# Derived ASAP7 FakeRAM physical-flow model; not a signoff SRAM model
VERSION 5.7 ;
BUSBITCHARS "[]" ;
PROPERTYDEFINITIONS
  MACRO width INTEGER ;
  MACRO depth INTEGER ;
  MACRO banks INTEGER ;
END PROPERTYDEFINITIONS
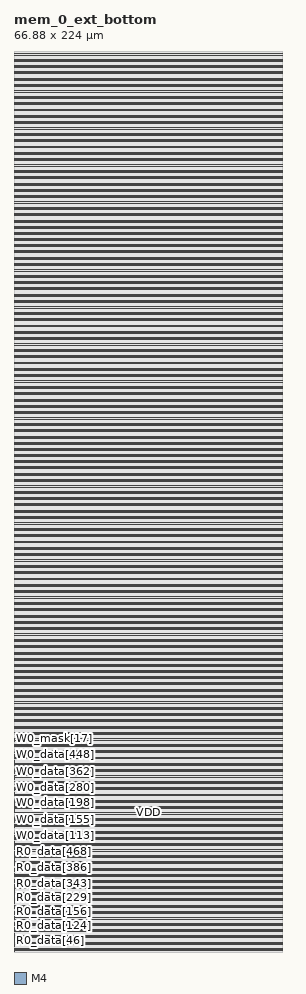
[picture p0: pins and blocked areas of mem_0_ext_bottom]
MACRO mem_0_ext_bottom
  PROPERTY width 512 ;
  PROPERTY depth 512 ;
  PROPERTY banks 1 ;
  FOREIGN mem_0_ext_bottom 0 0 ;
  SYMMETRY X Y ;
  SIZE 66.880 BY 224.000 ;
  CLASS BLOCK ;
  PIN R0_addr[0]
    DIRECTION INPUT ;
    USE SIGNAL ;
    SHAPE ABUTMENT ;
    PORT
      LAYER M4 ;
      RECT 0.000 0.048 0.024 0.072 ;
    END
  END R0_addr[0]
  PIN R0_addr[1]
    DIRECTION INPUT ;
    USE SIGNAL ;
    SHAPE ABUTMENT ;
    PORT
      LAYER M4 ;
      RECT 0.000 0.096 0.024 0.120 ;
    END
  END R0_addr[1]
  PIN R0_addr[2]
    DIRECTION INPUT ;
    USE SIGNAL ;
    SHAPE ABUTMENT ;
    PORT
      LAYER M4 ;
      RECT 0.000 0.144 0.024 0.168 ;
    END
  END R0_addr[2]
  PIN R0_addr[3]
    DIRECTION INPUT ;
    USE SIGNAL ;
    SHAPE ABUTMENT ;
    PORT
      LAYER M4 ;
      RECT 0.000 0.192 0.024 0.216 ;
    END
  END R0_addr[3]
  PIN R0_addr[4]
    DIRECTION INPUT ;
    USE SIGNAL ;
    SHAPE ABUTMENT ;
    PORT
      LAYER M4 ;
      RECT 0.000 0.240 0.024 0.264 ;
    END
  END R0_addr[4]
  PIN R0_addr[5]
    DIRECTION INPUT ;
    USE SIGNAL ;
    SHAPE ABUTMENT ;
    PORT
      LAYER M4 ;
      RECT 0.000 0.288 0.024 0.312 ;
    END
  END R0_addr[5]
  PIN R0_addr[6]
    DIRECTION INPUT ;
    USE SIGNAL ;
    SHAPE ABUTMENT ;
    PORT
      LAYER M4 ;
      RECT 0.000 0.336 0.024 0.360 ;
    END
  END R0_addr[6]
  PIN R0_addr[7]
    DIRECTION INPUT ;
    USE SIGNAL ;
    SHAPE ABUTMENT ;
    PORT
      LAYER M4 ;
      RECT 0.000 0.384 0.024 0.408 ;
    END
  END R0_addr[7]
  PIN R0_addr[8]
    DIRECTION INPUT ;
    USE SIGNAL ;
    SHAPE ABUTMENT ;
    PORT
      LAYER M4 ;
      RECT 0.000 0.432 0.024 0.456 ;
    END
  END R0_addr[8]
  PIN R0_clk
    DIRECTION INPUT ;
    USE SIGNAL ;
    SHAPE ABUTMENT ;
    PORT
      LAYER M4 ;
      RECT 0.000 0.480 0.024 0.504 ;
    END
  END R0_clk
  PIN R0_data[0]
    DIRECTION OUTPUT ;
    USE SIGNAL ;
    SHAPE ABUTMENT ;
    PORT
      LAYER M4 ;
      RECT 0.000 0.528 0.024 0.552 ;
    END
  END R0_data[0]
  PIN R0_data[1]
    DIRECTION OUTPUT ;
    USE SIGNAL ;
    SHAPE ABUTMENT ;
    PORT
      LAYER M4 ;
      RECT 0.000 0.576 0.024 0.600 ;
    END
  END R0_data[1]
  PIN R0_data[2]
    DIRECTION OUTPUT ;
    USE SIGNAL ;
    SHAPE ABUTMENT ;
    PORT
      LAYER M4 ;
      RECT 0.000 0.624 0.024 0.648 ;
    END
  END R0_data[2]
  PIN R0_data[3]
    DIRECTION OUTPUT ;
    USE SIGNAL ;
    SHAPE ABUTMENT ;
    PORT
      LAYER M4 ;
      RECT 0.000 0.672 0.024 0.696 ;
    END
  END R0_data[3]
  PIN R0_data[4]
    DIRECTION OUTPUT ;
    USE SIGNAL ;
    SHAPE ABUTMENT ;
    PORT
      LAYER M4 ;
      RECT 0.000 0.720 0.024 0.744 ;
    END
  END R0_data[4]
  PIN R0_data[5]
    DIRECTION OUTPUT ;
    USE SIGNAL ;
    SHAPE ABUTMENT ;
    PORT
      LAYER M4 ;
      RECT 0.000 0.768 0.024 0.792 ;
    END
  END R0_data[5]
  PIN R0_data[6]
    DIRECTION OUTPUT ;
    USE SIGNAL ;
    SHAPE ABUTMENT ;
    PORT
      LAYER M4 ;
      RECT 0.000 0.816 0.024 0.840 ;
    END
  END R0_data[6]
  PIN R0_data[7]
    DIRECTION OUTPUT ;
    USE SIGNAL ;
    SHAPE ABUTMENT ;
    PORT
      LAYER M4 ;
      RECT 0.000 0.864 0.024 0.888 ;
    END
  END R0_data[7]
  PIN R0_data[8]
    DIRECTION OUTPUT ;
    USE SIGNAL ;
    SHAPE ABUTMENT ;
    PORT
      LAYER M4 ;
      RECT 0.000 0.912 0.024 0.936 ;
    END
  END R0_data[8]
  PIN R0_data[9]
    DIRECTION OUTPUT ;
    USE SIGNAL ;
    SHAPE ABUTMENT ;
    PORT
      LAYER M4 ;
      RECT 0.000 0.960 0.024 0.984 ;
    END
  END R0_data[9]
  PIN R0_data[10]
    DIRECTION OUTPUT ;
    USE SIGNAL ;
    SHAPE ABUTMENT ;
    PORT
      LAYER M4 ;
      RECT 0.000 1.008 0.024 1.032 ;
    END
  END R0_data[10]
  PIN R0_data[11]
    DIRECTION OUTPUT ;
    USE SIGNAL ;
    SHAPE ABUTMENT ;
    PORT
      LAYER M4 ;
      RECT 0.000 1.056 0.024 1.080 ;
    END
  END R0_data[11]
  PIN R0_data[12]
    DIRECTION OUTPUT ;
    USE SIGNAL ;
    SHAPE ABUTMENT ;
    PORT
      LAYER M4 ;
      RECT 0.000 1.104 0.024 1.128 ;
    END
  END R0_data[12]
  PIN R0_data[13]
    DIRECTION OUTPUT ;
    USE SIGNAL ;
    SHAPE ABUTMENT ;
    PORT
      LAYER M4 ;
      RECT 0.000 1.152 0.024 1.176 ;
    END
  END R0_data[13]
  PIN R0_data[14]
    DIRECTION OUTPUT ;
    USE SIGNAL ;
    SHAPE ABUTMENT ;
    PORT
      LAYER M4 ;
      RECT 0.000 1.200 0.024 1.224 ;
    END
  END R0_data[14]
  PIN R0_data[15]
    DIRECTION OUTPUT ;
    USE SIGNAL ;
    SHAPE ABUTMENT ;
    PORT
      LAYER M4 ;
      RECT 0.000 1.248 0.024 1.272 ;
    END
  END R0_data[15]
  PIN R0_data[16]
    DIRECTION OUTPUT ;
    USE SIGNAL ;
    SHAPE ABUTMENT ;
    PORT
      LAYER M4 ;
      RECT 0.000 1.296 0.024 1.320 ;
    END
  END R0_data[16]
  PIN R0_data[17]
    DIRECTION OUTPUT ;
    USE SIGNAL ;
    SHAPE ABUTMENT ;
    PORT
      LAYER M4 ;
      RECT 0.000 1.344 0.024 1.368 ;
    END
  END R0_data[17]
  PIN R0_data[18]
    DIRECTION OUTPUT ;
    USE SIGNAL ;
    SHAPE ABUTMENT ;
    PORT
      LAYER M4 ;
      RECT 0.000 1.392 0.024 1.416 ;
    END
  END R0_data[18]
  PIN R0_data[19]
    DIRECTION OUTPUT ;
    USE SIGNAL ;
    SHAPE ABUTMENT ;
    PORT
      LAYER M4 ;
      RECT 0.000 1.440 0.024 1.464 ;
    END
  END R0_data[19]
  PIN R0_data[20]
    DIRECTION OUTPUT ;
    USE SIGNAL ;
    SHAPE ABUTMENT ;
    PORT
      LAYER M4 ;
      RECT 0.000 1.488 0.024 1.512 ;
    END
  END R0_data[20]
  PIN R0_data[21]
    DIRECTION OUTPUT ;
    USE SIGNAL ;
    SHAPE ABUTMENT ;
    PORT
      LAYER M4 ;
      RECT 0.000 1.536 0.024 1.560 ;
    END
  END R0_data[21]
  PIN R0_data[22]
    DIRECTION OUTPUT ;
    USE SIGNAL ;
    SHAPE ABUTMENT ;
    PORT
      LAYER M4 ;
      RECT 0.000 1.584 0.024 1.608 ;
    END
  END R0_data[22]
  PIN R0_data[23]
    DIRECTION OUTPUT ;
    USE SIGNAL ;
    SHAPE ABUTMENT ;
    PORT
      LAYER M4 ;
      RECT 0.000 1.632 0.024 1.656 ;
    END
  END R0_data[23]
  PIN R0_data[24]
    DIRECTION OUTPUT ;
    USE SIGNAL ;
    SHAPE ABUTMENT ;
    PORT
      LAYER M4 ;
      RECT 0.000 1.680 0.024 1.704 ;
    END
  END R0_data[24]
  PIN R0_data[25]
    DIRECTION OUTPUT ;
    USE SIGNAL ;
    SHAPE ABUTMENT ;
    PORT
      LAYER M4 ;
      RECT 0.000 1.728 0.024 1.752 ;
    END
  END R0_data[25]
  PIN R0_data[26]
    DIRECTION OUTPUT ;
    USE SIGNAL ;
    SHAPE ABUTMENT ;
    PORT
      LAYER M4 ;
      RECT 0.000 1.776 0.024 1.800 ;
    END
  END R0_data[26]
  PIN R0_data[27]
    DIRECTION OUTPUT ;
    USE SIGNAL ;
    SHAPE ABUTMENT ;
    PORT
      LAYER M4 ;
      RECT 0.000 1.824 0.024 1.848 ;
    END
  END R0_data[27]
  PIN R0_data[28]
    DIRECTION OUTPUT ;
    USE SIGNAL ;
    SHAPE ABUTMENT ;
    PORT
      LAYER M4 ;
      RECT 0.000 1.872 0.024 1.896 ;
    END
  END R0_data[28]
  PIN R0_data[29]
    DIRECTION OUTPUT ;
    USE SIGNAL ;
    SHAPE ABUTMENT ;
    PORT
      LAYER M4 ;
      RECT 0.000 1.920 0.024 1.944 ;
    END
  END R0_data[29]
  PIN R0_data[30]
    DIRECTION OUTPUT ;
    USE SIGNAL ;
    SHAPE ABUTMENT ;
    PORT
      LAYER M4 ;
      RECT 0.000 1.968 0.024 1.992 ;
    END
  END R0_data[30]
  PIN R0_data[31]
    DIRECTION OUTPUT ;
    USE SIGNAL ;
    SHAPE ABUTMENT ;
    PORT
      LAYER M4 ;
      RECT 0.000 2.016 0.024 2.040 ;
    END
  END R0_data[31]
  PIN R0_data[32]
    DIRECTION OUTPUT ;
    USE SIGNAL ;
    SHAPE ABUTMENT ;
    PORT
      LAYER M4 ;
      RECT 0.000 2.064 0.024 2.088 ;
    END
  END R0_data[32]
  PIN R0_data[33]
    DIRECTION OUTPUT ;
    USE SIGNAL ;
    SHAPE ABUTMENT ;
    PORT
      LAYER M4 ;
      RECT 0.000 2.112 0.024 2.136 ;
    END
  END R0_data[33]
  PIN R0_data[34]
    DIRECTION OUTPUT ;
    USE SIGNAL ;
    SHAPE ABUTMENT ;
    PORT
      LAYER M4 ;
      RECT 0.000 2.160 0.024 2.184 ;
    END
  END R0_data[34]
  PIN R0_data[35]
    DIRECTION OUTPUT ;
    USE SIGNAL ;
    SHAPE ABUTMENT ;
    PORT
      LAYER M4 ;
      RECT 0.000 2.208 0.024 2.232 ;
    END
  END R0_data[35]
  PIN R0_data[36]
    DIRECTION OUTPUT ;
    USE SIGNAL ;
    SHAPE ABUTMENT ;
    PORT
      LAYER M4 ;
      RECT 0.000 2.256 0.024 2.280 ;
    END
  END R0_data[36]
  PIN R0_data[37]
    DIRECTION OUTPUT ;
    USE SIGNAL ;
    SHAPE ABUTMENT ;
    PORT
      LAYER M4 ;
      RECT 0.000 2.304 0.024 2.328 ;
    END
  END R0_data[37]
  PIN R0_data[38]
    DIRECTION OUTPUT ;
    USE SIGNAL ;
    SHAPE ABUTMENT ;
    PORT
      LAYER M4 ;
      RECT 0.000 2.352 0.024 2.376 ;
    END
  END R0_data[38]
  PIN R0_data[39]
    DIRECTION OUTPUT ;
    USE SIGNAL ;
    SHAPE ABUTMENT ;
    PORT
      LAYER M4 ;
      RECT 0.000 2.400 0.024 2.424 ;
    END
  END R0_data[39]
  PIN R0_data[40]
    DIRECTION OUTPUT ;
    USE SIGNAL ;
    SHAPE ABUTMENT ;
    PORT
      LAYER M4 ;
      RECT 0.000 2.448 0.024 2.472 ;
    END
  END R0_data[40]
  PIN R0_data[41]
    DIRECTION OUTPUT ;
    USE SIGNAL ;
    SHAPE ABUTMENT ;
    PORT
      LAYER M4 ;
      RECT 0.000 2.496 0.024 2.520 ;
    END
  END R0_data[41]
  PIN R0_data[42]
    DIRECTION OUTPUT ;
    USE SIGNAL ;
    SHAPE ABUTMENT ;
    PORT
      LAYER M4 ;
      RECT 0.000 2.544 0.024 2.568 ;
    END
  END R0_data[42]
  PIN R0_data[43]
    DIRECTION OUTPUT ;
    USE SIGNAL ;
    SHAPE ABUTMENT ;
    PORT
      LAYER M4 ;
      RECT 0.000 2.592 0.024 2.616 ;
    END
  END R0_data[43]
  PIN R0_data[44]
    DIRECTION OUTPUT ;
    USE SIGNAL ;
    SHAPE ABUTMENT ;
    PORT
      LAYER M4 ;
      RECT 0.000 2.640 0.024 2.664 ;
    END
  END R0_data[44]
  PIN R0_data[45]
    DIRECTION OUTPUT ;
    USE SIGNAL ;
    SHAPE ABUTMENT ;
    PORT
      LAYER M4 ;
      RECT 0.000 2.688 0.024 2.712 ;
    END
  END R0_data[45]
  PIN R0_data[46]
    DIRECTION OUTPUT ;
    USE SIGNAL ;
    SHAPE ABUTMENT ;
    PORT
      LAYER M4 ;
      RECT 0.000 2.736 0.024 2.760 ;
    END
  END R0_data[46]
  PIN R0_data[47]
    DIRECTION OUTPUT ;
    USE SIGNAL ;
    SHAPE ABUTMENT ;
    PORT
      LAYER M4 ;
      RECT 0.000 2.784 0.024 2.808 ;
    END
  END R0_data[47]
  PIN R0_data[48]
    DIRECTION OUTPUT ;
    USE SIGNAL ;
    SHAPE ABUTMENT ;
    PORT
      LAYER M4 ;
      RECT 0.000 2.832 0.024 2.856 ;
    END
  END R0_data[48]
  PIN R0_data[49]
    DIRECTION OUTPUT ;
    USE SIGNAL ;
    SHAPE ABUTMENT ;
    PORT
      LAYER M4 ;
      RECT 0.000 2.880 0.024 2.904 ;
    END
  END R0_data[49]
  PIN R0_data[50]
    DIRECTION OUTPUT ;
    USE SIGNAL ;
    SHAPE ABUTMENT ;
    PORT
      LAYER M4 ;
      RECT 0.000 2.928 0.024 2.952 ;
    END
  END R0_data[50]
  PIN R0_data[51]
    DIRECTION OUTPUT ;
    USE SIGNAL ;
    SHAPE ABUTMENT ;
    PORT
      LAYER M4 ;
      RECT 0.000 2.976 0.024 3.000 ;
    END
  END R0_data[51]
  PIN R0_data[52]
    DIRECTION OUTPUT ;
    USE SIGNAL ;
    SHAPE ABUTMENT ;
    PORT
      LAYER M4 ;
      RECT 0.000 3.024 0.024 3.048 ;
    END
  END R0_data[52]
  PIN R0_data[53]
    DIRECTION OUTPUT ;
    USE SIGNAL ;
    SHAPE ABUTMENT ;
    PORT
      LAYER M4 ;
      RECT 0.000 3.072 0.024 3.096 ;
    END
  END R0_data[53]
  PIN R0_data[54]
    DIRECTION OUTPUT ;
    USE SIGNAL ;
    SHAPE ABUTMENT ;
    PORT
      LAYER M4 ;
      RECT 0.000 3.120 0.024 3.144 ;
    END
  END R0_data[54]
  PIN R0_data[55]
    DIRECTION OUTPUT ;
    USE SIGNAL ;
    SHAPE ABUTMENT ;
    PORT
      LAYER M4 ;
      RECT 0.000 3.168 0.024 3.192 ;
    END
  END R0_data[55]
  PIN R0_data[56]
    DIRECTION OUTPUT ;
    USE SIGNAL ;
    SHAPE ABUTMENT ;
    PORT
      LAYER M4 ;
      RECT 0.000 3.216 0.024 3.240 ;
    END
  END R0_data[56]
  PIN R0_data[57]
    DIRECTION OUTPUT ;
    USE SIGNAL ;
    SHAPE ABUTMENT ;
    PORT
      LAYER M4 ;
      RECT 0.000 3.264 0.024 3.288 ;
    END
  END R0_data[57]
  PIN R0_data[58]
    DIRECTION OUTPUT ;
    USE SIGNAL ;
    SHAPE ABUTMENT ;
    PORT
      LAYER M4 ;
      RECT 0.000 3.312 0.024 3.336 ;
    END
  END R0_data[58]
  PIN R0_data[59]
    DIRECTION OUTPUT ;
    USE SIGNAL ;
    SHAPE ABUTMENT ;
    PORT
      LAYER M4 ;
      RECT 0.000 3.360 0.024 3.384 ;
    END
  END R0_data[59]
  PIN R0_data[60]
    DIRECTION OUTPUT ;
    USE SIGNAL ;
    SHAPE ABUTMENT ;
    PORT
      LAYER M4 ;
      RECT 0.000 3.408 0.024 3.432 ;
    END
  END R0_data[60]
  PIN R0_data[61]
    DIRECTION OUTPUT ;
    USE SIGNAL ;
    SHAPE ABUTMENT ;
    PORT
      LAYER M4 ;
      RECT 0.000 3.456 0.024 3.480 ;
    END
  END R0_data[61]
  PIN R0_data[62]
    DIRECTION OUTPUT ;
    USE SIGNAL ;
    SHAPE ABUTMENT ;
    PORT
      LAYER M4 ;
      RECT 0.000 3.504 0.024 3.528 ;
    END
  END R0_data[62]
  PIN R0_data[63]
    DIRECTION OUTPUT ;
    USE SIGNAL ;
    SHAPE ABUTMENT ;
    PORT
      LAYER M4 ;
      RECT 0.000 3.552 0.024 3.576 ;
    END
  END R0_data[63]
  PIN R0_data[64]
    DIRECTION OUTPUT ;
    USE SIGNAL ;
    SHAPE ABUTMENT ;
    PORT
      LAYER M4 ;
      RECT 0.000 3.600 0.024 3.624 ;
    END
  END R0_data[64]
  PIN R0_data[65]
    DIRECTION OUTPUT ;
    USE SIGNAL ;
    SHAPE ABUTMENT ;
    PORT
      LAYER M4 ;
      RECT 0.000 3.648 0.024 3.672 ;
    END
  END R0_data[65]
  PIN R0_data[66]
    DIRECTION OUTPUT ;
    USE SIGNAL ;
    SHAPE ABUTMENT ;
    PORT
      LAYER M4 ;
      RECT 0.000 3.696 0.024 3.720 ;
    END
  END R0_data[66]
  PIN R0_data[67]
    DIRECTION OUTPUT ;
    USE SIGNAL ;
    SHAPE ABUTMENT ;
    PORT
      LAYER M4 ;
      RECT 0.000 3.744 0.024 3.768 ;
    END
  END R0_data[67]
  PIN R0_data[68]
    DIRECTION OUTPUT ;
    USE SIGNAL ;
    SHAPE ABUTMENT ;
    PORT
      LAYER M4 ;
      RECT 0.000 3.792 0.024 3.816 ;
    END
  END R0_data[68]
  PIN R0_data[69]
    DIRECTION OUTPUT ;
    USE SIGNAL ;
    SHAPE ABUTMENT ;
    PORT
      LAYER M4 ;
      RECT 0.000 3.840 0.024 3.864 ;
    END
  END R0_data[69]
  PIN R0_data[70]
    DIRECTION OUTPUT ;
    USE SIGNAL ;
    SHAPE ABUTMENT ;
    PORT
      LAYER M4 ;
      RECT 0.000 3.888 0.024 3.912 ;
    END
  END R0_data[70]
  PIN R0_data[71]
    DIRECTION OUTPUT ;
    USE SIGNAL ;
    SHAPE ABUTMENT ;
    PORT
      LAYER M4 ;
      RECT 0.000 3.936 0.024 3.960 ;
    END
  END R0_data[71]
  PIN R0_data[72]
    DIRECTION OUTPUT ;
    USE SIGNAL ;
    SHAPE ABUTMENT ;
    PORT
      LAYER M4 ;
      RECT 0.000 3.984 0.024 4.008 ;
    END
  END R0_data[72]
  PIN R0_data[73]
    DIRECTION OUTPUT ;
    USE SIGNAL ;
    SHAPE ABUTMENT ;
    PORT
      LAYER M4 ;
      RECT 0.000 4.032 0.024 4.056 ;
    END
  END R0_data[73]
  PIN R0_data[74]
    DIRECTION OUTPUT ;
    USE SIGNAL ;
    SHAPE ABUTMENT ;
    PORT
      LAYER M4 ;
      RECT 0.000 4.080 0.024 4.104 ;
    END
  END R0_data[74]
  PIN R0_data[75]
    DIRECTION OUTPUT ;
    USE SIGNAL ;
    SHAPE ABUTMENT ;
    PORT
      LAYER M4 ;
      RECT 0.000 4.128 0.024 4.152 ;
    END
  END R0_data[75]
  PIN R0_data[76]
    DIRECTION OUTPUT ;
    USE SIGNAL ;
    SHAPE ABUTMENT ;
    PORT
      LAYER M4 ;
      RECT 0.000 4.176 0.024 4.200 ;
    END
  END R0_data[76]
  PIN R0_data[77]
    DIRECTION OUTPUT ;
    USE SIGNAL ;
    SHAPE ABUTMENT ;
    PORT
      LAYER M4 ;
      RECT 0.000 4.224 0.024 4.248 ;
    END
  END R0_data[77]
  PIN R0_data[78]
    DIRECTION OUTPUT ;
    USE SIGNAL ;
    SHAPE ABUTMENT ;
    PORT
      LAYER M4 ;
      RECT 0.000 4.272 0.024 4.296 ;
    END
  END R0_data[78]
  PIN R0_data[79]
    DIRECTION OUTPUT ;
    USE SIGNAL ;
    SHAPE ABUTMENT ;
    PORT
      LAYER M4 ;
      RECT 0.000 4.320 0.024 4.344 ;
    END
  END R0_data[79]
  PIN R0_data[80]
    DIRECTION OUTPUT ;
    USE SIGNAL ;
    SHAPE ABUTMENT ;
    PORT
      LAYER M4 ;
      RECT 0.000 4.368 0.024 4.392 ;
    END
  END R0_data[80]
  PIN R0_data[81]
    DIRECTION OUTPUT ;
    USE SIGNAL ;
    SHAPE ABUTMENT ;
    PORT
      LAYER M4 ;
      RECT 0.000 4.416 0.024 4.440 ;
    END
  END R0_data[81]
  PIN R0_data[82]
    DIRECTION OUTPUT ;
    USE SIGNAL ;
    SHAPE ABUTMENT ;
    PORT
      LAYER M4 ;
      RECT 0.000 4.464 0.024 4.488 ;
    END
  END R0_data[82]
  PIN R0_data[83]
    DIRECTION OUTPUT ;
    USE SIGNAL ;
    SHAPE ABUTMENT ;
    PORT
      LAYER M4 ;
      RECT 0.000 4.512 0.024 4.536 ;
    END
  END R0_data[83]
  PIN R0_data[84]
    DIRECTION OUTPUT ;
    USE SIGNAL ;
    SHAPE ABUTMENT ;
    PORT
      LAYER M4 ;
      RECT 0.000 4.560 0.024 4.584 ;
    END
  END R0_data[84]
  PIN R0_data[85]
    DIRECTION OUTPUT ;
    USE SIGNAL ;
    SHAPE ABUTMENT ;
    PORT
      LAYER M4 ;
      RECT 0.000 4.608 0.024 4.632 ;
    END
  END R0_data[85]
  PIN R0_data[86]
    DIRECTION OUTPUT ;
    USE SIGNAL ;
    SHAPE ABUTMENT ;
    PORT
      LAYER M4 ;
      RECT 0.000 4.656 0.024 4.680 ;
    END
  END R0_data[86]
  PIN R0_data[87]
    DIRECTION OUTPUT ;
    USE SIGNAL ;
    SHAPE ABUTMENT ;
    PORT
      LAYER M4 ;
      RECT 0.000 4.704 0.024 4.728 ;
    END
  END R0_data[87]
  PIN R0_data[88]
    DIRECTION OUTPUT ;
    USE SIGNAL ;
    SHAPE ABUTMENT ;
    PORT
      LAYER M4 ;
      RECT 0.000 4.752 0.024 4.776 ;
    END
  END R0_data[88]
  PIN R0_data[89]
    DIRECTION OUTPUT ;
    USE SIGNAL ;
    SHAPE ABUTMENT ;
    PORT
      LAYER M4 ;
      RECT 0.000 4.800 0.024 4.824 ;
    END
  END R0_data[89]
  PIN R0_data[90]
    DIRECTION OUTPUT ;
    USE SIGNAL ;
    SHAPE ABUTMENT ;
    PORT
      LAYER M4 ;
      RECT 0.000 4.848 0.024 4.872 ;
    END
  END R0_data[90]
  PIN R0_data[91]
    DIRECTION OUTPUT ;
    USE SIGNAL ;
    SHAPE ABUTMENT ;
    PORT
      LAYER M4 ;
      RECT 0.000 4.896 0.024 4.920 ;
    END
  END R0_data[91]
  PIN R0_data[92]
    DIRECTION OUTPUT ;
    USE SIGNAL ;
    SHAPE ABUTMENT ;
    PORT
      LAYER M4 ;
      RECT 0.000 4.944 0.024 4.968 ;
    END
  END R0_data[92]
  PIN R0_data[93]
    DIRECTION OUTPUT ;
    USE SIGNAL ;
    SHAPE ABUTMENT ;
    PORT
      LAYER M4 ;
      RECT 0.000 4.992 0.024 5.016 ;
    END
  END R0_data[93]
  PIN R0_data[94]
    DIRECTION OUTPUT ;
    USE SIGNAL ;
    SHAPE ABUTMENT ;
    PORT
      LAYER M4 ;
      RECT 0.000 5.040 0.024 5.064 ;
    END
  END R0_data[94]
  PIN R0_data[95]
    DIRECTION OUTPUT ;
    USE SIGNAL ;
    SHAPE ABUTMENT ;
    PORT
      LAYER M4 ;
      RECT 0.000 5.088 0.024 5.112 ;
    END
  END R0_data[95]
  PIN R0_data[96]
    DIRECTION OUTPUT ;
    USE SIGNAL ;
    SHAPE ABUTMENT ;
    PORT
      LAYER M4 ;
      RECT 0.000 5.136 0.024 5.160 ;
    END
  END R0_data[96]
  PIN R0_data[97]
    DIRECTION OUTPUT ;
    USE SIGNAL ;
    SHAPE ABUTMENT ;
    PORT
      LAYER M4 ;
      RECT 0.000 5.184 0.024 5.208 ;
    END
  END R0_data[97]
  PIN R0_data[98]
    DIRECTION OUTPUT ;
    USE SIGNAL ;
    SHAPE ABUTMENT ;
    PORT
      LAYER M4 ;
      RECT 0.000 5.232 0.024 5.256 ;
    END
  END R0_data[98]
  PIN R0_data[99]
    DIRECTION OUTPUT ;
    USE SIGNAL ;
    SHAPE ABUTMENT ;
    PORT
      LAYER M4 ;
      RECT 0.000 5.280 0.024 5.304 ;
    END
  END R0_data[99]
  PIN R0_data[100]
    DIRECTION OUTPUT ;
    USE SIGNAL ;
    SHAPE ABUTMENT ;
    PORT
      LAYER M4 ;
      RECT 0.000 5.328 0.024 5.352 ;
    END
  END R0_data[100]
  PIN R0_data[101]
    DIRECTION OUTPUT ;
    USE SIGNAL ;
    SHAPE ABUTMENT ;
    PORT
      LAYER M4 ;
      RECT 0.000 5.376 0.024 5.400 ;
    END
  END R0_data[101]
  PIN R0_data[102]
    DIRECTION OUTPUT ;
    USE SIGNAL ;
    SHAPE ABUTMENT ;
    PORT
      LAYER M4 ;
      RECT 0.000 5.424 0.024 5.448 ;
    END
  END R0_data[102]
  PIN R0_data[103]
    DIRECTION OUTPUT ;
    USE SIGNAL ;
    SHAPE ABUTMENT ;
    PORT
      LAYER M4 ;
      RECT 0.000 5.472 0.024 5.496 ;
    END
  END R0_data[103]
  PIN R0_data[104]
    DIRECTION OUTPUT ;
    USE SIGNAL ;
    SHAPE ABUTMENT ;
    PORT
      LAYER M4 ;
      RECT 0.000 5.520 0.024 5.544 ;
    END
  END R0_data[104]
  PIN R0_data[105]
    DIRECTION OUTPUT ;
    USE SIGNAL ;
    SHAPE ABUTMENT ;
    PORT
      LAYER M4 ;
      RECT 0.000 5.568 0.024 5.592 ;
    END
  END R0_data[105]
  PIN R0_data[106]
    DIRECTION OUTPUT ;
    USE SIGNAL ;
    SHAPE ABUTMENT ;
    PORT
      LAYER M4 ;
      RECT 0.000 5.616 0.024 5.640 ;
    END
  END R0_data[106]
  PIN R0_data[107]
    DIRECTION OUTPUT ;
    USE SIGNAL ;
    SHAPE ABUTMENT ;
    PORT
      LAYER M4 ;
      RECT 0.000 5.664 0.024 5.688 ;
    END
  END R0_data[107]
  PIN R0_data[108]
    DIRECTION OUTPUT ;
    USE SIGNAL ;
    SHAPE ABUTMENT ;
    PORT
      LAYER M4 ;
      RECT 0.000 5.712 0.024 5.736 ;
    END
  END R0_data[108]
  PIN R0_data[109]
    DIRECTION OUTPUT ;
    USE SIGNAL ;
    SHAPE ABUTMENT ;
    PORT
      LAYER M4 ;
      RECT 0.000 5.760 0.024 5.784 ;
    END
  END R0_data[109]
  PIN R0_data[110]
    DIRECTION OUTPUT ;
    USE SIGNAL ;
    SHAPE ABUTMENT ;
    PORT
      LAYER M4 ;
      RECT 0.000 5.808 0.024 5.832 ;
    END
  END R0_data[110]
  PIN R0_data[111]
    DIRECTION OUTPUT ;
    USE SIGNAL ;
    SHAPE ABUTMENT ;
    PORT
      LAYER M4 ;
      RECT 0.000 5.856 0.024 5.880 ;
    END
  END R0_data[111]
  PIN R0_data[112]
    DIRECTION OUTPUT ;
    USE SIGNAL ;
    SHAPE ABUTMENT ;
    PORT
      LAYER M4 ;
      RECT 0.000 5.904 0.024 5.928 ;
    END
  END R0_data[112]
  PIN R0_data[113]
    DIRECTION OUTPUT ;
    USE SIGNAL ;
    SHAPE ABUTMENT ;
    PORT
      LAYER M4 ;
      RECT 0.000 5.952 0.024 5.976 ;
    END
  END R0_data[113]
  PIN R0_data[114]
    DIRECTION OUTPUT ;
    USE SIGNAL ;
    SHAPE ABUTMENT ;
    PORT
      LAYER M4 ;
      RECT 0.000 6.000 0.024 6.024 ;
    END
  END R0_data[114]
  PIN R0_data[115]
    DIRECTION OUTPUT ;
    USE SIGNAL ;
    SHAPE ABUTMENT ;
    PORT
      LAYER M4 ;
      RECT 0.000 6.048 0.024 6.072 ;
    END
  END R0_data[115]
  PIN R0_data[116]
    DIRECTION OUTPUT ;
    USE SIGNAL ;
    SHAPE ABUTMENT ;
    PORT
      LAYER M4 ;
      RECT 0.000 6.096 0.024 6.120 ;
    END
  END R0_data[116]
  PIN R0_data[117]
    DIRECTION OUTPUT ;
    USE SIGNAL ;
    SHAPE ABUTMENT ;
    PORT
      LAYER M4 ;
      RECT 0.000 6.144 0.024 6.168 ;
    END
  END R0_data[117]
  PIN R0_data[118]
    DIRECTION OUTPUT ;
    USE SIGNAL ;
    SHAPE ABUTMENT ;
    PORT
      LAYER M4 ;
      RECT 0.000 6.192 0.024 6.216 ;
    END
  END R0_data[118]
  PIN R0_data[119]
    DIRECTION OUTPUT ;
    USE SIGNAL ;
    SHAPE ABUTMENT ;
    PORT
      LAYER M4 ;
      RECT 0.000 6.240 0.024 6.264 ;
    END
  END R0_data[119]
  PIN R0_data[120]
    DIRECTION OUTPUT ;
    USE SIGNAL ;
    SHAPE ABUTMENT ;
    PORT
      LAYER M4 ;
      RECT 0.000 6.288 0.024 6.312 ;
    END
  END R0_data[120]
  PIN R0_data[121]
    DIRECTION OUTPUT ;
    USE SIGNAL ;
    SHAPE ABUTMENT ;
    PORT
      LAYER M4 ;
      RECT 0.000 6.336 0.024 6.360 ;
    END
  END R0_data[121]
  PIN R0_data[122]
    DIRECTION OUTPUT ;
    USE SIGNAL ;
    SHAPE ABUTMENT ;
    PORT
      LAYER M4 ;
      RECT 0.000 6.384 0.024 6.408 ;
    END
  END R0_data[122]
  PIN R0_data[123]
    DIRECTION OUTPUT ;
    USE SIGNAL ;
    SHAPE ABUTMENT ;
    PORT
      LAYER M4 ;
      RECT 0.000 6.432 0.024 6.456 ;
    END
  END R0_data[123]
  PIN R0_data[124]
    DIRECTION OUTPUT ;
    USE SIGNAL ;
    SHAPE ABUTMENT ;
    PORT
      LAYER M4 ;
      RECT 0.000 6.480 0.024 6.504 ;
    END
  END R0_data[124]
  PIN R0_data[125]
    DIRECTION OUTPUT ;
    USE SIGNAL ;
    SHAPE ABUTMENT ;
    PORT
      LAYER M4 ;
      RECT 0.000 6.528 0.024 6.552 ;
    END
  END R0_data[125]
  PIN R0_data[126]
    DIRECTION OUTPUT ;
    USE SIGNAL ;
    SHAPE ABUTMENT ;
    PORT
      LAYER M4 ;
      RECT 0.000 6.576 0.024 6.600 ;
    END
  END R0_data[126]
  PIN R0_data[127]
    DIRECTION OUTPUT ;
    USE SIGNAL ;
    SHAPE ABUTMENT ;
    PORT
      LAYER M4 ;
      RECT 0.000 6.624 0.024 6.648 ;
    END
  END R0_data[127]
  PIN R0_data[128]
    DIRECTION OUTPUT ;
    USE SIGNAL ;
    SHAPE ABUTMENT ;
    PORT
      LAYER M4 ;
      RECT 0.000 6.672 0.024 6.696 ;
    END
  END R0_data[128]
  PIN R0_data[129]
    DIRECTION OUTPUT ;
    USE SIGNAL ;
    SHAPE ABUTMENT ;
    PORT
      LAYER M4 ;
      RECT 0.000 6.720 0.024 6.744 ;
    END
  END R0_data[129]
  PIN R0_data[130]
    DIRECTION OUTPUT ;
    USE SIGNAL ;
    SHAPE ABUTMENT ;
    PORT
      LAYER M4 ;
      RECT 0.000 6.768 0.024 6.792 ;
    END
  END R0_data[130]
  PIN R0_data[131]
    DIRECTION OUTPUT ;
    USE SIGNAL ;
    SHAPE ABUTMENT ;
    PORT
      LAYER M4 ;
      RECT 0.000 6.816 0.024 6.840 ;
    END
  END R0_data[131]
  PIN R0_data[132]
    DIRECTION OUTPUT ;
    USE SIGNAL ;
    SHAPE ABUTMENT ;
    PORT
      LAYER M4 ;
      RECT 0.000 6.864 0.024 6.888 ;
    END
  END R0_data[132]
  PIN R0_data[133]
    DIRECTION OUTPUT ;
    USE SIGNAL ;
    SHAPE ABUTMENT ;
    PORT
      LAYER M4 ;
      RECT 0.000 6.912 0.024 6.936 ;
    END
  END R0_data[133]
  PIN R0_data[134]
    DIRECTION OUTPUT ;
    USE SIGNAL ;
    SHAPE ABUTMENT ;
    PORT
      LAYER M4 ;
      RECT 0.000 6.960 0.024 6.984 ;
    END
  END R0_data[134]
  PIN R0_data[135]
    DIRECTION OUTPUT ;
    USE SIGNAL ;
    SHAPE ABUTMENT ;
    PORT
      LAYER M4 ;
      RECT 0.000 7.008 0.024 7.032 ;
    END
  END R0_data[135]
  PIN R0_data[136]
    DIRECTION OUTPUT ;
    USE SIGNAL ;
    SHAPE ABUTMENT ;
    PORT
      LAYER M4 ;
      RECT 0.000 7.056 0.024 7.080 ;
    END
  END R0_data[136]
  PIN R0_data[137]
    DIRECTION OUTPUT ;
    USE SIGNAL ;
    SHAPE ABUTMENT ;
    PORT
      LAYER M4 ;
      RECT 0.000 7.104 0.024 7.128 ;
    END
  END R0_data[137]
  PIN R0_data[138]
    DIRECTION OUTPUT ;
    USE SIGNAL ;
    SHAPE ABUTMENT ;
    PORT
      LAYER M4 ;
      RECT 0.000 7.152 0.024 7.176 ;
    END
  END R0_data[138]
  PIN R0_data[139]
    DIRECTION OUTPUT ;
    USE SIGNAL ;
    SHAPE ABUTMENT ;
    PORT
      LAYER M4 ;
      RECT 0.000 7.200 0.024 7.224 ;
    END
  END R0_data[139]
  PIN R0_data[140]
    DIRECTION OUTPUT ;
    USE SIGNAL ;
    SHAPE ABUTMENT ;
    PORT
      LAYER M4 ;
      RECT 0.000 7.248 0.024 7.272 ;
    END
  END R0_data[140]
  PIN R0_data[141]
    DIRECTION OUTPUT ;
    USE SIGNAL ;
    SHAPE ABUTMENT ;
    PORT
      LAYER M4 ;
      RECT 0.000 7.296 0.024 7.320 ;
    END
  END R0_data[141]
  PIN R0_data[142]
    DIRECTION OUTPUT ;
    USE SIGNAL ;
    SHAPE ABUTMENT ;
    PORT
      LAYER M4 ;
      RECT 0.000 7.344 0.024 7.368 ;
    END
  END R0_data[142]
  PIN R0_data[143]
    DIRECTION OUTPUT ;
    USE SIGNAL ;
    SHAPE ABUTMENT ;
    PORT
      LAYER M4 ;
      RECT 0.000 7.392 0.024 7.416 ;
    END
  END R0_data[143]
  PIN R0_data[144]
    DIRECTION OUTPUT ;
    USE SIGNAL ;
    SHAPE ABUTMENT ;
    PORT
      LAYER M4 ;
      RECT 0.000 7.440 0.024 7.464 ;
    END
  END R0_data[144]
  PIN R0_data[145]
    DIRECTION OUTPUT ;
    USE SIGNAL ;
    SHAPE ABUTMENT ;
    PORT
      LAYER M4 ;
      RECT 0.000 7.488 0.024 7.512 ;
    END
  END R0_data[145]
  PIN R0_data[146]
    DIRECTION OUTPUT ;
    USE SIGNAL ;
    SHAPE ABUTMENT ;
    PORT
      LAYER M4 ;
      RECT 0.000 7.536 0.024 7.560 ;
    END
  END R0_data[146]
  PIN R0_data[147]
    DIRECTION OUTPUT ;
    USE SIGNAL ;
    SHAPE ABUTMENT ;
    PORT
      LAYER M4 ;
      RECT 0.000 7.584 0.024 7.608 ;
    END
  END R0_data[147]
  PIN R0_data[148]
    DIRECTION OUTPUT ;
    USE SIGNAL ;
    SHAPE ABUTMENT ;
    PORT
      LAYER M4 ;
      RECT 0.000 7.632 0.024 7.656 ;
    END
  END R0_data[148]
  PIN R0_data[149]
    DIRECTION OUTPUT ;
    USE SIGNAL ;
    SHAPE ABUTMENT ;
    PORT
      LAYER M4 ;
      RECT 0.000 7.680 0.024 7.704 ;
    END
  END R0_data[149]
  PIN R0_data[150]
    DIRECTION OUTPUT ;
    USE SIGNAL ;
    SHAPE ABUTMENT ;
    PORT
      LAYER M4 ;
      RECT 0.000 7.728 0.024 7.752 ;
    END
  END R0_data[150]
  PIN R0_data[151]
    DIRECTION OUTPUT ;
    USE SIGNAL ;
    SHAPE ABUTMENT ;
    PORT
      LAYER M4 ;
      RECT 0.000 7.776 0.024 7.800 ;
    END
  END R0_data[151]
  PIN R0_data[152]
    DIRECTION OUTPUT ;
    USE SIGNAL ;
    SHAPE ABUTMENT ;
    PORT
      LAYER M4 ;
      RECT 0.000 7.824 0.024 7.848 ;
    END
  END R0_data[152]
  PIN R0_data[153]
    DIRECTION OUTPUT ;
    USE SIGNAL ;
    SHAPE ABUTMENT ;
    PORT
      LAYER M4 ;
      RECT 0.000 7.872 0.024 7.896 ;
    END
  END R0_data[153]
  PIN R0_data[154]
    DIRECTION OUTPUT ;
    USE SIGNAL ;
    SHAPE ABUTMENT ;
    PORT
      LAYER M4 ;
      RECT 0.000 7.920 0.024 7.944 ;
    END
  END R0_data[154]
  PIN R0_data[155]
    DIRECTION OUTPUT ;
    USE SIGNAL ;
    SHAPE ABUTMENT ;
    PORT
      LAYER M4 ;
      RECT 0.000 7.968 0.024 7.992 ;
    END
  END R0_data[155]
  PIN R0_data[156]
    DIRECTION OUTPUT ;
    USE SIGNAL ;
    SHAPE ABUTMENT ;
    PORT
      LAYER M4 ;
      RECT 0.000 8.016 0.024 8.040 ;
    END
  END R0_data[156]
  PIN R0_data[157]
    DIRECTION OUTPUT ;
    USE SIGNAL ;
    SHAPE ABUTMENT ;
    PORT
      LAYER M4 ;
      RECT 0.000 8.064 0.024 8.088 ;
    END
  END R0_data[157]
  PIN R0_data[158]
    DIRECTION OUTPUT ;
    USE SIGNAL ;
    SHAPE ABUTMENT ;
    PORT
      LAYER M4 ;
      RECT 0.000 8.112 0.024 8.136 ;
    END
  END R0_data[158]
  PIN R0_data[159]
    DIRECTION OUTPUT ;
    USE SIGNAL ;
    SHAPE ABUTMENT ;
    PORT
      LAYER M4 ;
      RECT 0.000 8.160 0.024 8.184 ;
    END
  END R0_data[159]
  PIN R0_data[160]
    DIRECTION OUTPUT ;
    USE SIGNAL ;
    SHAPE ABUTMENT ;
    PORT
      LAYER M4 ;
      RECT 0.000 8.208 0.024 8.232 ;
    END
  END R0_data[160]
  PIN R0_data[161]
    DIRECTION OUTPUT ;
    USE SIGNAL ;
    SHAPE ABUTMENT ;
    PORT
      LAYER M4 ;
      RECT 0.000 8.256 0.024 8.280 ;
    END
  END R0_data[161]
  PIN R0_data[162]
    DIRECTION OUTPUT ;
    USE SIGNAL ;
    SHAPE ABUTMENT ;
    PORT
      LAYER M4 ;
      RECT 0.000 8.304 0.024 8.328 ;
    END
  END R0_data[162]
  PIN R0_data[163]
    DIRECTION OUTPUT ;
    USE SIGNAL ;
    SHAPE ABUTMENT ;
    PORT
      LAYER M4 ;
      RECT 0.000 8.352 0.024 8.376 ;
    END
  END R0_data[163]
  PIN R0_data[164]
    DIRECTION OUTPUT ;
    USE SIGNAL ;
    SHAPE ABUTMENT ;
    PORT
      LAYER M4 ;
      RECT 0.000 8.400 0.024 8.424 ;
    END
  END R0_data[164]
  PIN R0_data[165]
    DIRECTION OUTPUT ;
    USE SIGNAL ;
    SHAPE ABUTMENT ;
    PORT
      LAYER M4 ;
      RECT 0.000 8.448 0.024 8.472 ;
    END
  END R0_data[165]
  PIN R0_data[166]
    DIRECTION OUTPUT ;
    USE SIGNAL ;
    SHAPE ABUTMENT ;
    PORT
      LAYER M4 ;
      RECT 0.000 8.496 0.024 8.520 ;
    END
  END R0_data[166]
  PIN R0_data[167]
    DIRECTION OUTPUT ;
    USE SIGNAL ;
    SHAPE ABUTMENT ;
    PORT
      LAYER M4 ;
      RECT 0.000 8.544 0.024 8.568 ;
    END
  END R0_data[167]
  PIN R0_data[168]
    DIRECTION OUTPUT ;
    USE SIGNAL ;
    SHAPE ABUTMENT ;
    PORT
      LAYER M4 ;
      RECT 0.000 8.592 0.024 8.616 ;
    END
  END R0_data[168]
  PIN R0_data[169]
    DIRECTION OUTPUT ;
    USE SIGNAL ;
    SHAPE ABUTMENT ;
    PORT
      LAYER M4 ;
      RECT 0.000 8.640 0.024 8.664 ;
    END
  END R0_data[169]
  PIN R0_data[170]
    DIRECTION OUTPUT ;
    USE SIGNAL ;
    SHAPE ABUTMENT ;
    PORT
      LAYER M4 ;
      RECT 0.000 8.688 0.024 8.712 ;
    END
  END R0_data[170]
  PIN R0_data[171]
    DIRECTION OUTPUT ;
    USE SIGNAL ;
    SHAPE ABUTMENT ;
    PORT
      LAYER M4 ;
      RECT 0.000 8.736 0.024 8.760 ;
    END
  END R0_data[171]
  PIN R0_data[172]
    DIRECTION OUTPUT ;
    USE SIGNAL ;
    SHAPE ABUTMENT ;
    PORT
      LAYER M4 ;
      RECT 0.000 8.784 0.024 8.808 ;
    END
  END R0_data[172]
  PIN R0_data[173]
    DIRECTION OUTPUT ;
    USE SIGNAL ;
    SHAPE ABUTMENT ;
    PORT
      LAYER M4 ;
      RECT 0.000 8.832 0.024 8.856 ;
    END
  END R0_data[173]
  PIN R0_data[174]
    DIRECTION OUTPUT ;
    USE SIGNAL ;
    SHAPE ABUTMENT ;
    PORT
      LAYER M4 ;
      RECT 0.000 8.880 0.024 8.904 ;
    END
  END R0_data[174]
  PIN R0_data[175]
    DIRECTION OUTPUT ;
    USE SIGNAL ;
    SHAPE ABUTMENT ;
    PORT
      LAYER M4 ;
      RECT 0.000 8.928 0.024 8.952 ;
    END
  END R0_data[175]
  PIN R0_data[176]
    DIRECTION OUTPUT ;
    USE SIGNAL ;
    SHAPE ABUTMENT ;
    PORT
      LAYER M4 ;
      RECT 0.000 8.976 0.024 9.000 ;
    END
  END R0_data[176]
  PIN R0_data[177]
    DIRECTION OUTPUT ;
    USE SIGNAL ;
    SHAPE ABUTMENT ;
    PORT
      LAYER M4 ;
      RECT 0.000 9.024 0.024 9.048 ;
    END
  END R0_data[177]
  PIN R0_data[178]
    DIRECTION OUTPUT ;
    USE SIGNAL ;
    SHAPE ABUTMENT ;
    PORT
      LAYER M4 ;
      RECT 0.000 9.072 0.024 9.096 ;
    END
  END R0_data[178]
  PIN R0_data[179]
    DIRECTION OUTPUT ;
    USE SIGNAL ;
    SHAPE ABUTMENT ;
    PORT
      LAYER M4 ;
      RECT 0.000 9.120 0.024 9.144 ;
    END
  END R0_data[179]
  PIN R0_data[180]
    DIRECTION OUTPUT ;
    USE SIGNAL ;
    SHAPE ABUTMENT ;
    PORT
      LAYER M4 ;
      RECT 0.000 9.168 0.024 9.192 ;
    END
  END R0_data[180]
  PIN R0_data[181]
    DIRECTION OUTPUT ;
    USE SIGNAL ;
    SHAPE ABUTMENT ;
    PORT
      LAYER M4 ;
      RECT 0.000 9.216 0.024 9.240 ;
    END
  END R0_data[181]
  PIN R0_data[182]
    DIRECTION OUTPUT ;
    USE SIGNAL ;
    SHAPE ABUTMENT ;
    PORT
      LAYER M4 ;
      RECT 0.000 9.264 0.024 9.288 ;
    END
  END R0_data[182]
  PIN R0_data[183]
    DIRECTION OUTPUT ;
    USE SIGNAL ;
    SHAPE ABUTMENT ;
    PORT
      LAYER M4 ;
      RECT 0.000 9.312 0.024 9.336 ;
    END
  END R0_data[183]
  PIN R0_data[184]
    DIRECTION OUTPUT ;
    USE SIGNAL ;
    SHAPE ABUTMENT ;
    PORT
      LAYER M4 ;
      RECT 0.000 9.360 0.024 9.384 ;
    END
  END R0_data[184]
  PIN R0_data[185]
    DIRECTION OUTPUT ;
    USE SIGNAL ;
    SHAPE ABUTMENT ;
    PORT
      LAYER M4 ;
      RECT 0.000 9.408 0.024 9.432 ;
    END
  END R0_data[185]
  PIN R0_data[186]
    DIRECTION OUTPUT ;
    USE SIGNAL ;
    SHAPE ABUTMENT ;
    PORT
      LAYER M4 ;
      RECT 0.000 9.456 0.024 9.480 ;
    END
  END R0_data[186]
  PIN R0_data[187]
    DIRECTION OUTPUT ;
    USE SIGNAL ;
    SHAPE ABUTMENT ;
    PORT
      LAYER M4 ;
      RECT 0.000 9.504 0.024 9.528 ;
    END
  END R0_data[187]
  PIN R0_data[188]
    DIRECTION OUTPUT ;
    USE SIGNAL ;
    SHAPE ABUTMENT ;
    PORT
      LAYER M4 ;
      RECT 0.000 9.552 0.024 9.576 ;
    END
  END R0_data[188]
  PIN R0_data[189]
    DIRECTION OUTPUT ;
    USE SIGNAL ;
    SHAPE ABUTMENT ;
    PORT
      LAYER M4 ;
      RECT 0.000 9.600 0.024 9.624 ;
    END
  END R0_data[189]
  PIN R0_data[190]
    DIRECTION OUTPUT ;
    USE SIGNAL ;
    SHAPE ABUTMENT ;
    PORT
      LAYER M4 ;
      RECT 0.000 9.648 0.024 9.672 ;
    END
  END R0_data[190]
  PIN R0_data[191]
    DIRECTION OUTPUT ;
    USE SIGNAL ;
    SHAPE ABUTMENT ;
    PORT
      LAYER M4 ;
      RECT 0.000 9.696 0.024 9.720 ;
    END
  END R0_data[191]
  PIN R0_data[192]
    DIRECTION OUTPUT ;
    USE SIGNAL ;
    SHAPE ABUTMENT ;
    PORT
      LAYER M4 ;
      RECT 0.000 9.744 0.024 9.768 ;
    END
  END R0_data[192]
  PIN R0_data[193]
    DIRECTION OUTPUT ;
    USE SIGNAL ;
    SHAPE ABUTMENT ;
    PORT
      LAYER M4 ;
      RECT 0.000 9.792 0.024 9.816 ;
    END
  END R0_data[193]
  PIN R0_data[194]
    DIRECTION OUTPUT ;
    USE SIGNAL ;
    SHAPE ABUTMENT ;
    PORT
      LAYER M4 ;
      RECT 0.000 9.840 0.024 9.864 ;
    END
  END R0_data[194]
  PIN R0_data[195]
    DIRECTION OUTPUT ;
    USE SIGNAL ;
    SHAPE ABUTMENT ;
    PORT
      LAYER M4 ;
      RECT 0.000 9.888 0.024 9.912 ;
    END
  END R0_data[195]
  PIN R0_data[196]
    DIRECTION OUTPUT ;
    USE SIGNAL ;
    SHAPE ABUTMENT ;
    PORT
      LAYER M4 ;
      RECT 0.000 9.936 0.024 9.960 ;
    END
  END R0_data[196]
  PIN R0_data[197]
    DIRECTION OUTPUT ;
    USE SIGNAL ;
    SHAPE ABUTMENT ;
    PORT
      LAYER M4 ;
      RECT 0.000 9.984 0.024 10.008 ;
    END
  END R0_data[197]
  PIN R0_data[198]
    DIRECTION OUTPUT ;
    USE SIGNAL ;
    SHAPE ABUTMENT ;
    PORT
      LAYER M4 ;
      RECT 0.000 10.032 0.024 10.056 ;
    END
  END R0_data[198]
  PIN R0_data[199]
    DIRECTION OUTPUT ;
    USE SIGNAL ;
    SHAPE ABUTMENT ;
    PORT
      LAYER M4 ;
      RECT 0.000 10.080 0.024 10.104 ;
    END
  END R0_data[199]
  PIN R0_data[200]
    DIRECTION OUTPUT ;
    USE SIGNAL ;
    SHAPE ABUTMENT ;
    PORT
      LAYER M4 ;
      RECT 0.000 10.128 0.024 10.152 ;
    END
  END R0_data[200]
  PIN R0_data[201]
    DIRECTION OUTPUT ;
    USE SIGNAL ;
    SHAPE ABUTMENT ;
    PORT
      LAYER M4 ;
      RECT 0.000 10.176 0.024 10.200 ;
    END
  END R0_data[201]
  PIN R0_data[202]
    DIRECTION OUTPUT ;
    USE SIGNAL ;
    SHAPE ABUTMENT ;
    PORT
      LAYER M4 ;
      RECT 0.000 10.224 0.024 10.248 ;
    END
  END R0_data[202]
  PIN R0_data[203]
    DIRECTION OUTPUT ;
    USE SIGNAL ;
    SHAPE ABUTMENT ;
    PORT
      LAYER M4 ;
      RECT 0.000 10.272 0.024 10.296 ;
    END
  END R0_data[203]
  PIN R0_data[204]
    DIRECTION OUTPUT ;
    USE SIGNAL ;
    SHAPE ABUTMENT ;
    PORT
      LAYER M4 ;
      RECT 0.000 10.320 0.024 10.344 ;
    END
  END R0_data[204]
  PIN R0_data[205]
    DIRECTION OUTPUT ;
    USE SIGNAL ;
    SHAPE ABUTMENT ;
    PORT
      LAYER M4 ;
      RECT 0.000 10.368 0.024 10.392 ;
    END
  END R0_data[205]
  PIN R0_data[206]
    DIRECTION OUTPUT ;
    USE SIGNAL ;
    SHAPE ABUTMENT ;
    PORT
      LAYER M4 ;
      RECT 0.000 10.416 0.024 10.440 ;
    END
  END R0_data[206]
  PIN R0_data[207]
    DIRECTION OUTPUT ;
    USE SIGNAL ;
    SHAPE ABUTMENT ;
    PORT
      LAYER M4 ;
      RECT 0.000 10.464 0.024 10.488 ;
    END
  END R0_data[207]
  PIN R0_data[208]
    DIRECTION OUTPUT ;
    USE SIGNAL ;
    SHAPE ABUTMENT ;
    PORT
      LAYER M4 ;
      RECT 0.000 10.512 0.024 10.536 ;
    END
  END R0_data[208]
  PIN R0_data[209]
    DIRECTION OUTPUT ;
    USE SIGNAL ;
    SHAPE ABUTMENT ;
    PORT
      LAYER M4 ;
      RECT 0.000 10.560 0.024 10.584 ;
    END
  END R0_data[209]
  PIN R0_data[210]
    DIRECTION OUTPUT ;
    USE SIGNAL ;
    SHAPE ABUTMENT ;
    PORT
      LAYER M4 ;
      RECT 0.000 10.608 0.024 10.632 ;
    END
  END R0_data[210]
  PIN R0_data[211]
    DIRECTION OUTPUT ;
    USE SIGNAL ;
    SHAPE ABUTMENT ;
    PORT
      LAYER M4 ;
      RECT 0.000 10.656 0.024 10.680 ;
    END
  END R0_data[211]
  PIN R0_data[212]
    DIRECTION OUTPUT ;
    USE SIGNAL ;
    SHAPE ABUTMENT ;
    PORT
      LAYER M4 ;
      RECT 0.000 10.704 0.024 10.728 ;
    END
  END R0_data[212]
  PIN R0_data[213]
    DIRECTION OUTPUT ;
    USE SIGNAL ;
    SHAPE ABUTMENT ;
    PORT
      LAYER M4 ;
      RECT 0.000 10.752 0.024 10.776 ;
    END
  END R0_data[213]
  PIN R0_data[214]
    DIRECTION OUTPUT ;
    USE SIGNAL ;
    SHAPE ABUTMENT ;
    PORT
      LAYER M4 ;
      RECT 0.000 10.800 0.024 10.824 ;
    END
  END R0_data[214]
  PIN R0_data[215]
    DIRECTION OUTPUT ;
    USE SIGNAL ;
    SHAPE ABUTMENT ;
    PORT
      LAYER M4 ;
      RECT 0.000 10.848 0.024 10.872 ;
    END
  END R0_data[215]
  PIN R0_data[216]
    DIRECTION OUTPUT ;
    USE SIGNAL ;
    SHAPE ABUTMENT ;
    PORT
      LAYER M4 ;
      RECT 0.000 10.896 0.024 10.920 ;
    END
  END R0_data[216]
  PIN R0_data[217]
    DIRECTION OUTPUT ;
    USE SIGNAL ;
    SHAPE ABUTMENT ;
    PORT
      LAYER M4 ;
      RECT 0.000 10.944 0.024 10.968 ;
    END
  END R0_data[217]
  PIN R0_data[218]
    DIRECTION OUTPUT ;
    USE SIGNAL ;
    SHAPE ABUTMENT ;
    PORT
      LAYER M4 ;
      RECT 0.000 10.992 0.024 11.016 ;
    END
  END R0_data[218]
  PIN R0_data[219]
    DIRECTION OUTPUT ;
    USE SIGNAL ;
    SHAPE ABUTMENT ;
    PORT
      LAYER M4 ;
      RECT 0.000 11.040 0.024 11.064 ;
    END
  END R0_data[219]
  PIN R0_data[220]
    DIRECTION OUTPUT ;
    USE SIGNAL ;
    SHAPE ABUTMENT ;
    PORT
      LAYER M4 ;
      RECT 0.000 11.088 0.024 11.112 ;
    END
  END R0_data[220]
  PIN R0_data[221]
    DIRECTION OUTPUT ;
    USE SIGNAL ;
    SHAPE ABUTMENT ;
    PORT
      LAYER M4 ;
      RECT 0.000 11.136 0.024 11.160 ;
    END
  END R0_data[221]
  PIN R0_data[222]
    DIRECTION OUTPUT ;
    USE SIGNAL ;
    SHAPE ABUTMENT ;
    PORT
      LAYER M4 ;
      RECT 0.000 11.184 0.024 11.208 ;
    END
  END R0_data[222]
  PIN R0_data[223]
    DIRECTION OUTPUT ;
    USE SIGNAL ;
    SHAPE ABUTMENT ;
    PORT
      LAYER M4 ;
      RECT 0.000 11.232 0.024 11.256 ;
    END
  END R0_data[223]
  PIN R0_data[224]
    DIRECTION OUTPUT ;
    USE SIGNAL ;
    SHAPE ABUTMENT ;
    PORT
      LAYER M4 ;
      RECT 0.000 11.280 0.024 11.304 ;
    END
  END R0_data[224]
  PIN R0_data[225]
    DIRECTION OUTPUT ;
    USE SIGNAL ;
    SHAPE ABUTMENT ;
    PORT
      LAYER M4 ;
      RECT 0.000 11.328 0.024 11.352 ;
    END
  END R0_data[225]
  PIN R0_data[226]
    DIRECTION OUTPUT ;
    USE SIGNAL ;
    SHAPE ABUTMENT ;
    PORT
      LAYER M4 ;
      RECT 0.000 11.376 0.024 11.400 ;
    END
  END R0_data[226]
  PIN R0_data[227]
    DIRECTION OUTPUT ;
    USE SIGNAL ;
    SHAPE ABUTMENT ;
    PORT
      LAYER M4 ;
      RECT 0.000 11.424 0.024 11.448 ;
    END
  END R0_data[227]
  PIN R0_data[228]
    DIRECTION OUTPUT ;
    USE SIGNAL ;
    SHAPE ABUTMENT ;
    PORT
      LAYER M4 ;
      RECT 0.000 11.472 0.024 11.496 ;
    END
  END R0_data[228]
  PIN R0_data[229]
    DIRECTION OUTPUT ;
    USE SIGNAL ;
    SHAPE ABUTMENT ;
    PORT
      LAYER M4 ;
      RECT 0.000 11.520 0.024 11.544 ;
    END
  END R0_data[229]
  PIN R0_data[230]
    DIRECTION OUTPUT ;
    USE SIGNAL ;
    SHAPE ABUTMENT ;
    PORT
      LAYER M4 ;
      RECT 0.000 11.568 0.024 11.592 ;
    END
  END R0_data[230]
  PIN R0_data[231]
    DIRECTION OUTPUT ;
    USE SIGNAL ;
    SHAPE ABUTMENT ;
    PORT
      LAYER M4 ;
      RECT 0.000 11.616 0.024 11.640 ;
    END
  END R0_data[231]
  PIN R0_data[232]
    DIRECTION OUTPUT ;
    USE SIGNAL ;
    SHAPE ABUTMENT ;
    PORT
      LAYER M4 ;
      RECT 0.000 11.664 0.024 11.688 ;
    END
  END R0_data[232]
  PIN R0_data[233]
    DIRECTION OUTPUT ;
    USE SIGNAL ;
    SHAPE ABUTMENT ;
    PORT
      LAYER M4 ;
      RECT 0.000 11.712 0.024 11.736 ;
    END
  END R0_data[233]
  PIN R0_data[234]
    DIRECTION OUTPUT ;
    USE SIGNAL ;
    SHAPE ABUTMENT ;
    PORT
      LAYER M4 ;
      RECT 0.000 11.760 0.024 11.784 ;
    END
  END R0_data[234]
  PIN R0_data[235]
    DIRECTION OUTPUT ;
    USE SIGNAL ;
    SHAPE ABUTMENT ;
    PORT
      LAYER M4 ;
      RECT 0.000 11.808 0.024 11.832 ;
    END
  END R0_data[235]
  PIN R0_data[236]
    DIRECTION OUTPUT ;
    USE SIGNAL ;
    SHAPE ABUTMENT ;
    PORT
      LAYER M4 ;
      RECT 0.000 11.856 0.024 11.880 ;
    END
  END R0_data[236]
  PIN R0_data[237]
    DIRECTION OUTPUT ;
    USE SIGNAL ;
    SHAPE ABUTMENT ;
    PORT
      LAYER M4 ;
      RECT 0.000 11.904 0.024 11.928 ;
    END
  END R0_data[237]
  PIN R0_data[238]
    DIRECTION OUTPUT ;
    USE SIGNAL ;
    SHAPE ABUTMENT ;
    PORT
      LAYER M4 ;
      RECT 0.000 11.952 0.024 11.976 ;
    END
  END R0_data[238]
  PIN R0_data[239]
    DIRECTION OUTPUT ;
    USE SIGNAL ;
    SHAPE ABUTMENT ;
    PORT
      LAYER M4 ;
      RECT 0.000 12.000 0.024 12.024 ;
    END
  END R0_data[239]
  PIN R0_data[240]
    DIRECTION OUTPUT ;
    USE SIGNAL ;
    SHAPE ABUTMENT ;
    PORT
      LAYER M4 ;
      RECT 0.000 12.048 0.024 12.072 ;
    END
  END R0_data[240]
  PIN R0_data[241]
    DIRECTION OUTPUT ;
    USE SIGNAL ;
    SHAPE ABUTMENT ;
    PORT
      LAYER M4 ;
      RECT 0.000 12.096 0.024 12.120 ;
    END
  END R0_data[241]
  PIN R0_data[242]
    DIRECTION OUTPUT ;
    USE SIGNAL ;
    SHAPE ABUTMENT ;
    PORT
      LAYER M4 ;
      RECT 0.000 12.144 0.024 12.168 ;
    END
  END R0_data[242]
  PIN R0_data[243]
    DIRECTION OUTPUT ;
    USE SIGNAL ;
    SHAPE ABUTMENT ;
    PORT
      LAYER M4 ;
      RECT 0.000 12.192 0.024 12.216 ;
    END
  END R0_data[243]
  PIN R0_data[244]
    DIRECTION OUTPUT ;
    USE SIGNAL ;
    SHAPE ABUTMENT ;
    PORT
      LAYER M4 ;
      RECT 0.000 12.240 0.024 12.264 ;
    END
  END R0_data[244]
  PIN R0_data[245]
    DIRECTION OUTPUT ;
    USE SIGNAL ;
    SHAPE ABUTMENT ;
    PORT
      LAYER M4 ;
      RECT 0.000 12.288 0.024 12.312 ;
    END
  END R0_data[245]
  PIN R0_data[246]
    DIRECTION OUTPUT ;
    USE SIGNAL ;
    SHAPE ABUTMENT ;
    PORT
      LAYER M4 ;
      RECT 0.000 12.336 0.024 12.360 ;
    END
  END R0_data[246]
  PIN R0_data[247]
    DIRECTION OUTPUT ;
    USE SIGNAL ;
    SHAPE ABUTMENT ;
    PORT
      LAYER M4 ;
      RECT 0.000 12.384 0.024 12.408 ;
    END
  END R0_data[247]
  PIN R0_data[248]
    DIRECTION OUTPUT ;
    USE SIGNAL ;
    SHAPE ABUTMENT ;
    PORT
      LAYER M4 ;
      RECT 0.000 12.432 0.024 12.456 ;
    END
  END R0_data[248]
  PIN R0_data[249]
    DIRECTION OUTPUT ;
    USE SIGNAL ;
    SHAPE ABUTMENT ;
    PORT
      LAYER M4 ;
      RECT 0.000 12.480 0.024 12.504 ;
    END
  END R0_data[249]
  PIN R0_data[250]
    DIRECTION OUTPUT ;
    USE SIGNAL ;
    SHAPE ABUTMENT ;
    PORT
      LAYER M4 ;
      RECT 0.000 12.528 0.024 12.552 ;
    END
  END R0_data[250]
  PIN R0_data[251]
    DIRECTION OUTPUT ;
    USE SIGNAL ;
    SHAPE ABUTMENT ;
    PORT
      LAYER M4 ;
      RECT 0.000 12.576 0.024 12.600 ;
    END
  END R0_data[251]
  PIN R0_data[252]
    DIRECTION OUTPUT ;
    USE SIGNAL ;
    SHAPE ABUTMENT ;
    PORT
      LAYER M4 ;
      RECT 0.000 12.624 0.024 12.648 ;
    END
  END R0_data[252]
  PIN R0_data[253]
    DIRECTION OUTPUT ;
    USE SIGNAL ;
    SHAPE ABUTMENT ;
    PORT
      LAYER M4 ;
      RECT 0.000 12.672 0.024 12.696 ;
    END
  END R0_data[253]
  PIN R0_data[254]
    DIRECTION OUTPUT ;
    USE SIGNAL ;
    SHAPE ABUTMENT ;
    PORT
      LAYER M4 ;
      RECT 0.000 12.720 0.024 12.744 ;
    END
  END R0_data[254]
  PIN R0_data[255]
    DIRECTION OUTPUT ;
    USE SIGNAL ;
    SHAPE ABUTMENT ;
    PORT
      LAYER M4 ;
      RECT 0.000 12.768 0.024 12.792 ;
    END
  END R0_data[255]
  PIN R0_data[256]
    DIRECTION OUTPUT ;
    USE SIGNAL ;
    SHAPE ABUTMENT ;
    PORT
      LAYER M4 ;
      RECT 0.000 12.816 0.024 12.840 ;
    END
  END R0_data[256]
  PIN R0_data[257]
    DIRECTION OUTPUT ;
    USE SIGNAL ;
    SHAPE ABUTMENT ;
    PORT
      LAYER M4 ;
      RECT 0.000 12.864 0.024 12.888 ;
    END
  END R0_data[257]
  PIN R0_data[258]
    DIRECTION OUTPUT ;
    USE SIGNAL ;
    SHAPE ABUTMENT ;
    PORT
      LAYER M4 ;
      RECT 0.000 12.912 0.024 12.936 ;
    END
  END R0_data[258]
  PIN R0_data[259]
    DIRECTION OUTPUT ;
    USE SIGNAL ;
    SHAPE ABUTMENT ;
    PORT
      LAYER M4 ;
      RECT 0.000 12.960 0.024 12.984 ;
    END
  END R0_data[259]
  PIN R0_data[260]
    DIRECTION OUTPUT ;
    USE SIGNAL ;
    SHAPE ABUTMENT ;
    PORT
      LAYER M4 ;
      RECT 0.000 13.008 0.024 13.032 ;
    END
  END R0_data[260]
  PIN R0_data[261]
    DIRECTION OUTPUT ;
    USE SIGNAL ;
    SHAPE ABUTMENT ;
    PORT
      LAYER M4 ;
      RECT 0.000 13.056 0.024 13.080 ;
    END
  END R0_data[261]
  PIN R0_data[262]
    DIRECTION OUTPUT ;
    USE SIGNAL ;
    SHAPE ABUTMENT ;
    PORT
      LAYER M4 ;
      RECT 0.000 13.104 0.024 13.128 ;
    END
  END R0_data[262]
  PIN R0_data[263]
    DIRECTION OUTPUT ;
    USE SIGNAL ;
    SHAPE ABUTMENT ;
    PORT
      LAYER M4 ;
      RECT 0.000 13.152 0.024 13.176 ;
    END
  END R0_data[263]
  PIN R0_data[264]
    DIRECTION OUTPUT ;
    USE SIGNAL ;
    SHAPE ABUTMENT ;
    PORT
      LAYER M4 ;
      RECT 0.000 13.200 0.024 13.224 ;
    END
  END R0_data[264]
  PIN R0_data[265]
    DIRECTION OUTPUT ;
    USE SIGNAL ;
    SHAPE ABUTMENT ;
    PORT
      LAYER M4 ;
      RECT 0.000 13.248 0.024 13.272 ;
    END
  END R0_data[265]
  PIN R0_data[266]
    DIRECTION OUTPUT ;
    USE SIGNAL ;
    SHAPE ABUTMENT ;
    PORT
      LAYER M4 ;
      RECT 0.000 13.296 0.024 13.320 ;
    END
  END R0_data[266]
  PIN R0_data[267]
    DIRECTION OUTPUT ;
    USE SIGNAL ;
    SHAPE ABUTMENT ;
    PORT
      LAYER M4 ;
      RECT 0.000 13.344 0.024 13.368 ;
    END
  END R0_data[267]
  PIN R0_data[268]
    DIRECTION OUTPUT ;
    USE SIGNAL ;
    SHAPE ABUTMENT ;
    PORT
      LAYER M4 ;
      RECT 0.000 13.392 0.024 13.416 ;
    END
  END R0_data[268]
  PIN R0_data[269]
    DIRECTION OUTPUT ;
    USE SIGNAL ;
    SHAPE ABUTMENT ;
    PORT
      LAYER M4 ;
      RECT 0.000 13.440 0.024 13.464 ;
    END
  END R0_data[269]
  PIN R0_data[270]
    DIRECTION OUTPUT ;
    USE SIGNAL ;
    SHAPE ABUTMENT ;
    PORT
      LAYER M4 ;
      RECT 0.000 13.488 0.024 13.512 ;
    END
  END R0_data[270]
  PIN R0_data[271]
    DIRECTION OUTPUT ;
    USE SIGNAL ;
    SHAPE ABUTMENT ;
    PORT
      LAYER M4 ;
      RECT 0.000 13.536 0.024 13.560 ;
    END
  END R0_data[271]
  PIN R0_data[272]
    DIRECTION OUTPUT ;
    USE SIGNAL ;
    SHAPE ABUTMENT ;
    PORT
      LAYER M4 ;
      RECT 0.000 13.584 0.024 13.608 ;
    END
  END R0_data[272]
  PIN R0_data[273]
    DIRECTION OUTPUT ;
    USE SIGNAL ;
    SHAPE ABUTMENT ;
    PORT
      LAYER M4 ;
      RECT 0.000 13.632 0.024 13.656 ;
    END
  END R0_data[273]
  PIN R0_data[274]
    DIRECTION OUTPUT ;
    USE SIGNAL ;
    SHAPE ABUTMENT ;
    PORT
      LAYER M4 ;
      RECT 0.000 13.680 0.024 13.704 ;
    END
  END R0_data[274]
  PIN R0_data[275]
    DIRECTION OUTPUT ;
    USE SIGNAL ;
    SHAPE ABUTMENT ;
    PORT
      LAYER M4 ;
      RECT 0.000 13.728 0.024 13.752 ;
    END
  END R0_data[275]
  PIN R0_data[276]
    DIRECTION OUTPUT ;
    USE SIGNAL ;
    SHAPE ABUTMENT ;
    PORT
      LAYER M4 ;
      RECT 0.000 13.776 0.024 13.800 ;
    END
  END R0_data[276]
  PIN R0_data[277]
    DIRECTION OUTPUT ;
    USE SIGNAL ;
    SHAPE ABUTMENT ;
    PORT
      LAYER M4 ;
      RECT 0.000 13.824 0.024 13.848 ;
    END
  END R0_data[277]
  PIN R0_data[278]
    DIRECTION OUTPUT ;
    USE SIGNAL ;
    SHAPE ABUTMENT ;
    PORT
      LAYER M4 ;
      RECT 0.000 13.872 0.024 13.896 ;
    END
  END R0_data[278]
  PIN R0_data[279]
    DIRECTION OUTPUT ;
    USE SIGNAL ;
    SHAPE ABUTMENT ;
    PORT
      LAYER M4 ;
      RECT 0.000 13.920 0.024 13.944 ;
    END
  END R0_data[279]
  PIN R0_data[280]
    DIRECTION OUTPUT ;
    USE SIGNAL ;
    SHAPE ABUTMENT ;
    PORT
      LAYER M4 ;
      RECT 0.000 13.968 0.024 13.992 ;
    END
  END R0_data[280]
  PIN R0_data[281]
    DIRECTION OUTPUT ;
    USE SIGNAL ;
    SHAPE ABUTMENT ;
    PORT
      LAYER M4 ;
      RECT 0.000 14.016 0.024 14.040 ;
    END
  END R0_data[281]
  PIN R0_data[282]
    DIRECTION OUTPUT ;
    USE SIGNAL ;
    SHAPE ABUTMENT ;
    PORT
      LAYER M4 ;
      RECT 0.000 14.064 0.024 14.088 ;
    END
  END R0_data[282]
  PIN R0_data[283]
    DIRECTION OUTPUT ;
    USE SIGNAL ;
    SHAPE ABUTMENT ;
    PORT
      LAYER M4 ;
      RECT 0.000 14.112 0.024 14.136 ;
    END
  END R0_data[283]
  PIN R0_data[284]
    DIRECTION OUTPUT ;
    USE SIGNAL ;
    SHAPE ABUTMENT ;
    PORT
      LAYER M4 ;
      RECT 0.000 14.160 0.024 14.184 ;
    END
  END R0_data[284]
  PIN R0_data[285]
    DIRECTION OUTPUT ;
    USE SIGNAL ;
    SHAPE ABUTMENT ;
    PORT
      LAYER M4 ;
      RECT 0.000 14.208 0.024 14.232 ;
    END
  END R0_data[285]
  PIN R0_data[286]
    DIRECTION OUTPUT ;
    USE SIGNAL ;
    SHAPE ABUTMENT ;
    PORT
      LAYER M4 ;
      RECT 0.000 14.256 0.024 14.280 ;
    END
  END R0_data[286]
  PIN R0_data[287]
    DIRECTION OUTPUT ;
    USE SIGNAL ;
    SHAPE ABUTMENT ;
    PORT
      LAYER M4 ;
      RECT 0.000 14.304 0.024 14.328 ;
    END
  END R0_data[287]
  PIN R0_data[288]
    DIRECTION OUTPUT ;
    USE SIGNAL ;
    SHAPE ABUTMENT ;
    PORT
      LAYER M4 ;
      RECT 0.000 14.352 0.024 14.376 ;
    END
  END R0_data[288]
  PIN R0_data[289]
    DIRECTION OUTPUT ;
    USE SIGNAL ;
    SHAPE ABUTMENT ;
    PORT
      LAYER M4 ;
      RECT 0.000 14.400 0.024 14.424 ;
    END
  END R0_data[289]
  PIN R0_data[290]
    DIRECTION OUTPUT ;
    USE SIGNAL ;
    SHAPE ABUTMENT ;
    PORT
      LAYER M4 ;
      RECT 0.000 14.448 0.024 14.472 ;
    END
  END R0_data[290]
  PIN R0_data[291]
    DIRECTION OUTPUT ;
    USE SIGNAL ;
    SHAPE ABUTMENT ;
    PORT
      LAYER M4 ;
      RECT 0.000 14.496 0.024 14.520 ;
    END
  END R0_data[291]
  PIN R0_data[292]
    DIRECTION OUTPUT ;
    USE SIGNAL ;
    SHAPE ABUTMENT ;
    PORT
      LAYER M4 ;
      RECT 0.000 14.544 0.024 14.568 ;
    END
  END R0_data[292]
  PIN R0_data[293]
    DIRECTION OUTPUT ;
    USE SIGNAL ;
    SHAPE ABUTMENT ;
    PORT
      LAYER M4 ;
      RECT 0.000 14.592 0.024 14.616 ;
    END
  END R0_data[293]
  PIN R0_data[294]
    DIRECTION OUTPUT ;
    USE SIGNAL ;
    SHAPE ABUTMENT ;
    PORT
      LAYER M4 ;
      RECT 0.000 14.640 0.024 14.664 ;
    END
  END R0_data[294]
  PIN R0_data[295]
    DIRECTION OUTPUT ;
    USE SIGNAL ;
    SHAPE ABUTMENT ;
    PORT
      LAYER M4 ;
      RECT 0.000 14.688 0.024 14.712 ;
    END
  END R0_data[295]
  PIN R0_data[296]
    DIRECTION OUTPUT ;
    USE SIGNAL ;
    SHAPE ABUTMENT ;
    PORT
      LAYER M4 ;
      RECT 0.000 14.736 0.024 14.760 ;
    END
  END R0_data[296]
  PIN R0_data[297]
    DIRECTION OUTPUT ;
    USE SIGNAL ;
    SHAPE ABUTMENT ;
    PORT
      LAYER M4 ;
      RECT 0.000 14.784 0.024 14.808 ;
    END
  END R0_data[297]
  PIN R0_data[298]
    DIRECTION OUTPUT ;
    USE SIGNAL ;
    SHAPE ABUTMENT ;
    PORT
      LAYER M4 ;
      RECT 0.000 14.832 0.024 14.856 ;
    END
  END R0_data[298]
  PIN R0_data[299]
    DIRECTION OUTPUT ;
    USE SIGNAL ;
    SHAPE ABUTMENT ;
    PORT
      LAYER M4 ;
      RECT 0.000 14.880 0.024 14.904 ;
    END
  END R0_data[299]
  PIN R0_data[300]
    DIRECTION OUTPUT ;
    USE SIGNAL ;
    SHAPE ABUTMENT ;
    PORT
      LAYER M4 ;
      RECT 0.000 14.928 0.024 14.952 ;
    END
  END R0_data[300]
  PIN R0_data[301]
    DIRECTION OUTPUT ;
    USE SIGNAL ;
    SHAPE ABUTMENT ;
    PORT
      LAYER M4 ;
      RECT 0.000 14.976 0.024 15.000 ;
    END
  END R0_data[301]
  PIN R0_data[302]
    DIRECTION OUTPUT ;
    USE SIGNAL ;
    SHAPE ABUTMENT ;
    PORT
      LAYER M4 ;
      RECT 0.000 15.024 0.024 15.048 ;
    END
  END R0_data[302]
  PIN R0_data[303]
    DIRECTION OUTPUT ;
    USE SIGNAL ;
    SHAPE ABUTMENT ;
    PORT
      LAYER M4 ;
      RECT 0.000 15.072 0.024 15.096 ;
    END
  END R0_data[303]
  PIN R0_data[304]
    DIRECTION OUTPUT ;
    USE SIGNAL ;
    SHAPE ABUTMENT ;
    PORT
      LAYER M4 ;
      RECT 0.000 15.120 0.024 15.144 ;
    END
  END R0_data[304]
  PIN R0_data[305]
    DIRECTION OUTPUT ;
    USE SIGNAL ;
    SHAPE ABUTMENT ;
    PORT
      LAYER M4 ;
      RECT 0.000 15.168 0.024 15.192 ;
    END
  END R0_data[305]
  PIN R0_data[306]
    DIRECTION OUTPUT ;
    USE SIGNAL ;
    SHAPE ABUTMENT ;
    PORT
      LAYER M4 ;
      RECT 0.000 15.216 0.024 15.240 ;
    END
  END R0_data[306]
  PIN R0_data[307]
    DIRECTION OUTPUT ;
    USE SIGNAL ;
    SHAPE ABUTMENT ;
    PORT
      LAYER M4 ;
      RECT 0.000 15.264 0.024 15.288 ;
    END
  END R0_data[307]
  PIN R0_data[308]
    DIRECTION OUTPUT ;
    USE SIGNAL ;
    SHAPE ABUTMENT ;
    PORT
      LAYER M4 ;
      RECT 0.000 15.312 0.024 15.336 ;
    END
  END R0_data[308]
  PIN R0_data[309]
    DIRECTION OUTPUT ;
    USE SIGNAL ;
    SHAPE ABUTMENT ;
    PORT
      LAYER M4 ;
      RECT 0.000 15.360 0.024 15.384 ;
    END
  END R0_data[309]
  PIN R0_data[310]
    DIRECTION OUTPUT ;
    USE SIGNAL ;
    SHAPE ABUTMENT ;
    PORT
      LAYER M4 ;
      RECT 0.000 15.408 0.024 15.432 ;
    END
  END R0_data[310]
  PIN R0_data[311]
    DIRECTION OUTPUT ;
    USE SIGNAL ;
    SHAPE ABUTMENT ;
    PORT
      LAYER M4 ;
      RECT 0.000 15.456 0.024 15.480 ;
    END
  END R0_data[311]
  PIN R0_data[312]
    DIRECTION OUTPUT ;
    USE SIGNAL ;
    SHAPE ABUTMENT ;
    PORT
      LAYER M4 ;
      RECT 0.000 15.504 0.024 15.528 ;
    END
  END R0_data[312]
  PIN R0_data[313]
    DIRECTION OUTPUT ;
    USE SIGNAL ;
    SHAPE ABUTMENT ;
    PORT
      LAYER M4 ;
      RECT 0.000 15.552 0.024 15.576 ;
    END
  END R0_data[313]
  PIN R0_data[314]
    DIRECTION OUTPUT ;
    USE SIGNAL ;
    SHAPE ABUTMENT ;
    PORT
      LAYER M4 ;
      RECT 0.000 15.600 0.024 15.624 ;
    END
  END R0_data[314]
  PIN R0_data[315]
    DIRECTION OUTPUT ;
    USE SIGNAL ;
    SHAPE ABUTMENT ;
    PORT
      LAYER M4 ;
      RECT 0.000 15.648 0.024 15.672 ;
    END
  END R0_data[315]
  PIN R0_data[316]
    DIRECTION OUTPUT ;
    USE SIGNAL ;
    SHAPE ABUTMENT ;
    PORT
      LAYER M4 ;
      RECT 0.000 15.696 0.024 15.720 ;
    END
  END R0_data[316]
  PIN R0_data[317]
    DIRECTION OUTPUT ;
    USE SIGNAL ;
    SHAPE ABUTMENT ;
    PORT
      LAYER M4 ;
      RECT 0.000 15.744 0.024 15.768 ;
    END
  END R0_data[317]
  PIN R0_data[318]
    DIRECTION OUTPUT ;
    USE SIGNAL ;
    SHAPE ABUTMENT ;
    PORT
      LAYER M4 ;
      RECT 0.000 15.792 0.024 15.816 ;
    END
  END R0_data[318]
  PIN R0_data[319]
    DIRECTION OUTPUT ;
    USE SIGNAL ;
    SHAPE ABUTMENT ;
    PORT
      LAYER M4 ;
      RECT 0.000 15.840 0.024 15.864 ;
    END
  END R0_data[319]
  PIN R0_data[320]
    DIRECTION OUTPUT ;
    USE SIGNAL ;
    SHAPE ABUTMENT ;
    PORT
      LAYER M4 ;
      RECT 0.000 15.888 0.024 15.912 ;
    END
  END R0_data[320]
  PIN R0_data[321]
    DIRECTION OUTPUT ;
    USE SIGNAL ;
    SHAPE ABUTMENT ;
    PORT
      LAYER M4 ;
      RECT 0.000 15.936 0.024 15.960 ;
    END
  END R0_data[321]
  PIN R0_data[322]
    DIRECTION OUTPUT ;
    USE SIGNAL ;
    SHAPE ABUTMENT ;
    PORT
      LAYER M4 ;
      RECT 0.000 15.984 0.024 16.008 ;
    END
  END R0_data[322]
  PIN R0_data[323]
    DIRECTION OUTPUT ;
    USE SIGNAL ;
    SHAPE ABUTMENT ;
    PORT
      LAYER M4 ;
      RECT 0.000 16.032 0.024 16.056 ;
    END
  END R0_data[323]
  PIN R0_data[324]
    DIRECTION OUTPUT ;
    USE SIGNAL ;
    SHAPE ABUTMENT ;
    PORT
      LAYER M4 ;
      RECT 0.000 16.080 0.024 16.104 ;
    END
  END R0_data[324]
  PIN R0_data[325]
    DIRECTION OUTPUT ;
    USE SIGNAL ;
    SHAPE ABUTMENT ;
    PORT
      LAYER M4 ;
      RECT 0.000 16.128 0.024 16.152 ;
    END
  END R0_data[325]
  PIN R0_data[326]
    DIRECTION OUTPUT ;
    USE SIGNAL ;
    SHAPE ABUTMENT ;
    PORT
      LAYER M4 ;
      RECT 0.000 16.176 0.024 16.200 ;
    END
  END R0_data[326]
  PIN R0_data[327]
    DIRECTION OUTPUT ;
    USE SIGNAL ;
    SHAPE ABUTMENT ;
    PORT
      LAYER M4 ;
      RECT 0.000 16.224 0.024 16.248 ;
    END
  END R0_data[327]
  PIN R0_data[328]
    DIRECTION OUTPUT ;
    USE SIGNAL ;
    SHAPE ABUTMENT ;
    PORT
      LAYER M4 ;
      RECT 0.000 16.272 0.024 16.296 ;
    END
  END R0_data[328]
  PIN R0_data[329]
    DIRECTION OUTPUT ;
    USE SIGNAL ;
    SHAPE ABUTMENT ;
    PORT
      LAYER M4 ;
      RECT 0.000 16.320 0.024 16.344 ;
    END
  END R0_data[329]
  PIN R0_data[330]
    DIRECTION OUTPUT ;
    USE SIGNAL ;
    SHAPE ABUTMENT ;
    PORT
      LAYER M4 ;
      RECT 0.000 16.368 0.024 16.392 ;
    END
  END R0_data[330]
  PIN R0_data[331]
    DIRECTION OUTPUT ;
    USE SIGNAL ;
    SHAPE ABUTMENT ;
    PORT
      LAYER M4 ;
      RECT 0.000 16.416 0.024 16.440 ;
    END
  END R0_data[331]
  PIN R0_data[332]
    DIRECTION OUTPUT ;
    USE SIGNAL ;
    SHAPE ABUTMENT ;
    PORT
      LAYER M4 ;
      RECT 0.000 16.464 0.024 16.488 ;
    END
  END R0_data[332]
  PIN R0_data[333]
    DIRECTION OUTPUT ;
    USE SIGNAL ;
    SHAPE ABUTMENT ;
    PORT
      LAYER M4 ;
      RECT 0.000 16.512 0.024 16.536 ;
    END
  END R0_data[333]
  PIN R0_data[334]
    DIRECTION OUTPUT ;
    USE SIGNAL ;
    SHAPE ABUTMENT ;
    PORT
      LAYER M4 ;
      RECT 0.000 16.560 0.024 16.584 ;
    END
  END R0_data[334]
  PIN R0_data[335]
    DIRECTION OUTPUT ;
    USE SIGNAL ;
    SHAPE ABUTMENT ;
    PORT
      LAYER M4 ;
      RECT 0.000 16.608 0.024 16.632 ;
    END
  END R0_data[335]
  PIN R0_data[336]
    DIRECTION OUTPUT ;
    USE SIGNAL ;
    SHAPE ABUTMENT ;
    PORT
      LAYER M4 ;
      RECT 0.000 16.656 0.024 16.680 ;
    END
  END R0_data[336]
  PIN R0_data[337]
    DIRECTION OUTPUT ;
    USE SIGNAL ;
    SHAPE ABUTMENT ;
    PORT
      LAYER M4 ;
      RECT 0.000 16.704 0.024 16.728 ;
    END
  END R0_data[337]
  PIN R0_data[338]
    DIRECTION OUTPUT ;
    USE SIGNAL ;
    SHAPE ABUTMENT ;
    PORT
      LAYER M4 ;
      RECT 0.000 16.752 0.024 16.776 ;
    END
  END R0_data[338]
  PIN R0_data[339]
    DIRECTION OUTPUT ;
    USE SIGNAL ;
    SHAPE ABUTMENT ;
    PORT
      LAYER M4 ;
      RECT 0.000 16.800 0.024 16.824 ;
    END
  END R0_data[339]
  PIN R0_data[340]
    DIRECTION OUTPUT ;
    USE SIGNAL ;
    SHAPE ABUTMENT ;
    PORT
      LAYER M4 ;
      RECT 0.000 16.848 0.024 16.872 ;
    END
  END R0_data[340]
  PIN R0_data[341]
    DIRECTION OUTPUT ;
    USE SIGNAL ;
    SHAPE ABUTMENT ;
    PORT
      LAYER M4 ;
      RECT 0.000 16.896 0.024 16.920 ;
    END
  END R0_data[341]
  PIN R0_data[342]
    DIRECTION OUTPUT ;
    USE SIGNAL ;
    SHAPE ABUTMENT ;
    PORT
      LAYER M4 ;
      RECT 0.000 16.944 0.024 16.968 ;
    END
  END R0_data[342]
  PIN R0_data[343]
    DIRECTION OUTPUT ;
    USE SIGNAL ;
    SHAPE ABUTMENT ;
    PORT
      LAYER M4 ;
      RECT 0.000 16.992 0.024 17.016 ;
    END
  END R0_data[343]
  PIN R0_data[344]
    DIRECTION OUTPUT ;
    USE SIGNAL ;
    SHAPE ABUTMENT ;
    PORT
      LAYER M4 ;
      RECT 0.000 17.040 0.024 17.064 ;
    END
  END R0_data[344]
  PIN R0_data[345]
    DIRECTION OUTPUT ;
    USE SIGNAL ;
    SHAPE ABUTMENT ;
    PORT
      LAYER M4 ;
      RECT 0.000 17.088 0.024 17.112 ;
    END
  END R0_data[345]
  PIN R0_data[346]
    DIRECTION OUTPUT ;
    USE SIGNAL ;
    SHAPE ABUTMENT ;
    PORT
      LAYER M4 ;
      RECT 0.000 17.136 0.024 17.160 ;
    END
  END R0_data[346]
  PIN R0_data[347]
    DIRECTION OUTPUT ;
    USE SIGNAL ;
    SHAPE ABUTMENT ;
    PORT
      LAYER M4 ;
      RECT 0.000 17.184 0.024 17.208 ;
    END
  END R0_data[347]
  PIN R0_data[348]
    DIRECTION OUTPUT ;
    USE SIGNAL ;
    SHAPE ABUTMENT ;
    PORT
      LAYER M4 ;
      RECT 0.000 17.232 0.024 17.256 ;
    END
  END R0_data[348]
  PIN R0_data[349]
    DIRECTION OUTPUT ;
    USE SIGNAL ;
    SHAPE ABUTMENT ;
    PORT
      LAYER M4 ;
      RECT 0.000 17.280 0.024 17.304 ;
    END
  END R0_data[349]
  PIN R0_data[350]
    DIRECTION OUTPUT ;
    USE SIGNAL ;
    SHAPE ABUTMENT ;
    PORT
      LAYER M4 ;
      RECT 0.000 17.328 0.024 17.352 ;
    END
  END R0_data[350]
  PIN R0_data[351]
    DIRECTION OUTPUT ;
    USE SIGNAL ;
    SHAPE ABUTMENT ;
    PORT
      LAYER M4 ;
      RECT 0.000 17.376 0.024 17.400 ;
    END
  END R0_data[351]
  PIN R0_data[352]
    DIRECTION OUTPUT ;
    USE SIGNAL ;
    SHAPE ABUTMENT ;
    PORT
      LAYER M4 ;
      RECT 0.000 17.424 0.024 17.448 ;
    END
  END R0_data[352]
  PIN R0_data[353]
    DIRECTION OUTPUT ;
    USE SIGNAL ;
    SHAPE ABUTMENT ;
    PORT
      LAYER M4 ;
      RECT 0.000 17.472 0.024 17.496 ;
    END
  END R0_data[353]
  PIN R0_data[354]
    DIRECTION OUTPUT ;
    USE SIGNAL ;
    SHAPE ABUTMENT ;
    PORT
      LAYER M4 ;
      RECT 0.000 17.520 0.024 17.544 ;
    END
  END R0_data[354]
  PIN R0_data[355]
    DIRECTION OUTPUT ;
    USE SIGNAL ;
    SHAPE ABUTMENT ;
    PORT
      LAYER M4 ;
      RECT 0.000 17.568 0.024 17.592 ;
    END
  END R0_data[355]
  PIN R0_data[356]
    DIRECTION OUTPUT ;
    USE SIGNAL ;
    SHAPE ABUTMENT ;
    PORT
      LAYER M4 ;
      RECT 0.000 17.616 0.024 17.640 ;
    END
  END R0_data[356]
  PIN R0_data[357]
    DIRECTION OUTPUT ;
    USE SIGNAL ;
    SHAPE ABUTMENT ;
    PORT
      LAYER M4 ;
      RECT 0.000 17.664 0.024 17.688 ;
    END
  END R0_data[357]
  PIN R0_data[358]
    DIRECTION OUTPUT ;
    USE SIGNAL ;
    SHAPE ABUTMENT ;
    PORT
      LAYER M4 ;
      RECT 0.000 17.712 0.024 17.736 ;
    END
  END R0_data[358]
  PIN R0_data[359]
    DIRECTION OUTPUT ;
    USE SIGNAL ;
    SHAPE ABUTMENT ;
    PORT
      LAYER M4 ;
      RECT 0.000 17.760 0.024 17.784 ;
    END
  END R0_data[359]
  PIN R0_data[360]
    DIRECTION OUTPUT ;
    USE SIGNAL ;
    SHAPE ABUTMENT ;
    PORT
      LAYER M4 ;
      RECT 0.000 17.808 0.024 17.832 ;
    END
  END R0_data[360]
  PIN R0_data[361]
    DIRECTION OUTPUT ;
    USE SIGNAL ;
    SHAPE ABUTMENT ;
    PORT
      LAYER M4 ;
      RECT 0.000 17.856 0.024 17.880 ;
    END
  END R0_data[361]
  PIN R0_data[362]
    DIRECTION OUTPUT ;
    USE SIGNAL ;
    SHAPE ABUTMENT ;
    PORT
      LAYER M4 ;
      RECT 0.000 17.904 0.024 17.928 ;
    END
  END R0_data[362]
  PIN R0_data[363]
    DIRECTION OUTPUT ;
    USE SIGNAL ;
    SHAPE ABUTMENT ;
    PORT
      LAYER M4 ;
      RECT 0.000 17.952 0.024 17.976 ;
    END
  END R0_data[363]
  PIN R0_data[364]
    DIRECTION OUTPUT ;
    USE SIGNAL ;
    SHAPE ABUTMENT ;
    PORT
      LAYER M4 ;
      RECT 0.000 18.000 0.024 18.024 ;
    END
  END R0_data[364]
  PIN R0_data[365]
    DIRECTION OUTPUT ;
    USE SIGNAL ;
    SHAPE ABUTMENT ;
    PORT
      LAYER M4 ;
      RECT 0.000 18.048 0.024 18.072 ;
    END
  END R0_data[365]
  PIN R0_data[366]
    DIRECTION OUTPUT ;
    USE SIGNAL ;
    SHAPE ABUTMENT ;
    PORT
      LAYER M4 ;
      RECT 0.000 18.096 0.024 18.120 ;
    END
  END R0_data[366]
  PIN R0_data[367]
    DIRECTION OUTPUT ;
    USE SIGNAL ;
    SHAPE ABUTMENT ;
    PORT
      LAYER M4 ;
      RECT 0.000 18.144 0.024 18.168 ;
    END
  END R0_data[367]
  PIN R0_data[368]
    DIRECTION OUTPUT ;
    USE SIGNAL ;
    SHAPE ABUTMENT ;
    PORT
      LAYER M4 ;
      RECT 0.000 18.192 0.024 18.216 ;
    END
  END R0_data[368]
  PIN R0_data[369]
    DIRECTION OUTPUT ;
    USE SIGNAL ;
    SHAPE ABUTMENT ;
    PORT
      LAYER M4 ;
      RECT 0.000 18.240 0.024 18.264 ;
    END
  END R0_data[369]
  PIN R0_data[370]
    DIRECTION OUTPUT ;
    USE SIGNAL ;
    SHAPE ABUTMENT ;
    PORT
      LAYER M4 ;
      RECT 0.000 18.288 0.024 18.312 ;
    END
  END R0_data[370]
  PIN R0_data[371]
    DIRECTION OUTPUT ;
    USE SIGNAL ;
    SHAPE ABUTMENT ;
    PORT
      LAYER M4 ;
      RECT 0.000 18.336 0.024 18.360 ;
    END
  END R0_data[371]
  PIN R0_data[372]
    DIRECTION OUTPUT ;
    USE SIGNAL ;
    SHAPE ABUTMENT ;
    PORT
      LAYER M4 ;
      RECT 0.000 18.384 0.024 18.408 ;
    END
  END R0_data[372]
  PIN R0_data[373]
    DIRECTION OUTPUT ;
    USE SIGNAL ;
    SHAPE ABUTMENT ;
    PORT
      LAYER M4 ;
      RECT 0.000 18.432 0.024 18.456 ;
    END
  END R0_data[373]
  PIN R0_data[374]
    DIRECTION OUTPUT ;
    USE SIGNAL ;
    SHAPE ABUTMENT ;
    PORT
      LAYER M4 ;
      RECT 0.000 18.480 0.024 18.504 ;
    END
  END R0_data[374]
  PIN R0_data[375]
    DIRECTION OUTPUT ;
    USE SIGNAL ;
    SHAPE ABUTMENT ;
    PORT
      LAYER M4 ;
      RECT 0.000 18.528 0.024 18.552 ;
    END
  END R0_data[375]
  PIN R0_data[376]
    DIRECTION OUTPUT ;
    USE SIGNAL ;
    SHAPE ABUTMENT ;
    PORT
      LAYER M4 ;
      RECT 0.000 18.576 0.024 18.600 ;
    END
  END R0_data[376]
  PIN R0_data[377]
    DIRECTION OUTPUT ;
    USE SIGNAL ;
    SHAPE ABUTMENT ;
    PORT
      LAYER M4 ;
      RECT 0.000 18.624 0.024 18.648 ;
    END
  END R0_data[377]
  PIN R0_data[378]
    DIRECTION OUTPUT ;
    USE SIGNAL ;
    SHAPE ABUTMENT ;
    PORT
      LAYER M4 ;
      RECT 0.000 18.672 0.024 18.696 ;
    END
  END R0_data[378]
  PIN R0_data[379]
    DIRECTION OUTPUT ;
    USE SIGNAL ;
    SHAPE ABUTMENT ;
    PORT
      LAYER M4 ;
      RECT 0.000 18.720 0.024 18.744 ;
    END
  END R0_data[379]
  PIN R0_data[380]
    DIRECTION OUTPUT ;
    USE SIGNAL ;
    SHAPE ABUTMENT ;
    PORT
      LAYER M4 ;
      RECT 0.000 18.768 0.024 18.792 ;
    END
  END R0_data[380]
  PIN R0_data[381]
    DIRECTION OUTPUT ;
    USE SIGNAL ;
    SHAPE ABUTMENT ;
    PORT
      LAYER M4 ;
      RECT 0.000 18.816 0.024 18.840 ;
    END
  END R0_data[381]
  PIN R0_data[382]
    DIRECTION OUTPUT ;
    USE SIGNAL ;
    SHAPE ABUTMENT ;
    PORT
      LAYER M4 ;
      RECT 0.000 18.864 0.024 18.888 ;
    END
  END R0_data[382]
  PIN R0_data[383]
    DIRECTION OUTPUT ;
    USE SIGNAL ;
    SHAPE ABUTMENT ;
    PORT
      LAYER M4 ;
      RECT 0.000 18.912 0.024 18.936 ;
    END
  END R0_data[383]
  PIN R0_data[384]
    DIRECTION OUTPUT ;
    USE SIGNAL ;
    SHAPE ABUTMENT ;
    PORT
      LAYER M4 ;
      RECT 0.000 18.960 0.024 18.984 ;
    END
  END R0_data[384]
  PIN R0_data[385]
    DIRECTION OUTPUT ;
    USE SIGNAL ;
    SHAPE ABUTMENT ;
    PORT
      LAYER M4 ;
      RECT 0.000 19.008 0.024 19.032 ;
    END
  END R0_data[385]
  PIN R0_data[386]
    DIRECTION OUTPUT ;
    USE SIGNAL ;
    SHAPE ABUTMENT ;
    PORT
      LAYER M4 ;
      RECT 0.000 19.056 0.024 19.080 ;
    END
  END R0_data[386]
  PIN R0_data[387]
    DIRECTION OUTPUT ;
    USE SIGNAL ;
    SHAPE ABUTMENT ;
    PORT
      LAYER M4 ;
      RECT 0.000 19.104 0.024 19.128 ;
    END
  END R0_data[387]
  PIN R0_data[388]
    DIRECTION OUTPUT ;
    USE SIGNAL ;
    SHAPE ABUTMENT ;
    PORT
      LAYER M4 ;
      RECT 0.000 19.152 0.024 19.176 ;
    END
  END R0_data[388]
  PIN R0_data[389]
    DIRECTION OUTPUT ;
    USE SIGNAL ;
    SHAPE ABUTMENT ;
    PORT
      LAYER M4 ;
      RECT 0.000 19.200 0.024 19.224 ;
    END
  END R0_data[389]
  PIN R0_data[390]
    DIRECTION OUTPUT ;
    USE SIGNAL ;
    SHAPE ABUTMENT ;
    PORT
      LAYER M4 ;
      RECT 0.000 19.248 0.024 19.272 ;
    END
  END R0_data[390]
  PIN R0_data[391]
    DIRECTION OUTPUT ;
    USE SIGNAL ;
    SHAPE ABUTMENT ;
    PORT
      LAYER M4 ;
      RECT 0.000 19.296 0.024 19.320 ;
    END
  END R0_data[391]
  PIN R0_data[392]
    DIRECTION OUTPUT ;
    USE SIGNAL ;
    SHAPE ABUTMENT ;
    PORT
      LAYER M4 ;
      RECT 0.000 19.344 0.024 19.368 ;
    END
  END R0_data[392]
  PIN R0_data[393]
    DIRECTION OUTPUT ;
    USE SIGNAL ;
    SHAPE ABUTMENT ;
    PORT
      LAYER M4 ;
      RECT 0.000 19.392 0.024 19.416 ;
    END
  END R0_data[393]
  PIN R0_data[394]
    DIRECTION OUTPUT ;
    USE SIGNAL ;
    SHAPE ABUTMENT ;
    PORT
      LAYER M4 ;
      RECT 0.000 19.440 0.024 19.464 ;
    END
  END R0_data[394]
  PIN R0_data[395]
    DIRECTION OUTPUT ;
    USE SIGNAL ;
    SHAPE ABUTMENT ;
    PORT
      LAYER M4 ;
      RECT 0.000 19.488 0.024 19.512 ;
    END
  END R0_data[395]
  PIN R0_data[396]
    DIRECTION OUTPUT ;
    USE SIGNAL ;
    SHAPE ABUTMENT ;
    PORT
      LAYER M4 ;
      RECT 0.000 19.536 0.024 19.560 ;
    END
  END R0_data[396]
  PIN R0_data[397]
    DIRECTION OUTPUT ;
    USE SIGNAL ;
    SHAPE ABUTMENT ;
    PORT
      LAYER M4 ;
      RECT 0.000 19.584 0.024 19.608 ;
    END
  END R0_data[397]
  PIN R0_data[398]
    DIRECTION OUTPUT ;
    USE SIGNAL ;
    SHAPE ABUTMENT ;
    PORT
      LAYER M4 ;
      RECT 0.000 19.632 0.024 19.656 ;
    END
  END R0_data[398]
  PIN R0_data[399]
    DIRECTION OUTPUT ;
    USE SIGNAL ;
    SHAPE ABUTMENT ;
    PORT
      LAYER M4 ;
      RECT 0.000 19.680 0.024 19.704 ;
    END
  END R0_data[399]
  PIN R0_data[400]
    DIRECTION OUTPUT ;
    USE SIGNAL ;
    SHAPE ABUTMENT ;
    PORT
      LAYER M4 ;
      RECT 0.000 19.728 0.024 19.752 ;
    END
  END R0_data[400]
  PIN R0_data[401]
    DIRECTION OUTPUT ;
    USE SIGNAL ;
    SHAPE ABUTMENT ;
    PORT
      LAYER M4 ;
      RECT 0.000 19.776 0.024 19.800 ;
    END
  END R0_data[401]
  PIN R0_data[402]
    DIRECTION OUTPUT ;
    USE SIGNAL ;
    SHAPE ABUTMENT ;
    PORT
      LAYER M4 ;
      RECT 0.000 19.824 0.024 19.848 ;
    END
  END R0_data[402]
  PIN R0_data[403]
    DIRECTION OUTPUT ;
    USE SIGNAL ;
    SHAPE ABUTMENT ;
    PORT
      LAYER M4 ;
      RECT 0.000 19.872 0.024 19.896 ;
    END
  END R0_data[403]
  PIN R0_data[404]
    DIRECTION OUTPUT ;
    USE SIGNAL ;
    SHAPE ABUTMENT ;
    PORT
      LAYER M4 ;
      RECT 0.000 19.920 0.024 19.944 ;
    END
  END R0_data[404]
  PIN R0_data[405]
    DIRECTION OUTPUT ;
    USE SIGNAL ;
    SHAPE ABUTMENT ;
    PORT
      LAYER M4 ;
      RECT 0.000 19.968 0.024 19.992 ;
    END
  END R0_data[405]
  PIN R0_data[406]
    DIRECTION OUTPUT ;
    USE SIGNAL ;
    SHAPE ABUTMENT ;
    PORT
      LAYER M4 ;
      RECT 0.000 20.016 0.024 20.040 ;
    END
  END R0_data[406]
  PIN R0_data[407]
    DIRECTION OUTPUT ;
    USE SIGNAL ;
    SHAPE ABUTMENT ;
    PORT
      LAYER M4 ;
      RECT 0.000 20.064 0.024 20.088 ;
    END
  END R0_data[407]
  PIN R0_data[408]
    DIRECTION OUTPUT ;
    USE SIGNAL ;
    SHAPE ABUTMENT ;
    PORT
      LAYER M4 ;
      RECT 0.000 20.112 0.024 20.136 ;
    END
  END R0_data[408]
  PIN R0_data[409]
    DIRECTION OUTPUT ;
    USE SIGNAL ;
    SHAPE ABUTMENT ;
    PORT
      LAYER M4 ;
      RECT 0.000 20.160 0.024 20.184 ;
    END
  END R0_data[409]
  PIN R0_data[410]
    DIRECTION OUTPUT ;
    USE SIGNAL ;
    SHAPE ABUTMENT ;
    PORT
      LAYER M4 ;
      RECT 0.000 20.208 0.024 20.232 ;
    END
  END R0_data[410]
  PIN R0_data[411]
    DIRECTION OUTPUT ;
    USE SIGNAL ;
    SHAPE ABUTMENT ;
    PORT
      LAYER M4 ;
      RECT 0.000 20.256 0.024 20.280 ;
    END
  END R0_data[411]
  PIN R0_data[412]
    DIRECTION OUTPUT ;
    USE SIGNAL ;
    SHAPE ABUTMENT ;
    PORT
      LAYER M4 ;
      RECT 0.000 20.304 0.024 20.328 ;
    END
  END R0_data[412]
  PIN R0_data[413]
    DIRECTION OUTPUT ;
    USE SIGNAL ;
    SHAPE ABUTMENT ;
    PORT
      LAYER M4 ;
      RECT 0.000 20.352 0.024 20.376 ;
    END
  END R0_data[413]
  PIN R0_data[414]
    DIRECTION OUTPUT ;
    USE SIGNAL ;
    SHAPE ABUTMENT ;
    PORT
      LAYER M4 ;
      RECT 0.000 20.400 0.024 20.424 ;
    END
  END R0_data[414]
  PIN R0_data[415]
    DIRECTION OUTPUT ;
    USE SIGNAL ;
    SHAPE ABUTMENT ;
    PORT
      LAYER M4 ;
      RECT 0.000 20.448 0.024 20.472 ;
    END
  END R0_data[415]
  PIN R0_data[416]
    DIRECTION OUTPUT ;
    USE SIGNAL ;
    SHAPE ABUTMENT ;
    PORT
      LAYER M4 ;
      RECT 0.000 20.496 0.024 20.520 ;
    END
  END R0_data[416]
  PIN R0_data[417]
    DIRECTION OUTPUT ;
    USE SIGNAL ;
    SHAPE ABUTMENT ;
    PORT
      LAYER M4 ;
      RECT 0.000 20.544 0.024 20.568 ;
    END
  END R0_data[417]
  PIN R0_data[418]
    DIRECTION OUTPUT ;
    USE SIGNAL ;
    SHAPE ABUTMENT ;
    PORT
      LAYER M4 ;
      RECT 0.000 20.592 0.024 20.616 ;
    END
  END R0_data[418]
  PIN R0_data[419]
    DIRECTION OUTPUT ;
    USE SIGNAL ;
    SHAPE ABUTMENT ;
    PORT
      LAYER M4 ;
      RECT 0.000 20.640 0.024 20.664 ;
    END
  END R0_data[419]
  PIN R0_data[420]
    DIRECTION OUTPUT ;
    USE SIGNAL ;
    SHAPE ABUTMENT ;
    PORT
      LAYER M4 ;
      RECT 0.000 20.688 0.024 20.712 ;
    END
  END R0_data[420]
  PIN R0_data[421]
    DIRECTION OUTPUT ;
    USE SIGNAL ;
    SHAPE ABUTMENT ;
    PORT
      LAYER M4 ;
      RECT 0.000 20.736 0.024 20.760 ;
    END
  END R0_data[421]
  PIN R0_data[422]
    DIRECTION OUTPUT ;
    USE SIGNAL ;
    SHAPE ABUTMENT ;
    PORT
      LAYER M4 ;
      RECT 0.000 20.784 0.024 20.808 ;
    END
  END R0_data[422]
  PIN R0_data[423]
    DIRECTION OUTPUT ;
    USE SIGNAL ;
    SHAPE ABUTMENT ;
    PORT
      LAYER M4 ;
      RECT 0.000 20.832 0.024 20.856 ;
    END
  END R0_data[423]
  PIN R0_data[424]
    DIRECTION OUTPUT ;
    USE SIGNAL ;
    SHAPE ABUTMENT ;
    PORT
      LAYER M4 ;
      RECT 0.000 20.880 0.024 20.904 ;
    END
  END R0_data[424]
  PIN R0_data[425]
    DIRECTION OUTPUT ;
    USE SIGNAL ;
    SHAPE ABUTMENT ;
    PORT
      LAYER M4 ;
      RECT 0.000 20.928 0.024 20.952 ;
    END
  END R0_data[425]
  PIN R0_data[426]
    DIRECTION OUTPUT ;
    USE SIGNAL ;
    SHAPE ABUTMENT ;
    PORT
      LAYER M4 ;
      RECT 0.000 20.976 0.024 21.000 ;
    END
  END R0_data[426]
  PIN R0_data[427]
    DIRECTION OUTPUT ;
    USE SIGNAL ;
    SHAPE ABUTMENT ;
    PORT
      LAYER M4 ;
      RECT 0.000 21.024 0.024 21.048 ;
    END
  END R0_data[427]
  PIN R0_data[428]
    DIRECTION OUTPUT ;
    USE SIGNAL ;
    SHAPE ABUTMENT ;
    PORT
      LAYER M4 ;
      RECT 0.000 21.072 0.024 21.096 ;
    END
  END R0_data[428]
  PIN R0_data[429]
    DIRECTION OUTPUT ;
    USE SIGNAL ;
    SHAPE ABUTMENT ;
    PORT
      LAYER M4 ;
      RECT 0.000 21.120 0.024 21.144 ;
    END
  END R0_data[429]
  PIN R0_data[430]
    DIRECTION OUTPUT ;
    USE SIGNAL ;
    SHAPE ABUTMENT ;
    PORT
      LAYER M4 ;
      RECT 0.000 21.168 0.024 21.192 ;
    END
  END R0_data[430]
  PIN R0_data[431]
    DIRECTION OUTPUT ;
    USE SIGNAL ;
    SHAPE ABUTMENT ;
    PORT
      LAYER M4 ;
      RECT 0.000 21.216 0.024 21.240 ;
    END
  END R0_data[431]
  PIN R0_data[432]
    DIRECTION OUTPUT ;
    USE SIGNAL ;
    SHAPE ABUTMENT ;
    PORT
      LAYER M4 ;
      RECT 0.000 21.264 0.024 21.288 ;
    END
  END R0_data[432]
  PIN R0_data[433]
    DIRECTION OUTPUT ;
    USE SIGNAL ;
    SHAPE ABUTMENT ;
    PORT
      LAYER M4 ;
      RECT 0.000 21.312 0.024 21.336 ;
    END
  END R0_data[433]
  PIN R0_data[434]
    DIRECTION OUTPUT ;
    USE SIGNAL ;
    SHAPE ABUTMENT ;
    PORT
      LAYER M4 ;
      RECT 0.000 21.360 0.024 21.384 ;
    END
  END R0_data[434]
  PIN R0_data[435]
    DIRECTION OUTPUT ;
    USE SIGNAL ;
    SHAPE ABUTMENT ;
    PORT
      LAYER M4 ;
      RECT 0.000 21.408 0.024 21.432 ;
    END
  END R0_data[435]
  PIN R0_data[436]
    DIRECTION OUTPUT ;
    USE SIGNAL ;
    SHAPE ABUTMENT ;
    PORT
      LAYER M4 ;
      RECT 0.000 21.456 0.024 21.480 ;
    END
  END R0_data[436]
  PIN R0_data[437]
    DIRECTION OUTPUT ;
    USE SIGNAL ;
    SHAPE ABUTMENT ;
    PORT
      LAYER M4 ;
      RECT 0.000 21.504 0.024 21.528 ;
    END
  END R0_data[437]
  PIN R0_data[438]
    DIRECTION OUTPUT ;
    USE SIGNAL ;
    SHAPE ABUTMENT ;
    PORT
      LAYER M4 ;
      RECT 0.000 21.552 0.024 21.576 ;
    END
  END R0_data[438]
  PIN R0_data[439]
    DIRECTION OUTPUT ;
    USE SIGNAL ;
    SHAPE ABUTMENT ;
    PORT
      LAYER M4 ;
      RECT 0.000 21.600 0.024 21.624 ;
    END
  END R0_data[439]
  PIN R0_data[440]
    DIRECTION OUTPUT ;
    USE SIGNAL ;
    SHAPE ABUTMENT ;
    PORT
      LAYER M4 ;
      RECT 0.000 21.648 0.024 21.672 ;
    END
  END R0_data[440]
  PIN R0_data[441]
    DIRECTION OUTPUT ;
    USE SIGNAL ;
    SHAPE ABUTMENT ;
    PORT
      LAYER M4 ;
      RECT 0.000 21.696 0.024 21.720 ;
    END
  END R0_data[441]
  PIN R0_data[442]
    DIRECTION OUTPUT ;
    USE SIGNAL ;
    SHAPE ABUTMENT ;
    PORT
      LAYER M4 ;
      RECT 0.000 21.744 0.024 21.768 ;
    END
  END R0_data[442]
  PIN R0_data[443]
    DIRECTION OUTPUT ;
    USE SIGNAL ;
    SHAPE ABUTMENT ;
    PORT
      LAYER M4 ;
      RECT 0.000 21.792 0.024 21.816 ;
    END
  END R0_data[443]
  PIN R0_data[444]
    DIRECTION OUTPUT ;
    USE SIGNAL ;
    SHAPE ABUTMENT ;
    PORT
      LAYER M4 ;
      RECT 0.000 21.840 0.024 21.864 ;
    END
  END R0_data[444]
  PIN R0_data[445]
    DIRECTION OUTPUT ;
    USE SIGNAL ;
    SHAPE ABUTMENT ;
    PORT
      LAYER M4 ;
      RECT 0.000 21.888 0.024 21.912 ;
    END
  END R0_data[445]
  PIN R0_data[446]
    DIRECTION OUTPUT ;
    USE SIGNAL ;
    SHAPE ABUTMENT ;
    PORT
      LAYER M4 ;
      RECT 0.000 21.936 0.024 21.960 ;
    END
  END R0_data[446]
  PIN R0_data[447]
    DIRECTION OUTPUT ;
    USE SIGNAL ;
    SHAPE ABUTMENT ;
    PORT
      LAYER M4 ;
      RECT 0.000 21.984 0.024 22.008 ;
    END
  END R0_data[447]
  PIN R0_data[448]
    DIRECTION OUTPUT ;
    USE SIGNAL ;
    SHAPE ABUTMENT ;
    PORT
      LAYER M4 ;
      RECT 0.000 22.032 0.024 22.056 ;
    END
  END R0_data[448]
  PIN R0_data[449]
    DIRECTION OUTPUT ;
    USE SIGNAL ;
    SHAPE ABUTMENT ;
    PORT
      LAYER M4 ;
      RECT 0.000 22.080 0.024 22.104 ;
    END
  END R0_data[449]
  PIN R0_data[450]
    DIRECTION OUTPUT ;
    USE SIGNAL ;
    SHAPE ABUTMENT ;
    PORT
      LAYER M4 ;
      RECT 0.000 22.128 0.024 22.152 ;
    END
  END R0_data[450]
  PIN R0_data[451]
    DIRECTION OUTPUT ;
    USE SIGNAL ;
    SHAPE ABUTMENT ;
    PORT
      LAYER M4 ;
      RECT 0.000 22.176 0.024 22.200 ;
    END
  END R0_data[451]
  PIN R0_data[452]
    DIRECTION OUTPUT ;
    USE SIGNAL ;
    SHAPE ABUTMENT ;
    PORT
      LAYER M4 ;
      RECT 0.000 22.224 0.024 22.248 ;
    END
  END R0_data[452]
  PIN R0_data[453]
    DIRECTION OUTPUT ;
    USE SIGNAL ;
    SHAPE ABUTMENT ;
    PORT
      LAYER M4 ;
      RECT 0.000 22.272 0.024 22.296 ;
    END
  END R0_data[453]
  PIN R0_data[454]
    DIRECTION OUTPUT ;
    USE SIGNAL ;
    SHAPE ABUTMENT ;
    PORT
      LAYER M4 ;
      RECT 0.000 22.320 0.024 22.344 ;
    END
  END R0_data[454]
  PIN R0_data[455]
    DIRECTION OUTPUT ;
    USE SIGNAL ;
    SHAPE ABUTMENT ;
    PORT
      LAYER M4 ;
      RECT 0.000 22.368 0.024 22.392 ;
    END
  END R0_data[455]
  PIN R0_data[456]
    DIRECTION OUTPUT ;
    USE SIGNAL ;
    SHAPE ABUTMENT ;
    PORT
      LAYER M4 ;
      RECT 0.000 22.416 0.024 22.440 ;
    END
  END R0_data[456]
  PIN R0_data[457]
    DIRECTION OUTPUT ;
    USE SIGNAL ;
    SHAPE ABUTMENT ;
    PORT
      LAYER M4 ;
      RECT 0.000 22.464 0.024 22.488 ;
    END
  END R0_data[457]
  PIN R0_data[458]
    DIRECTION OUTPUT ;
    USE SIGNAL ;
    SHAPE ABUTMENT ;
    PORT
      LAYER M4 ;
      RECT 0.000 22.512 0.024 22.536 ;
    END
  END R0_data[458]
  PIN R0_data[459]
    DIRECTION OUTPUT ;
    USE SIGNAL ;
    SHAPE ABUTMENT ;
    PORT
      LAYER M4 ;
      RECT 0.000 22.560 0.024 22.584 ;
    END
  END R0_data[459]
  PIN R0_data[460]
    DIRECTION OUTPUT ;
    USE SIGNAL ;
    SHAPE ABUTMENT ;
    PORT
      LAYER M4 ;
      RECT 0.000 22.608 0.024 22.632 ;
    END
  END R0_data[460]
  PIN R0_data[461]
    DIRECTION OUTPUT ;
    USE SIGNAL ;
    SHAPE ABUTMENT ;
    PORT
      LAYER M4 ;
      RECT 0.000 22.656 0.024 22.680 ;
    END
  END R0_data[461]
  PIN R0_data[462]
    DIRECTION OUTPUT ;
    USE SIGNAL ;
    SHAPE ABUTMENT ;
    PORT
      LAYER M4 ;
      RECT 0.000 22.704 0.024 22.728 ;
    END
  END R0_data[462]
  PIN R0_data[463]
    DIRECTION OUTPUT ;
    USE SIGNAL ;
    SHAPE ABUTMENT ;
    PORT
      LAYER M4 ;
      RECT 0.000 22.752 0.024 22.776 ;
    END
  END R0_data[463]
  PIN R0_data[464]
    DIRECTION OUTPUT ;
    USE SIGNAL ;
    SHAPE ABUTMENT ;
    PORT
      LAYER M4 ;
      RECT 0.000 22.800 0.024 22.824 ;
    END
  END R0_data[464]
  PIN R0_data[465]
    DIRECTION OUTPUT ;
    USE SIGNAL ;
    SHAPE ABUTMENT ;
    PORT
      LAYER M4 ;
      RECT 0.000 22.848 0.024 22.872 ;
    END
  END R0_data[465]
  PIN R0_data[466]
    DIRECTION OUTPUT ;
    USE SIGNAL ;
    SHAPE ABUTMENT ;
    PORT
      LAYER M4 ;
      RECT 0.000 22.896 0.024 22.920 ;
    END
  END R0_data[466]
  PIN R0_data[467]
    DIRECTION OUTPUT ;
    USE SIGNAL ;
    SHAPE ABUTMENT ;
    PORT
      LAYER M4 ;
      RECT 0.000 22.944 0.024 22.968 ;
    END
  END R0_data[467]
  PIN R0_data[468]
    DIRECTION OUTPUT ;
    USE SIGNAL ;
    SHAPE ABUTMENT ;
    PORT
      LAYER M4 ;
      RECT 0.000 22.992 0.024 23.016 ;
    END
  END R0_data[468]
  PIN R0_data[469]
    DIRECTION OUTPUT ;
    USE SIGNAL ;
    SHAPE ABUTMENT ;
    PORT
      LAYER M4 ;
      RECT 0.000 23.040 0.024 23.064 ;
    END
  END R0_data[469]
  PIN R0_data[470]
    DIRECTION OUTPUT ;
    USE SIGNAL ;
    SHAPE ABUTMENT ;
    PORT
      LAYER M4 ;
      RECT 0.000 23.088 0.024 23.112 ;
    END
  END R0_data[470]
  PIN R0_data[471]
    DIRECTION OUTPUT ;
    USE SIGNAL ;
    SHAPE ABUTMENT ;
    PORT
      LAYER M4 ;
      RECT 0.000 23.136 0.024 23.160 ;
    END
  END R0_data[471]
  PIN R0_data[472]
    DIRECTION OUTPUT ;
    USE SIGNAL ;
    SHAPE ABUTMENT ;
    PORT
      LAYER M4 ;
      RECT 0.000 23.184 0.024 23.208 ;
    END
  END R0_data[472]
  PIN R0_data[473]
    DIRECTION OUTPUT ;
    USE SIGNAL ;
    SHAPE ABUTMENT ;
    PORT
      LAYER M4 ;
      RECT 0.000 23.232 0.024 23.256 ;
    END
  END R0_data[473]
  PIN R0_data[474]
    DIRECTION OUTPUT ;
    USE SIGNAL ;
    SHAPE ABUTMENT ;
    PORT
      LAYER M4 ;
      RECT 0.000 23.280 0.024 23.304 ;
    END
  END R0_data[474]
  PIN R0_data[475]
    DIRECTION OUTPUT ;
    USE SIGNAL ;
    SHAPE ABUTMENT ;
    PORT
      LAYER M4 ;
      RECT 0.000 23.328 0.024 23.352 ;
    END
  END R0_data[475]
  PIN R0_data[476]
    DIRECTION OUTPUT ;
    USE SIGNAL ;
    SHAPE ABUTMENT ;
    PORT
      LAYER M4 ;
      RECT 0.000 23.376 0.024 23.400 ;
    END
  END R0_data[476]
  PIN R0_data[477]
    DIRECTION OUTPUT ;
    USE SIGNAL ;
    SHAPE ABUTMENT ;
    PORT
      LAYER M4 ;
      RECT 0.000 23.424 0.024 23.448 ;
    END
  END R0_data[477]
  PIN R0_data[478]
    DIRECTION OUTPUT ;
    USE SIGNAL ;
    SHAPE ABUTMENT ;
    PORT
      LAYER M4 ;
      RECT 0.000 23.472 0.024 23.496 ;
    END
  END R0_data[478]
  PIN R0_data[479]
    DIRECTION OUTPUT ;
    USE SIGNAL ;
    SHAPE ABUTMENT ;
    PORT
      LAYER M4 ;
      RECT 0.000 23.520 0.024 23.544 ;
    END
  END R0_data[479]
  PIN R0_data[480]
    DIRECTION OUTPUT ;
    USE SIGNAL ;
    SHAPE ABUTMENT ;
    PORT
      LAYER M4 ;
      RECT 0.000 23.568 0.024 23.592 ;
    END
  END R0_data[480]
  PIN R0_data[481]
    DIRECTION OUTPUT ;
    USE SIGNAL ;
    SHAPE ABUTMENT ;
    PORT
      LAYER M4 ;
      RECT 0.000 23.616 0.024 23.640 ;
    END
  END R0_data[481]
  PIN R0_data[482]
    DIRECTION OUTPUT ;
    USE SIGNAL ;
    SHAPE ABUTMENT ;
    PORT
      LAYER M4 ;
      RECT 0.000 23.664 0.024 23.688 ;
    END
  END R0_data[482]
  PIN R0_data[483]
    DIRECTION OUTPUT ;
    USE SIGNAL ;
    SHAPE ABUTMENT ;
    PORT
      LAYER M4 ;
      RECT 0.000 23.712 0.024 23.736 ;
    END
  END R0_data[483]
  PIN R0_data[484]
    DIRECTION OUTPUT ;
    USE SIGNAL ;
    SHAPE ABUTMENT ;
    PORT
      LAYER M4 ;
      RECT 0.000 23.760 0.024 23.784 ;
    END
  END R0_data[484]
  PIN R0_data[485]
    DIRECTION OUTPUT ;
    USE SIGNAL ;
    SHAPE ABUTMENT ;
    PORT
      LAYER M4 ;
      RECT 0.000 23.808 0.024 23.832 ;
    END
  END R0_data[485]
  PIN R0_data[486]
    DIRECTION OUTPUT ;
    USE SIGNAL ;
    SHAPE ABUTMENT ;
    PORT
      LAYER M4 ;
      RECT 0.000 23.856 0.024 23.880 ;
    END
  END R0_data[486]
  PIN R0_data[487]
    DIRECTION OUTPUT ;
    USE SIGNAL ;
    SHAPE ABUTMENT ;
    PORT
      LAYER M4 ;
      RECT 0.000 23.904 0.024 23.928 ;
    END
  END R0_data[487]
  PIN R0_data[488]
    DIRECTION OUTPUT ;
    USE SIGNAL ;
    SHAPE ABUTMENT ;
    PORT
      LAYER M4 ;
      RECT 0.000 23.952 0.024 23.976 ;
    END
  END R0_data[488]
  PIN R0_data[489]
    DIRECTION OUTPUT ;
    USE SIGNAL ;
    SHAPE ABUTMENT ;
    PORT
      LAYER M4 ;
      RECT 0.000 24.000 0.024 24.024 ;
    END
  END R0_data[489]
  PIN R0_data[490]
    DIRECTION OUTPUT ;
    USE SIGNAL ;
    SHAPE ABUTMENT ;
    PORT
      LAYER M4 ;
      RECT 0.000 24.048 0.024 24.072 ;
    END
  END R0_data[490]
  PIN R0_data[491]
    DIRECTION OUTPUT ;
    USE SIGNAL ;
    SHAPE ABUTMENT ;
    PORT
      LAYER M4 ;
      RECT 0.000 24.096 0.024 24.120 ;
    END
  END R0_data[491]
  PIN R0_data[492]
    DIRECTION OUTPUT ;
    USE SIGNAL ;
    SHAPE ABUTMENT ;
    PORT
      LAYER M4 ;
      RECT 0.000 24.144 0.024 24.168 ;
    END
  END R0_data[492]
  PIN R0_data[493]
    DIRECTION OUTPUT ;
    USE SIGNAL ;
    SHAPE ABUTMENT ;
    PORT
      LAYER M4 ;
      RECT 0.000 24.192 0.024 24.216 ;
    END
  END R0_data[493]
  PIN R0_data[494]
    DIRECTION OUTPUT ;
    USE SIGNAL ;
    SHAPE ABUTMENT ;
    PORT
      LAYER M4 ;
      RECT 0.000 24.240 0.024 24.264 ;
    END
  END R0_data[494]
  PIN R0_data[495]
    DIRECTION OUTPUT ;
    USE SIGNAL ;
    SHAPE ABUTMENT ;
    PORT
      LAYER M4 ;
      RECT 0.000 24.288 0.024 24.312 ;
    END
  END R0_data[495]
  PIN R0_data[496]
    DIRECTION OUTPUT ;
    USE SIGNAL ;
    SHAPE ABUTMENT ;
    PORT
      LAYER M4 ;
      RECT 0.000 24.336 0.024 24.360 ;
    END
  END R0_data[496]
  PIN R0_data[497]
    DIRECTION OUTPUT ;
    USE SIGNAL ;
    SHAPE ABUTMENT ;
    PORT
      LAYER M4 ;
      RECT 0.000 24.384 0.024 24.408 ;
    END
  END R0_data[497]
  PIN R0_data[498]
    DIRECTION OUTPUT ;
    USE SIGNAL ;
    SHAPE ABUTMENT ;
    PORT
      LAYER M4 ;
      RECT 0.000 24.432 0.024 24.456 ;
    END
  END R0_data[498]
  PIN R0_data[499]
    DIRECTION OUTPUT ;
    USE SIGNAL ;
    SHAPE ABUTMENT ;
    PORT
      LAYER M4 ;
      RECT 0.000 24.480 0.024 24.504 ;
    END
  END R0_data[499]
  PIN R0_data[500]
    DIRECTION OUTPUT ;
    USE SIGNAL ;
    SHAPE ABUTMENT ;
    PORT
      LAYER M4 ;
      RECT 0.000 24.528 0.024 24.552 ;
    END
  END R0_data[500]
  PIN R0_data[501]
    DIRECTION OUTPUT ;
    USE SIGNAL ;
    SHAPE ABUTMENT ;
    PORT
      LAYER M4 ;
      RECT 0.000 24.576 0.024 24.600 ;
    END
  END R0_data[501]
  PIN R0_data[502]
    DIRECTION OUTPUT ;
    USE SIGNAL ;
    SHAPE ABUTMENT ;
    PORT
      LAYER M4 ;
      RECT 0.000 24.624 0.024 24.648 ;
    END
  END R0_data[502]
  PIN R0_data[503]
    DIRECTION OUTPUT ;
    USE SIGNAL ;
    SHAPE ABUTMENT ;
    PORT
      LAYER M4 ;
      RECT 0.000 24.672 0.024 24.696 ;
    END
  END R0_data[503]
  PIN R0_data[504]
    DIRECTION OUTPUT ;
    USE SIGNAL ;
    SHAPE ABUTMENT ;
    PORT
      LAYER M4 ;
      RECT 0.000 24.720 0.024 24.744 ;
    END
  END R0_data[504]
  PIN R0_data[505]
    DIRECTION OUTPUT ;
    USE SIGNAL ;
    SHAPE ABUTMENT ;
    PORT
      LAYER M4 ;
      RECT 0.000 24.768 0.024 24.792 ;
    END
  END R0_data[505]
  PIN R0_data[506]
    DIRECTION OUTPUT ;
    USE SIGNAL ;
    SHAPE ABUTMENT ;
    PORT
      LAYER M4 ;
      RECT 0.000 24.816 0.024 24.840 ;
    END
  END R0_data[506]
  PIN R0_data[507]
    DIRECTION OUTPUT ;
    USE SIGNAL ;
    SHAPE ABUTMENT ;
    PORT
      LAYER M4 ;
      RECT 0.000 24.864 0.024 24.888 ;
    END
  END R0_data[507]
  PIN R0_data[508]
    DIRECTION OUTPUT ;
    USE SIGNAL ;
    SHAPE ABUTMENT ;
    PORT
      LAYER M4 ;
      RECT 0.000 24.912 0.024 24.936 ;
    END
  END R0_data[508]
  PIN R0_data[509]
    DIRECTION OUTPUT ;
    USE SIGNAL ;
    SHAPE ABUTMENT ;
    PORT
      LAYER M4 ;
      RECT 0.000 24.960 0.024 24.984 ;
    END
  END R0_data[509]
  PIN R0_data[510]
    DIRECTION OUTPUT ;
    USE SIGNAL ;
    SHAPE ABUTMENT ;
    PORT
      LAYER M4 ;
      RECT 0.000 25.008 0.024 25.032 ;
    END
  END R0_data[510]
  PIN R0_data[511]
    DIRECTION OUTPUT ;
    USE SIGNAL ;
    SHAPE ABUTMENT ;
    PORT
      LAYER M4 ;
      RECT 0.000 25.056 0.024 25.080 ;
    END
  END R0_data[511]
  PIN R0_en
    DIRECTION INPUT ;
    USE SIGNAL ;
    SHAPE ABUTMENT ;
    PORT
      LAYER M4 ;
      RECT 0.000 25.104 0.024 25.128 ;
    END
  END R0_en
  PIN W0_addr[0]
    DIRECTION INPUT ;
    USE SIGNAL ;
    SHAPE ABUTMENT ;
    PORT
      LAYER M4 ;
      RECT 0.000 25.152 0.024 25.176 ;
    END
  END W0_addr[0]
  PIN W0_addr[1]
    DIRECTION INPUT ;
    USE SIGNAL ;
    SHAPE ABUTMENT ;
    PORT
      LAYER M4 ;
      RECT 0.000 25.200 0.024 25.224 ;
    END
  END W0_addr[1]
  PIN W0_addr[2]
    DIRECTION INPUT ;
    USE SIGNAL ;
    SHAPE ABUTMENT ;
    PORT
      LAYER M4 ;
      RECT 0.000 25.248 0.024 25.272 ;
    END
  END W0_addr[2]
  PIN W0_addr[3]
    DIRECTION INPUT ;
    USE SIGNAL ;
    SHAPE ABUTMENT ;
    PORT
      LAYER M4 ;
      RECT 0.000 25.296 0.024 25.320 ;
    END
  END W0_addr[3]
  PIN W0_addr[4]
    DIRECTION INPUT ;
    USE SIGNAL ;
    SHAPE ABUTMENT ;
    PORT
      LAYER M4 ;
      RECT 0.000 25.344 0.024 25.368 ;
    END
  END W0_addr[4]
  PIN W0_addr[5]
    DIRECTION INPUT ;
    USE SIGNAL ;
    SHAPE ABUTMENT ;
    PORT
      LAYER M4 ;
      RECT 0.000 25.392 0.024 25.416 ;
    END
  END W0_addr[5]
  PIN W0_addr[6]
    DIRECTION INPUT ;
    USE SIGNAL ;
    SHAPE ABUTMENT ;
    PORT
      LAYER M4 ;
      RECT 0.000 25.440 0.024 25.464 ;
    END
  END W0_addr[6]
  PIN W0_addr[7]
    DIRECTION INPUT ;
    USE SIGNAL ;
    SHAPE ABUTMENT ;
    PORT
      LAYER M4 ;
      RECT 0.000 25.488 0.024 25.512 ;
    END
  END W0_addr[7]
  PIN W0_addr[8]
    DIRECTION INPUT ;
    USE SIGNAL ;
    SHAPE ABUTMENT ;
    PORT
      LAYER M4 ;
      RECT 0.000 25.536 0.024 25.560 ;
    END
  END W0_addr[8]
  PIN W0_clk
    DIRECTION INPUT ;
    USE SIGNAL ;
    SHAPE ABUTMENT ;
    PORT
      LAYER M4 ;
      RECT 0.000 25.584 0.024 25.608 ;
    END
  END W0_clk
  PIN W0_data[0]
    DIRECTION INPUT ;
    USE SIGNAL ;
    SHAPE ABUTMENT ;
    PORT
      LAYER M4 ;
      RECT 0.000 25.632 0.024 25.656 ;
    END
  END W0_data[0]
  PIN W0_data[1]
    DIRECTION INPUT ;
    USE SIGNAL ;
    SHAPE ABUTMENT ;
    PORT
      LAYER M4 ;
      RECT 0.000 25.680 0.024 25.704 ;
    END
  END W0_data[1]
  PIN W0_data[2]
    DIRECTION INPUT ;
    USE SIGNAL ;
    SHAPE ABUTMENT ;
    PORT
      LAYER M4 ;
      RECT 0.000 25.728 0.024 25.752 ;
    END
  END W0_data[2]
  PIN W0_data[3]
    DIRECTION INPUT ;
    USE SIGNAL ;
    SHAPE ABUTMENT ;
    PORT
      LAYER M4 ;
      RECT 0.000 25.776 0.024 25.800 ;
    END
  END W0_data[3]
  PIN W0_data[4]
    DIRECTION INPUT ;
    USE SIGNAL ;
    SHAPE ABUTMENT ;
    PORT
      LAYER M4 ;
      RECT 0.000 25.824 0.024 25.848 ;
    END
  END W0_data[4]
  PIN W0_data[5]
    DIRECTION INPUT ;
    USE SIGNAL ;
    SHAPE ABUTMENT ;
    PORT
      LAYER M4 ;
      RECT 0.000 25.872 0.024 25.896 ;
    END
  END W0_data[5]
  PIN W0_data[6]
    DIRECTION INPUT ;
    USE SIGNAL ;
    SHAPE ABUTMENT ;
    PORT
      LAYER M4 ;
      RECT 0.000 25.920 0.024 25.944 ;
    END
  END W0_data[6]
  PIN W0_data[7]
    DIRECTION INPUT ;
    USE SIGNAL ;
    SHAPE ABUTMENT ;
    PORT
      LAYER M4 ;
      RECT 0.000 25.968 0.024 25.992 ;
    END
  END W0_data[7]
  PIN W0_data[8]
    DIRECTION INPUT ;
    USE SIGNAL ;
    SHAPE ABUTMENT ;
    PORT
      LAYER M4 ;
      RECT 0.000 26.016 0.024 26.040 ;
    END
  END W0_data[8]
  PIN W0_data[9]
    DIRECTION INPUT ;
    USE SIGNAL ;
    SHAPE ABUTMENT ;
    PORT
      LAYER M4 ;
      RECT 0.000 26.064 0.024 26.088 ;
    END
  END W0_data[9]
  PIN W0_data[10]
    DIRECTION INPUT ;
    USE SIGNAL ;
    SHAPE ABUTMENT ;
    PORT
      LAYER M4 ;
      RECT 0.000 26.112 0.024 26.136 ;
    END
  END W0_data[10]
  PIN W0_data[11]
    DIRECTION INPUT ;
    USE SIGNAL ;
    SHAPE ABUTMENT ;
    PORT
      LAYER M4 ;
      RECT 0.000 26.160 0.024 26.184 ;
    END
  END W0_data[11]
  PIN W0_data[12]
    DIRECTION INPUT ;
    USE SIGNAL ;
    SHAPE ABUTMENT ;
    PORT
      LAYER M4 ;
      RECT 0.000 26.208 0.024 26.232 ;
    END
  END W0_data[12]
  PIN W0_data[13]
    DIRECTION INPUT ;
    USE SIGNAL ;
    SHAPE ABUTMENT ;
    PORT
      LAYER M4 ;
      RECT 0.000 26.256 0.024 26.280 ;
    END
  END W0_data[13]
  PIN W0_data[14]
    DIRECTION INPUT ;
    USE SIGNAL ;
    SHAPE ABUTMENT ;
    PORT
      LAYER M4 ;
      RECT 0.000 26.304 0.024 26.328 ;
    END
  END W0_data[14]
  PIN W0_data[15]
    DIRECTION INPUT ;
    USE SIGNAL ;
    SHAPE ABUTMENT ;
    PORT
      LAYER M4 ;
      RECT 0.000 26.352 0.024 26.376 ;
    END
  END W0_data[15]
  PIN W0_data[16]
    DIRECTION INPUT ;
    USE SIGNAL ;
    SHAPE ABUTMENT ;
    PORT
      LAYER M4 ;
      RECT 0.000 26.400 0.024 26.424 ;
    END
  END W0_data[16]
  PIN W0_data[17]
    DIRECTION INPUT ;
    USE SIGNAL ;
    SHAPE ABUTMENT ;
    PORT
      LAYER M4 ;
      RECT 0.000 26.448 0.024 26.472 ;
    END
  END W0_data[17]
  PIN W0_data[18]
    DIRECTION INPUT ;
    USE SIGNAL ;
    SHAPE ABUTMENT ;
    PORT
      LAYER M4 ;
      RECT 0.000 26.496 0.024 26.520 ;
    END
  END W0_data[18]
  PIN W0_data[19]
    DIRECTION INPUT ;
    USE SIGNAL ;
    SHAPE ABUTMENT ;
    PORT
      LAYER M4 ;
      RECT 0.000 26.544 0.024 26.568 ;
    END
  END W0_data[19]
  PIN W0_data[20]
    DIRECTION INPUT ;
    USE SIGNAL ;
    SHAPE ABUTMENT ;
    PORT
      LAYER M4 ;
      RECT 0.000 26.592 0.024 26.616 ;
    END
  END W0_data[20]
  PIN W0_data[21]
    DIRECTION INPUT ;
    USE SIGNAL ;
    SHAPE ABUTMENT ;
    PORT
      LAYER M4 ;
      RECT 0.000 26.640 0.024 26.664 ;
    END
  END W0_data[21]
  PIN W0_data[22]
    DIRECTION INPUT ;
    USE SIGNAL ;
    SHAPE ABUTMENT ;
    PORT
      LAYER M4 ;
      RECT 0.000 26.688 0.024 26.712 ;
    END
  END W0_data[22]
  PIN W0_data[23]
    DIRECTION INPUT ;
    USE SIGNAL ;
    SHAPE ABUTMENT ;
    PORT
      LAYER M4 ;
      RECT 0.000 26.736 0.024 26.760 ;
    END
  END W0_data[23]
  PIN W0_data[24]
    DIRECTION INPUT ;
    USE SIGNAL ;
    SHAPE ABUTMENT ;
    PORT
      LAYER M4 ;
      RECT 0.000 26.784 0.024 26.808 ;
    END
  END W0_data[24]
  PIN W0_data[25]
    DIRECTION INPUT ;
    USE SIGNAL ;
    SHAPE ABUTMENT ;
    PORT
      LAYER M4 ;
      RECT 0.000 26.832 0.024 26.856 ;
    END
  END W0_data[25]
  PIN W0_data[26]
    DIRECTION INPUT ;
    USE SIGNAL ;
    SHAPE ABUTMENT ;
    PORT
      LAYER M4 ;
      RECT 0.000 26.880 0.024 26.904 ;
    END
  END W0_data[26]
  PIN W0_data[27]
    DIRECTION INPUT ;
    USE SIGNAL ;
    SHAPE ABUTMENT ;
    PORT
      LAYER M4 ;
      RECT 0.000 26.928 0.024 26.952 ;
    END
  END W0_data[27]
  PIN W0_data[28]
    DIRECTION INPUT ;
    USE SIGNAL ;
    SHAPE ABUTMENT ;
    PORT
      LAYER M4 ;
      RECT 0.000 26.976 0.024 27.000 ;
    END
  END W0_data[28]
  PIN W0_data[29]
    DIRECTION INPUT ;
    USE SIGNAL ;
    SHAPE ABUTMENT ;
    PORT
      LAYER M4 ;
      RECT 0.000 27.024 0.024 27.048 ;
    END
  END W0_data[29]
  PIN W0_data[30]
    DIRECTION INPUT ;
    USE SIGNAL ;
    SHAPE ABUTMENT ;
    PORT
      LAYER M4 ;
      RECT 0.000 27.072 0.024 27.096 ;
    END
  END W0_data[30]
  PIN W0_data[31]
    DIRECTION INPUT ;
    USE SIGNAL ;
    SHAPE ABUTMENT ;
    PORT
      LAYER M4 ;
      RECT 0.000 27.120 0.024 27.144 ;
    END
  END W0_data[31]
  PIN W0_data[32]
    DIRECTION INPUT ;
    USE SIGNAL ;
    SHAPE ABUTMENT ;
    PORT
      LAYER M4 ;
      RECT 0.000 27.168 0.024 27.192 ;
    END
  END W0_data[32]
  PIN W0_data[33]
    DIRECTION INPUT ;
    USE SIGNAL ;
    SHAPE ABUTMENT ;
    PORT
      LAYER M4 ;
      RECT 0.000 27.216 0.024 27.240 ;
    END
  END W0_data[33]
  PIN W0_data[34]
    DIRECTION INPUT ;
    USE SIGNAL ;
    SHAPE ABUTMENT ;
    PORT
      LAYER M4 ;
      RECT 0.000 27.264 0.024 27.288 ;
    END
  END W0_data[34]
  PIN W0_data[35]
    DIRECTION INPUT ;
    USE SIGNAL ;
    SHAPE ABUTMENT ;
    PORT
      LAYER M4 ;
      RECT 0.000 27.312 0.024 27.336 ;
    END
  END W0_data[35]
  PIN W0_data[36]
    DIRECTION INPUT ;
    USE SIGNAL ;
    SHAPE ABUTMENT ;
    PORT
      LAYER M4 ;
      RECT 0.000 27.360 0.024 27.384 ;
    END
  END W0_data[36]
  PIN W0_data[37]
    DIRECTION INPUT ;
    USE SIGNAL ;
    SHAPE ABUTMENT ;
    PORT
      LAYER M4 ;
      RECT 0.000 27.408 0.024 27.432 ;
    END
  END W0_data[37]
  PIN W0_data[38]
    DIRECTION INPUT ;
    USE SIGNAL ;
    SHAPE ABUTMENT ;
    PORT
      LAYER M4 ;
      RECT 0.000 27.456 0.024 27.480 ;
    END
  END W0_data[38]
  PIN W0_data[39]
    DIRECTION INPUT ;
    USE SIGNAL ;
    SHAPE ABUTMENT ;
    PORT
      LAYER M4 ;
      RECT 0.000 27.504 0.024 27.528 ;
    END
  END W0_data[39]
  PIN W0_data[40]
    DIRECTION INPUT ;
    USE SIGNAL ;
    SHAPE ABUTMENT ;
    PORT
      LAYER M4 ;
      RECT 0.000 27.552 0.024 27.576 ;
    END
  END W0_data[40]
  PIN W0_data[41]
    DIRECTION INPUT ;
    USE SIGNAL ;
    SHAPE ABUTMENT ;
    PORT
      LAYER M4 ;
      RECT 0.000 27.600 0.024 27.624 ;
    END
  END W0_data[41]
  PIN W0_data[42]
    DIRECTION INPUT ;
    USE SIGNAL ;
    SHAPE ABUTMENT ;
    PORT
      LAYER M4 ;
      RECT 0.000 27.648 0.024 27.672 ;
    END
  END W0_data[42]
  PIN W0_data[43]
    DIRECTION INPUT ;
    USE SIGNAL ;
    SHAPE ABUTMENT ;
    PORT
      LAYER M4 ;
      RECT 0.000 27.696 0.024 27.720 ;
    END
  END W0_data[43]
  PIN W0_data[44]
    DIRECTION INPUT ;
    USE SIGNAL ;
    SHAPE ABUTMENT ;
    PORT
      LAYER M4 ;
      RECT 0.000 27.744 0.024 27.768 ;
    END
  END W0_data[44]
  PIN W0_data[45]
    DIRECTION INPUT ;
    USE SIGNAL ;
    SHAPE ABUTMENT ;
    PORT
      LAYER M4 ;
      RECT 0.000 27.792 0.024 27.816 ;
    END
  END W0_data[45]
  PIN W0_data[46]
    DIRECTION INPUT ;
    USE SIGNAL ;
    SHAPE ABUTMENT ;
    PORT
      LAYER M4 ;
      RECT 0.000 27.840 0.024 27.864 ;
    END
  END W0_data[46]
  PIN W0_data[47]
    DIRECTION INPUT ;
    USE SIGNAL ;
    SHAPE ABUTMENT ;
    PORT
      LAYER M4 ;
      RECT 0.000 27.888 0.024 27.912 ;
    END
  END W0_data[47]
  PIN W0_data[48]
    DIRECTION INPUT ;
    USE SIGNAL ;
    SHAPE ABUTMENT ;
    PORT
      LAYER M4 ;
      RECT 0.000 27.936 0.024 27.960 ;
    END
  END W0_data[48]
  PIN W0_data[49]
    DIRECTION INPUT ;
    USE SIGNAL ;
    SHAPE ABUTMENT ;
    PORT
      LAYER M4 ;
      RECT 0.000 27.984 0.024 28.008 ;
    END
  END W0_data[49]
  PIN W0_data[50]
    DIRECTION INPUT ;
    USE SIGNAL ;
    SHAPE ABUTMENT ;
    PORT
      LAYER M4 ;
      RECT 0.000 28.032 0.024 28.056 ;
    END
  END W0_data[50]
  PIN W0_data[51]
    DIRECTION INPUT ;
    USE SIGNAL ;
    SHAPE ABUTMENT ;
    PORT
      LAYER M4 ;
      RECT 0.000 28.080 0.024 28.104 ;
    END
  END W0_data[51]
  PIN W0_data[52]
    DIRECTION INPUT ;
    USE SIGNAL ;
    SHAPE ABUTMENT ;
    PORT
      LAYER M4 ;
      RECT 0.000 28.128 0.024 28.152 ;
    END
  END W0_data[52]
  PIN W0_data[53]
    DIRECTION INPUT ;
    USE SIGNAL ;
    SHAPE ABUTMENT ;
    PORT
      LAYER M4 ;
      RECT 0.000 28.176 0.024 28.200 ;
    END
  END W0_data[53]
  PIN W0_data[54]
    DIRECTION INPUT ;
    USE SIGNAL ;
    SHAPE ABUTMENT ;
    PORT
      LAYER M4 ;
      RECT 0.000 28.224 0.024 28.248 ;
    END
  END W0_data[54]
  PIN W0_data[55]
    DIRECTION INPUT ;
    USE SIGNAL ;
    SHAPE ABUTMENT ;
    PORT
      LAYER M4 ;
      RECT 0.000 28.272 0.024 28.296 ;
    END
  END W0_data[55]
  PIN W0_data[56]
    DIRECTION INPUT ;
    USE SIGNAL ;
    SHAPE ABUTMENT ;
    PORT
      LAYER M4 ;
      RECT 0.000 28.320 0.024 28.344 ;
    END
  END W0_data[56]
  PIN W0_data[57]
    DIRECTION INPUT ;
    USE SIGNAL ;
    SHAPE ABUTMENT ;
    PORT
      LAYER M4 ;
      RECT 0.000 28.368 0.024 28.392 ;
    END
  END W0_data[57]
  PIN W0_data[58]
    DIRECTION INPUT ;
    USE SIGNAL ;
    SHAPE ABUTMENT ;
    PORT
      LAYER M4 ;
      RECT 0.000 28.416 0.024 28.440 ;
    END
  END W0_data[58]
  PIN W0_data[59]
    DIRECTION INPUT ;
    USE SIGNAL ;
    SHAPE ABUTMENT ;
    PORT
      LAYER M4 ;
      RECT 0.000 28.464 0.024 28.488 ;
    END
  END W0_data[59]
  PIN W0_data[60]
    DIRECTION INPUT ;
    USE SIGNAL ;
    SHAPE ABUTMENT ;
    PORT
      LAYER M4 ;
      RECT 0.000 28.512 0.024 28.536 ;
    END
  END W0_data[60]
  PIN W0_data[61]
    DIRECTION INPUT ;
    USE SIGNAL ;
    SHAPE ABUTMENT ;
    PORT
      LAYER M4 ;
      RECT 0.000 28.560 0.024 28.584 ;
    END
  END W0_data[61]
  PIN W0_data[62]
    DIRECTION INPUT ;
    USE SIGNAL ;
    SHAPE ABUTMENT ;
    PORT
      LAYER M4 ;
      RECT 0.000 28.608 0.024 28.632 ;
    END
  END W0_data[62]
  PIN W0_data[63]
    DIRECTION INPUT ;
    USE SIGNAL ;
    SHAPE ABUTMENT ;
    PORT
      LAYER M4 ;
      RECT 0.000 28.656 0.024 28.680 ;
    END
  END W0_data[63]
  PIN W0_data[64]
    DIRECTION INPUT ;
    USE SIGNAL ;
    SHAPE ABUTMENT ;
    PORT
      LAYER M4 ;
      RECT 0.000 28.704 0.024 28.728 ;
    END
  END W0_data[64]
  PIN W0_data[65]
    DIRECTION INPUT ;
    USE SIGNAL ;
    SHAPE ABUTMENT ;
    PORT
      LAYER M4 ;
      RECT 0.000 28.752 0.024 28.776 ;
    END
  END W0_data[65]
  PIN W0_data[66]
    DIRECTION INPUT ;
    USE SIGNAL ;
    SHAPE ABUTMENT ;
    PORT
      LAYER M4 ;
      RECT 0.000 28.800 0.024 28.824 ;
    END
  END W0_data[66]
  PIN W0_data[67]
    DIRECTION INPUT ;
    USE SIGNAL ;
    SHAPE ABUTMENT ;
    PORT
      LAYER M4 ;
      RECT 0.000 28.848 0.024 28.872 ;
    END
  END W0_data[67]
  PIN W0_data[68]
    DIRECTION INPUT ;
    USE SIGNAL ;
    SHAPE ABUTMENT ;
    PORT
      LAYER M4 ;
      RECT 0.000 28.896 0.024 28.920 ;
    END
  END W0_data[68]
  PIN W0_data[69]
    DIRECTION INPUT ;
    USE SIGNAL ;
    SHAPE ABUTMENT ;
    PORT
      LAYER M4 ;
      RECT 0.000 28.944 0.024 28.968 ;
    END
  END W0_data[69]
  PIN W0_data[70]
    DIRECTION INPUT ;
    USE SIGNAL ;
    SHAPE ABUTMENT ;
    PORT
      LAYER M4 ;
      RECT 0.000 28.992 0.024 29.016 ;
    END
  END W0_data[70]
  PIN W0_data[71]
    DIRECTION INPUT ;
    USE SIGNAL ;
    SHAPE ABUTMENT ;
    PORT
      LAYER M4 ;
      RECT 0.000 29.040 0.024 29.064 ;
    END
  END W0_data[71]
  PIN W0_data[72]
    DIRECTION INPUT ;
    USE SIGNAL ;
    SHAPE ABUTMENT ;
    PORT
      LAYER M4 ;
      RECT 0.000 29.088 0.024 29.112 ;
    END
  END W0_data[72]
  PIN W0_data[73]
    DIRECTION INPUT ;
    USE SIGNAL ;
    SHAPE ABUTMENT ;
    PORT
      LAYER M4 ;
      RECT 0.000 29.136 0.024 29.160 ;
    END
  END W0_data[73]
  PIN W0_data[74]
    DIRECTION INPUT ;
    USE SIGNAL ;
    SHAPE ABUTMENT ;
    PORT
      LAYER M4 ;
      RECT 0.000 29.184 0.024 29.208 ;
    END
  END W0_data[74]
  PIN W0_data[75]
    DIRECTION INPUT ;
    USE SIGNAL ;
    SHAPE ABUTMENT ;
    PORT
      LAYER M4 ;
      RECT 0.000 29.232 0.024 29.256 ;
    END
  END W0_data[75]
  PIN W0_data[76]
    DIRECTION INPUT ;
    USE SIGNAL ;
    SHAPE ABUTMENT ;
    PORT
      LAYER M4 ;
      RECT 0.000 29.280 0.024 29.304 ;
    END
  END W0_data[76]
  PIN W0_data[77]
    DIRECTION INPUT ;
    USE SIGNAL ;
    SHAPE ABUTMENT ;
    PORT
      LAYER M4 ;
      RECT 0.000 29.328 0.024 29.352 ;
    END
  END W0_data[77]
  PIN W0_data[78]
    DIRECTION INPUT ;
    USE SIGNAL ;
    SHAPE ABUTMENT ;
    PORT
      LAYER M4 ;
      RECT 0.000 29.376 0.024 29.400 ;
    END
  END W0_data[78]
  PIN W0_data[79]
    DIRECTION INPUT ;
    USE SIGNAL ;
    SHAPE ABUTMENT ;
    PORT
      LAYER M4 ;
      RECT 0.000 29.424 0.024 29.448 ;
    END
  END W0_data[79]
  PIN W0_data[80]
    DIRECTION INPUT ;
    USE SIGNAL ;
    SHAPE ABUTMENT ;
    PORT
      LAYER M4 ;
      RECT 0.000 29.472 0.024 29.496 ;
    END
  END W0_data[80]
  PIN W0_data[81]
    DIRECTION INPUT ;
    USE SIGNAL ;
    SHAPE ABUTMENT ;
    PORT
      LAYER M4 ;
      RECT 0.000 29.520 0.024 29.544 ;
    END
  END W0_data[81]
  PIN W0_data[82]
    DIRECTION INPUT ;
    USE SIGNAL ;
    SHAPE ABUTMENT ;
    PORT
      LAYER M4 ;
      RECT 0.000 29.568 0.024 29.592 ;
    END
  END W0_data[82]
  PIN W0_data[83]
    DIRECTION INPUT ;
    USE SIGNAL ;
    SHAPE ABUTMENT ;
    PORT
      LAYER M4 ;
      RECT 0.000 29.616 0.024 29.640 ;
    END
  END W0_data[83]
  PIN W0_data[84]
    DIRECTION INPUT ;
    USE SIGNAL ;
    SHAPE ABUTMENT ;
    PORT
      LAYER M4 ;
      RECT 0.000 29.664 0.024 29.688 ;
    END
  END W0_data[84]
  PIN W0_data[85]
    DIRECTION INPUT ;
    USE SIGNAL ;
    SHAPE ABUTMENT ;
    PORT
      LAYER M4 ;
      RECT 0.000 29.712 0.024 29.736 ;
    END
  END W0_data[85]
  PIN W0_data[86]
    DIRECTION INPUT ;
    USE SIGNAL ;
    SHAPE ABUTMENT ;
    PORT
      LAYER M4 ;
      RECT 0.000 29.760 0.024 29.784 ;
    END
  END W0_data[86]
  PIN W0_data[87]
    DIRECTION INPUT ;
    USE SIGNAL ;
    SHAPE ABUTMENT ;
    PORT
      LAYER M4 ;
      RECT 0.000 29.808 0.024 29.832 ;
    END
  END W0_data[87]
  PIN W0_data[88]
    DIRECTION INPUT ;
    USE SIGNAL ;
    SHAPE ABUTMENT ;
    PORT
      LAYER M4 ;
      RECT 0.000 29.856 0.024 29.880 ;
    END
  END W0_data[88]
  PIN W0_data[89]
    DIRECTION INPUT ;
    USE SIGNAL ;
    SHAPE ABUTMENT ;
    PORT
      LAYER M4 ;
      RECT 0.000 29.904 0.024 29.928 ;
    END
  END W0_data[89]
  PIN W0_data[90]
    DIRECTION INPUT ;
    USE SIGNAL ;
    SHAPE ABUTMENT ;
    PORT
      LAYER M4 ;
      RECT 0.000 29.952 0.024 29.976 ;
    END
  END W0_data[90]
  PIN W0_data[91]
    DIRECTION INPUT ;
    USE SIGNAL ;
    SHAPE ABUTMENT ;
    PORT
      LAYER M4 ;
      RECT 0.000 30.000 0.024 30.024 ;
    END
  END W0_data[91]
  PIN W0_data[92]
    DIRECTION INPUT ;
    USE SIGNAL ;
    SHAPE ABUTMENT ;
    PORT
      LAYER M4 ;
      RECT 0.000 30.048 0.024 30.072 ;
    END
  END W0_data[92]
  PIN W0_data[93]
    DIRECTION INPUT ;
    USE SIGNAL ;
    SHAPE ABUTMENT ;
    PORT
      LAYER M4 ;
      RECT 0.000 30.096 0.024 30.120 ;
    END
  END W0_data[93]
  PIN W0_data[94]
    DIRECTION INPUT ;
    USE SIGNAL ;
    SHAPE ABUTMENT ;
    PORT
      LAYER M4 ;
      RECT 0.000 30.144 0.024 30.168 ;
    END
  END W0_data[94]
  PIN W0_data[95]
    DIRECTION INPUT ;
    USE SIGNAL ;
    SHAPE ABUTMENT ;
    PORT
      LAYER M4 ;
      RECT 0.000 30.192 0.024 30.216 ;
    END
  END W0_data[95]
  PIN W0_data[96]
    DIRECTION INPUT ;
    USE SIGNAL ;
    SHAPE ABUTMENT ;
    PORT
      LAYER M4 ;
      RECT 0.000 30.240 0.024 30.264 ;
    END
  END W0_data[96]
  PIN W0_data[97]
    DIRECTION INPUT ;
    USE SIGNAL ;
    SHAPE ABUTMENT ;
    PORT
      LAYER M4 ;
      RECT 0.000 30.288 0.024 30.312 ;
    END
  END W0_data[97]
  PIN W0_data[98]
    DIRECTION INPUT ;
    USE SIGNAL ;
    SHAPE ABUTMENT ;
    PORT
      LAYER M4 ;
      RECT 0.000 30.336 0.024 30.360 ;
    END
  END W0_data[98]
  PIN W0_data[99]
    DIRECTION INPUT ;
    USE SIGNAL ;
    SHAPE ABUTMENT ;
    PORT
      LAYER M4 ;
      RECT 0.000 30.384 0.024 30.408 ;
    END
  END W0_data[99]
  PIN W0_data[100]
    DIRECTION INPUT ;
    USE SIGNAL ;
    SHAPE ABUTMENT ;
    PORT
      LAYER M4 ;
      RECT 0.000 30.432 0.024 30.456 ;
    END
  END W0_data[100]
  PIN W0_data[101]
    DIRECTION INPUT ;
    USE SIGNAL ;
    SHAPE ABUTMENT ;
    PORT
      LAYER M4 ;
      RECT 0.000 30.480 0.024 30.504 ;
    END
  END W0_data[101]
  PIN W0_data[102]
    DIRECTION INPUT ;
    USE SIGNAL ;
    SHAPE ABUTMENT ;
    PORT
      LAYER M4 ;
      RECT 0.000 30.528 0.024 30.552 ;
    END
  END W0_data[102]
  PIN W0_data[103]
    DIRECTION INPUT ;
    USE SIGNAL ;
    SHAPE ABUTMENT ;
    PORT
      LAYER M4 ;
      RECT 0.000 30.576 0.024 30.600 ;
    END
  END W0_data[103]
  PIN W0_data[104]
    DIRECTION INPUT ;
    USE SIGNAL ;
    SHAPE ABUTMENT ;
    PORT
      LAYER M4 ;
      RECT 0.000 30.624 0.024 30.648 ;
    END
  END W0_data[104]
  PIN W0_data[105]
    DIRECTION INPUT ;
    USE SIGNAL ;
    SHAPE ABUTMENT ;
    PORT
      LAYER M4 ;
      RECT 0.000 30.672 0.024 30.696 ;
    END
  END W0_data[105]
  PIN W0_data[106]
    DIRECTION INPUT ;
    USE SIGNAL ;
    SHAPE ABUTMENT ;
    PORT
      LAYER M4 ;
      RECT 0.000 30.720 0.024 30.744 ;
    END
  END W0_data[106]
  PIN W0_data[107]
    DIRECTION INPUT ;
    USE SIGNAL ;
    SHAPE ABUTMENT ;
    PORT
      LAYER M4 ;
      RECT 0.000 30.768 0.024 30.792 ;
    END
  END W0_data[107]
  PIN W0_data[108]
    DIRECTION INPUT ;
    USE SIGNAL ;
    SHAPE ABUTMENT ;
    PORT
      LAYER M4 ;
      RECT 0.000 30.816 0.024 30.840 ;
    END
  END W0_data[108]
  PIN W0_data[109]
    DIRECTION INPUT ;
    USE SIGNAL ;
    SHAPE ABUTMENT ;
    PORT
      LAYER M4 ;
      RECT 0.000 30.864 0.024 30.888 ;
    END
  END W0_data[109]
  PIN W0_data[110]
    DIRECTION INPUT ;
    USE SIGNAL ;
    SHAPE ABUTMENT ;
    PORT
      LAYER M4 ;
      RECT 0.000 30.912 0.024 30.936 ;
    END
  END W0_data[110]
  PIN W0_data[111]
    DIRECTION INPUT ;
    USE SIGNAL ;
    SHAPE ABUTMENT ;
    PORT
      LAYER M4 ;
      RECT 0.000 30.960 0.024 30.984 ;
    END
  END W0_data[111]
  PIN W0_data[112]
    DIRECTION INPUT ;
    USE SIGNAL ;
    SHAPE ABUTMENT ;
    PORT
      LAYER M4 ;
      RECT 0.000 31.008 0.024 31.032 ;
    END
  END W0_data[112]
  PIN W0_data[113]
    DIRECTION INPUT ;
    USE SIGNAL ;
    SHAPE ABUTMENT ;
    PORT
      LAYER M4 ;
      RECT 0.000 31.056 0.024 31.080 ;
    END
  END W0_data[113]
  PIN W0_data[114]
    DIRECTION INPUT ;
    USE SIGNAL ;
    SHAPE ABUTMENT ;
    PORT
      LAYER M4 ;
      RECT 0.000 31.104 0.024 31.128 ;
    END
  END W0_data[114]
  PIN W0_data[115]
    DIRECTION INPUT ;
    USE SIGNAL ;
    SHAPE ABUTMENT ;
    PORT
      LAYER M4 ;
      RECT 0.000 31.152 0.024 31.176 ;
    END
  END W0_data[115]
  PIN W0_data[116]
    DIRECTION INPUT ;
    USE SIGNAL ;
    SHAPE ABUTMENT ;
    PORT
      LAYER M4 ;
      RECT 0.000 31.200 0.024 31.224 ;
    END
  END W0_data[116]
  PIN W0_data[117]
    DIRECTION INPUT ;
    USE SIGNAL ;
    SHAPE ABUTMENT ;
    PORT
      LAYER M4 ;
      RECT 0.000 31.248 0.024 31.272 ;
    END
  END W0_data[117]
  PIN W0_data[118]
    DIRECTION INPUT ;
    USE SIGNAL ;
    SHAPE ABUTMENT ;
    PORT
      LAYER M4 ;
      RECT 0.000 31.296 0.024 31.320 ;
    END
  END W0_data[118]
  PIN W0_data[119]
    DIRECTION INPUT ;
    USE SIGNAL ;
    SHAPE ABUTMENT ;
    PORT
      LAYER M4 ;
      RECT 0.000 31.344 0.024 31.368 ;
    END
  END W0_data[119]
  PIN W0_data[120]
    DIRECTION INPUT ;
    USE SIGNAL ;
    SHAPE ABUTMENT ;
    PORT
      LAYER M4 ;
      RECT 0.000 31.392 0.024 31.416 ;
    END
  END W0_data[120]
  PIN W0_data[121]
    DIRECTION INPUT ;
    USE SIGNAL ;
    SHAPE ABUTMENT ;
    PORT
      LAYER M4 ;
      RECT 0.000 31.440 0.024 31.464 ;
    END
  END W0_data[121]
  PIN W0_data[122]
    DIRECTION INPUT ;
    USE SIGNAL ;
    SHAPE ABUTMENT ;
    PORT
      LAYER M4 ;
      RECT 0.000 31.488 0.024 31.512 ;
    END
  END W0_data[122]
  PIN W0_data[123]
    DIRECTION INPUT ;
    USE SIGNAL ;
    SHAPE ABUTMENT ;
    PORT
      LAYER M4 ;
      RECT 0.000 31.536 0.024 31.560 ;
    END
  END W0_data[123]
  PIN W0_data[124]
    DIRECTION INPUT ;
    USE SIGNAL ;
    SHAPE ABUTMENT ;
    PORT
      LAYER M4 ;
      RECT 0.000 31.584 0.024 31.608 ;
    END
  END W0_data[124]
  PIN W0_data[125]
    DIRECTION INPUT ;
    USE SIGNAL ;
    SHAPE ABUTMENT ;
    PORT
      LAYER M4 ;
      RECT 0.000 31.632 0.024 31.656 ;
    END
  END W0_data[125]
  PIN W0_data[126]
    DIRECTION INPUT ;
    USE SIGNAL ;
    SHAPE ABUTMENT ;
    PORT
      LAYER M4 ;
      RECT 0.000 31.680 0.024 31.704 ;
    END
  END W0_data[126]
  PIN W0_data[127]
    DIRECTION INPUT ;
    USE SIGNAL ;
    SHAPE ABUTMENT ;
    PORT
      LAYER M4 ;
      RECT 0.000 31.728 0.024 31.752 ;
    END
  END W0_data[127]
  PIN W0_data[128]
    DIRECTION INPUT ;
    USE SIGNAL ;
    SHAPE ABUTMENT ;
    PORT
      LAYER M4 ;
      RECT 0.000 31.776 0.024 31.800 ;
    END
  END W0_data[128]
  PIN W0_data[129]
    DIRECTION INPUT ;
    USE SIGNAL ;
    SHAPE ABUTMENT ;
    PORT
      LAYER M4 ;
      RECT 0.000 31.824 0.024 31.848 ;
    END
  END W0_data[129]
  PIN W0_data[130]
    DIRECTION INPUT ;
    USE SIGNAL ;
    SHAPE ABUTMENT ;
    PORT
      LAYER M4 ;
      RECT 0.000 31.872 0.024 31.896 ;
    END
  END W0_data[130]
  PIN W0_data[131]
    DIRECTION INPUT ;
    USE SIGNAL ;
    SHAPE ABUTMENT ;
    PORT
      LAYER M4 ;
      RECT 0.000 31.920 0.024 31.944 ;
    END
  END W0_data[131]
  PIN W0_data[132]
    DIRECTION INPUT ;
    USE SIGNAL ;
    SHAPE ABUTMENT ;
    PORT
      LAYER M4 ;
      RECT 0.000 31.968 0.024 31.992 ;
    END
  END W0_data[132]
  PIN W0_data[133]
    DIRECTION INPUT ;
    USE SIGNAL ;
    SHAPE ABUTMENT ;
    PORT
      LAYER M4 ;
      RECT 0.000 32.016 0.024 32.040 ;
    END
  END W0_data[133]
  PIN W0_data[134]
    DIRECTION INPUT ;
    USE SIGNAL ;
    SHAPE ABUTMENT ;
    PORT
      LAYER M4 ;
      RECT 0.000 32.064 0.024 32.088 ;
    END
  END W0_data[134]
  PIN W0_data[135]
    DIRECTION INPUT ;
    USE SIGNAL ;
    SHAPE ABUTMENT ;
    PORT
      LAYER M4 ;
      RECT 0.000 32.112 0.024 32.136 ;
    END
  END W0_data[135]
  PIN W0_data[136]
    DIRECTION INPUT ;
    USE SIGNAL ;
    SHAPE ABUTMENT ;
    PORT
      LAYER M4 ;
      RECT 0.000 32.160 0.024 32.184 ;
    END
  END W0_data[136]
  PIN W0_data[137]
    DIRECTION INPUT ;
    USE SIGNAL ;
    SHAPE ABUTMENT ;
    PORT
      LAYER M4 ;
      RECT 0.000 32.208 0.024 32.232 ;
    END
  END W0_data[137]
  PIN W0_data[138]
    DIRECTION INPUT ;
    USE SIGNAL ;
    SHAPE ABUTMENT ;
    PORT
      LAYER M4 ;
      RECT 0.000 32.256 0.024 32.280 ;
    END
  END W0_data[138]
  PIN W0_data[139]
    DIRECTION INPUT ;
    USE SIGNAL ;
    SHAPE ABUTMENT ;
    PORT
      LAYER M4 ;
      RECT 0.000 32.304 0.024 32.328 ;
    END
  END W0_data[139]
  PIN W0_data[140]
    DIRECTION INPUT ;
    USE SIGNAL ;
    SHAPE ABUTMENT ;
    PORT
      LAYER M4 ;
      RECT 0.000 32.352 0.024 32.376 ;
    END
  END W0_data[140]
  PIN W0_data[141]
    DIRECTION INPUT ;
    USE SIGNAL ;
    SHAPE ABUTMENT ;
    PORT
      LAYER M4 ;
      RECT 0.000 32.400 0.024 32.424 ;
    END
  END W0_data[141]
  PIN W0_data[142]
    DIRECTION INPUT ;
    USE SIGNAL ;
    SHAPE ABUTMENT ;
    PORT
      LAYER M4 ;
      RECT 0.000 32.448 0.024 32.472 ;
    END
  END W0_data[142]
  PIN W0_data[143]
    DIRECTION INPUT ;
    USE SIGNAL ;
    SHAPE ABUTMENT ;
    PORT
      LAYER M4 ;
      RECT 0.000 32.496 0.024 32.520 ;
    END
  END W0_data[143]
  PIN W0_data[144]
    DIRECTION INPUT ;
    USE SIGNAL ;
    SHAPE ABUTMENT ;
    PORT
      LAYER M4 ;
      RECT 0.000 32.544 0.024 32.568 ;
    END
  END W0_data[144]
  PIN W0_data[145]
    DIRECTION INPUT ;
    USE SIGNAL ;
    SHAPE ABUTMENT ;
    PORT
      LAYER M4 ;
      RECT 0.000 32.592 0.024 32.616 ;
    END
  END W0_data[145]
  PIN W0_data[146]
    DIRECTION INPUT ;
    USE SIGNAL ;
    SHAPE ABUTMENT ;
    PORT
      LAYER M4 ;
      RECT 0.000 32.640 0.024 32.664 ;
    END
  END W0_data[146]
  PIN W0_data[147]
    DIRECTION INPUT ;
    USE SIGNAL ;
    SHAPE ABUTMENT ;
    PORT
      LAYER M4 ;
      RECT 0.000 32.688 0.024 32.712 ;
    END
  END W0_data[147]
  PIN W0_data[148]
    DIRECTION INPUT ;
    USE SIGNAL ;
    SHAPE ABUTMENT ;
    PORT
      LAYER M4 ;
      RECT 0.000 32.736 0.024 32.760 ;
    END
  END W0_data[148]
  PIN W0_data[149]
    DIRECTION INPUT ;
    USE SIGNAL ;
    SHAPE ABUTMENT ;
    PORT
      LAYER M4 ;
      RECT 0.000 32.784 0.024 32.808 ;
    END
  END W0_data[149]
  PIN W0_data[150]
    DIRECTION INPUT ;
    USE SIGNAL ;
    SHAPE ABUTMENT ;
    PORT
      LAYER M4 ;
      RECT 0.000 32.832 0.024 32.856 ;
    END
  END W0_data[150]
  PIN W0_data[151]
    DIRECTION INPUT ;
    USE SIGNAL ;
    SHAPE ABUTMENT ;
    PORT
      LAYER M4 ;
      RECT 0.000 32.880 0.024 32.904 ;
    END
  END W0_data[151]
  PIN W0_data[152]
    DIRECTION INPUT ;
    USE SIGNAL ;
    SHAPE ABUTMENT ;
    PORT
      LAYER M4 ;
      RECT 0.000 32.928 0.024 32.952 ;
    END
  END W0_data[152]
  PIN W0_data[153]
    DIRECTION INPUT ;
    USE SIGNAL ;
    SHAPE ABUTMENT ;
    PORT
      LAYER M4 ;
      RECT 0.000 32.976 0.024 33.000 ;
    END
  END W0_data[153]
  PIN W0_data[154]
    DIRECTION INPUT ;
    USE SIGNAL ;
    SHAPE ABUTMENT ;
    PORT
      LAYER M4 ;
      RECT 0.000 33.024 0.024 33.048 ;
    END
  END W0_data[154]
  PIN W0_data[155]
    DIRECTION INPUT ;
    USE SIGNAL ;
    SHAPE ABUTMENT ;
    PORT
      LAYER M4 ;
      RECT 0.000 33.072 0.024 33.096 ;
    END
  END W0_data[155]
  PIN W0_data[156]
    DIRECTION INPUT ;
    USE SIGNAL ;
    SHAPE ABUTMENT ;
    PORT
      LAYER M4 ;
      RECT 0.000 33.120 0.024 33.144 ;
    END
  END W0_data[156]
  PIN W0_data[157]
    DIRECTION INPUT ;
    USE SIGNAL ;
    SHAPE ABUTMENT ;
    PORT
      LAYER M4 ;
      RECT 0.000 33.168 0.024 33.192 ;
    END
  END W0_data[157]
  PIN W0_data[158]
    DIRECTION INPUT ;
    USE SIGNAL ;
    SHAPE ABUTMENT ;
    PORT
      LAYER M4 ;
      RECT 0.000 33.216 0.024 33.240 ;
    END
  END W0_data[158]
  PIN W0_data[159]
    DIRECTION INPUT ;
    USE SIGNAL ;
    SHAPE ABUTMENT ;
    PORT
      LAYER M4 ;
      RECT 0.000 33.264 0.024 33.288 ;
    END
  END W0_data[159]
  PIN W0_data[160]
    DIRECTION INPUT ;
    USE SIGNAL ;
    SHAPE ABUTMENT ;
    PORT
      LAYER M4 ;
      RECT 0.000 33.312 0.024 33.336 ;
    END
  END W0_data[160]
  PIN W0_data[161]
    DIRECTION INPUT ;
    USE SIGNAL ;
    SHAPE ABUTMENT ;
    PORT
      LAYER M4 ;
      RECT 0.000 33.360 0.024 33.384 ;
    END
  END W0_data[161]
  PIN W0_data[162]
    DIRECTION INPUT ;
    USE SIGNAL ;
    SHAPE ABUTMENT ;
    PORT
      LAYER M4 ;
      RECT 0.000 33.408 0.024 33.432 ;
    END
  END W0_data[162]
  PIN W0_data[163]
    DIRECTION INPUT ;
    USE SIGNAL ;
    SHAPE ABUTMENT ;
    PORT
      LAYER M4 ;
      RECT 0.000 33.456 0.024 33.480 ;
    END
  END W0_data[163]
  PIN W0_data[164]
    DIRECTION INPUT ;
    USE SIGNAL ;
    SHAPE ABUTMENT ;
    PORT
      LAYER M4 ;
      RECT 0.000 33.504 0.024 33.528 ;
    END
  END W0_data[164]
  PIN W0_data[165]
    DIRECTION INPUT ;
    USE SIGNAL ;
    SHAPE ABUTMENT ;
    PORT
      LAYER M4 ;
      RECT 0.000 33.552 0.024 33.576 ;
    END
  END W0_data[165]
  PIN W0_data[166]
    DIRECTION INPUT ;
    USE SIGNAL ;
    SHAPE ABUTMENT ;
    PORT
      LAYER M4 ;
      RECT 0.000 33.600 0.024 33.624 ;
    END
  END W0_data[166]
  PIN W0_data[167]
    DIRECTION INPUT ;
    USE SIGNAL ;
    SHAPE ABUTMENT ;
    PORT
      LAYER M4 ;
      RECT 0.000 33.648 0.024 33.672 ;
    END
  END W0_data[167]
  PIN W0_data[168]
    DIRECTION INPUT ;
    USE SIGNAL ;
    SHAPE ABUTMENT ;
    PORT
      LAYER M4 ;
      RECT 0.000 33.696 0.024 33.720 ;
    END
  END W0_data[168]
  PIN W0_data[169]
    DIRECTION INPUT ;
    USE SIGNAL ;
    SHAPE ABUTMENT ;
    PORT
      LAYER M4 ;
      RECT 0.000 33.744 0.024 33.768 ;
    END
  END W0_data[169]
  PIN W0_data[170]
    DIRECTION INPUT ;
    USE SIGNAL ;
    SHAPE ABUTMENT ;
    PORT
      LAYER M4 ;
      RECT 0.000 33.792 0.024 33.816 ;
    END
  END W0_data[170]
  PIN W0_data[171]
    DIRECTION INPUT ;
    USE SIGNAL ;
    SHAPE ABUTMENT ;
    PORT
      LAYER M4 ;
      RECT 0.000 33.840 0.024 33.864 ;
    END
  END W0_data[171]
  PIN W0_data[172]
    DIRECTION INPUT ;
    USE SIGNAL ;
    SHAPE ABUTMENT ;
    PORT
      LAYER M4 ;
      RECT 0.000 33.888 0.024 33.912 ;
    END
  END W0_data[172]
  PIN W0_data[173]
    DIRECTION INPUT ;
    USE SIGNAL ;
    SHAPE ABUTMENT ;
    PORT
      LAYER M4 ;
      RECT 0.000 33.936 0.024 33.960 ;
    END
  END W0_data[173]
  PIN W0_data[174]
    DIRECTION INPUT ;
    USE SIGNAL ;
    SHAPE ABUTMENT ;
    PORT
      LAYER M4 ;
      RECT 0.000 33.984 0.024 34.008 ;
    END
  END W0_data[174]
  PIN W0_data[175]
    DIRECTION INPUT ;
    USE SIGNAL ;
    SHAPE ABUTMENT ;
    PORT
      LAYER M4 ;
      RECT 0.000 34.032 0.024 34.056 ;
    END
  END W0_data[175]
  PIN W0_data[176]
    DIRECTION INPUT ;
    USE SIGNAL ;
    SHAPE ABUTMENT ;
    PORT
      LAYER M4 ;
      RECT 0.000 34.080 0.024 34.104 ;
    END
  END W0_data[176]
  PIN W0_data[177]
    DIRECTION INPUT ;
    USE SIGNAL ;
    SHAPE ABUTMENT ;
    PORT
      LAYER M4 ;
      RECT 0.000 34.128 0.024 34.152 ;
    END
  END W0_data[177]
  PIN W0_data[178]
    DIRECTION INPUT ;
    USE SIGNAL ;
    SHAPE ABUTMENT ;
    PORT
      LAYER M4 ;
      RECT 0.000 34.176 0.024 34.200 ;
    END
  END W0_data[178]
  PIN W0_data[179]
    DIRECTION INPUT ;
    USE SIGNAL ;
    SHAPE ABUTMENT ;
    PORT
      LAYER M4 ;
      RECT 0.000 34.224 0.024 34.248 ;
    END
  END W0_data[179]
  PIN W0_data[180]
    DIRECTION INPUT ;
    USE SIGNAL ;
    SHAPE ABUTMENT ;
    PORT
      LAYER M4 ;
      RECT 0.000 34.272 0.024 34.296 ;
    END
  END W0_data[180]
  PIN W0_data[181]
    DIRECTION INPUT ;
    USE SIGNAL ;
    SHAPE ABUTMENT ;
    PORT
      LAYER M4 ;
      RECT 0.000 34.320 0.024 34.344 ;
    END
  END W0_data[181]
  PIN W0_data[182]
    DIRECTION INPUT ;
    USE SIGNAL ;
    SHAPE ABUTMENT ;
    PORT
      LAYER M4 ;
      RECT 0.000 34.368 0.024 34.392 ;
    END
  END W0_data[182]
  PIN W0_data[183]
    DIRECTION INPUT ;
    USE SIGNAL ;
    SHAPE ABUTMENT ;
    PORT
      LAYER M4 ;
      RECT 0.000 34.416 0.024 34.440 ;
    END
  END W0_data[183]
  PIN W0_data[184]
    DIRECTION INPUT ;
    USE SIGNAL ;
    SHAPE ABUTMENT ;
    PORT
      LAYER M4 ;
      RECT 0.000 34.464 0.024 34.488 ;
    END
  END W0_data[184]
  PIN W0_data[185]
    DIRECTION INPUT ;
    USE SIGNAL ;
    SHAPE ABUTMENT ;
    PORT
      LAYER M4 ;
      RECT 0.000 34.512 0.024 34.536 ;
    END
  END W0_data[185]
  PIN W0_data[186]
    DIRECTION INPUT ;
    USE SIGNAL ;
    SHAPE ABUTMENT ;
    PORT
      LAYER M4 ;
      RECT 0.000 34.560 0.024 34.584 ;
    END
  END W0_data[186]
  PIN W0_data[187]
    DIRECTION INPUT ;
    USE SIGNAL ;
    SHAPE ABUTMENT ;
    PORT
      LAYER M4 ;
      RECT 0.000 34.608 0.024 34.632 ;
    END
  END W0_data[187]
  PIN W0_data[188]
    DIRECTION INPUT ;
    USE SIGNAL ;
    SHAPE ABUTMENT ;
    PORT
      LAYER M4 ;
      RECT 0.000 34.656 0.024 34.680 ;
    END
  END W0_data[188]
  PIN W0_data[189]
    DIRECTION INPUT ;
    USE SIGNAL ;
    SHAPE ABUTMENT ;
    PORT
      LAYER M4 ;
      RECT 0.000 34.704 0.024 34.728 ;
    END
  END W0_data[189]
  PIN W0_data[190]
    DIRECTION INPUT ;
    USE SIGNAL ;
    SHAPE ABUTMENT ;
    PORT
      LAYER M4 ;
      RECT 0.000 34.752 0.024 34.776 ;
    END
  END W0_data[190]
  PIN W0_data[191]
    DIRECTION INPUT ;
    USE SIGNAL ;
    SHAPE ABUTMENT ;
    PORT
      LAYER M4 ;
      RECT 0.000 34.800 0.024 34.824 ;
    END
  END W0_data[191]
  PIN W0_data[192]
    DIRECTION INPUT ;
    USE SIGNAL ;
    SHAPE ABUTMENT ;
    PORT
      LAYER M4 ;
      RECT 0.000 34.848 0.024 34.872 ;
    END
  END W0_data[192]
  PIN W0_data[193]
    DIRECTION INPUT ;
    USE SIGNAL ;
    SHAPE ABUTMENT ;
    PORT
      LAYER M4 ;
      RECT 0.000 34.896 0.024 34.920 ;
    END
  END W0_data[193]
  PIN W0_data[194]
    DIRECTION INPUT ;
    USE SIGNAL ;
    SHAPE ABUTMENT ;
    PORT
      LAYER M4 ;
      RECT 0.000 34.944 0.024 34.968 ;
    END
  END W0_data[194]
  PIN W0_data[195]
    DIRECTION INPUT ;
    USE SIGNAL ;
    SHAPE ABUTMENT ;
    PORT
      LAYER M4 ;
      RECT 0.000 34.992 0.024 35.016 ;
    END
  END W0_data[195]
  PIN W0_data[196]
    DIRECTION INPUT ;
    USE SIGNAL ;
    SHAPE ABUTMENT ;
    PORT
      LAYER M4 ;
      RECT 0.000 35.040 0.024 35.064 ;
    END
  END W0_data[196]
  PIN W0_data[197]
    DIRECTION INPUT ;
    USE SIGNAL ;
    SHAPE ABUTMENT ;
    PORT
      LAYER M4 ;
      RECT 0.000 35.088 0.024 35.112 ;
    END
  END W0_data[197]
  PIN W0_data[198]
    DIRECTION INPUT ;
    USE SIGNAL ;
    SHAPE ABUTMENT ;
    PORT
      LAYER M4 ;
      RECT 0.000 35.136 0.024 35.160 ;
    END
  END W0_data[198]
  PIN W0_data[199]
    DIRECTION INPUT ;
    USE SIGNAL ;
    SHAPE ABUTMENT ;
    PORT
      LAYER M4 ;
      RECT 0.000 35.184 0.024 35.208 ;
    END
  END W0_data[199]
  PIN W0_data[200]
    DIRECTION INPUT ;
    USE SIGNAL ;
    SHAPE ABUTMENT ;
    PORT
      LAYER M4 ;
      RECT 0.000 35.232 0.024 35.256 ;
    END
  END W0_data[200]
  PIN W0_data[201]
    DIRECTION INPUT ;
    USE SIGNAL ;
    SHAPE ABUTMENT ;
    PORT
      LAYER M4 ;
      RECT 0.000 35.280 0.024 35.304 ;
    END
  END W0_data[201]
  PIN W0_data[202]
    DIRECTION INPUT ;
    USE SIGNAL ;
    SHAPE ABUTMENT ;
    PORT
      LAYER M4 ;
      RECT 0.000 35.328 0.024 35.352 ;
    END
  END W0_data[202]
  PIN W0_data[203]
    DIRECTION INPUT ;
    USE SIGNAL ;
    SHAPE ABUTMENT ;
    PORT
      LAYER M4 ;
      RECT 0.000 35.376 0.024 35.400 ;
    END
  END W0_data[203]
  PIN W0_data[204]
    DIRECTION INPUT ;
    USE SIGNAL ;
    SHAPE ABUTMENT ;
    PORT
      LAYER M4 ;
      RECT 0.000 35.424 0.024 35.448 ;
    END
  END W0_data[204]
  PIN W0_data[205]
    DIRECTION INPUT ;
    USE SIGNAL ;
    SHAPE ABUTMENT ;
    PORT
      LAYER M4 ;
      RECT 0.000 35.472 0.024 35.496 ;
    END
  END W0_data[205]
  PIN W0_data[206]
    DIRECTION INPUT ;
    USE SIGNAL ;
    SHAPE ABUTMENT ;
    PORT
      LAYER M4 ;
      RECT 0.000 35.520 0.024 35.544 ;
    END
  END W0_data[206]
  PIN W0_data[207]
    DIRECTION INPUT ;
    USE SIGNAL ;
    SHAPE ABUTMENT ;
    PORT
      LAYER M4 ;
      RECT 0.000 35.568 0.024 35.592 ;
    END
  END W0_data[207]
  PIN W0_data[208]
    DIRECTION INPUT ;
    USE SIGNAL ;
    SHAPE ABUTMENT ;
    PORT
      LAYER M4 ;
      RECT 0.000 35.616 0.024 35.640 ;
    END
  END W0_data[208]
  PIN W0_data[209]
    DIRECTION INPUT ;
    USE SIGNAL ;
    SHAPE ABUTMENT ;
    PORT
      LAYER M4 ;
      RECT 0.000 35.664 0.024 35.688 ;
    END
  END W0_data[209]
  PIN W0_data[210]
    DIRECTION INPUT ;
    USE SIGNAL ;
    SHAPE ABUTMENT ;
    PORT
      LAYER M4 ;
      RECT 0.000 35.712 0.024 35.736 ;
    END
  END W0_data[210]
  PIN W0_data[211]
    DIRECTION INPUT ;
    USE SIGNAL ;
    SHAPE ABUTMENT ;
    PORT
      LAYER M4 ;
      RECT 0.000 35.760 0.024 35.784 ;
    END
  END W0_data[211]
  PIN W0_data[212]
    DIRECTION INPUT ;
    USE SIGNAL ;
    SHAPE ABUTMENT ;
    PORT
      LAYER M4 ;
      RECT 0.000 35.808 0.024 35.832 ;
    END
  END W0_data[212]
  PIN W0_data[213]
    DIRECTION INPUT ;
    USE SIGNAL ;
    SHAPE ABUTMENT ;
    PORT
      LAYER M4 ;
      RECT 0.000 35.856 0.024 35.880 ;
    END
  END W0_data[213]
  PIN W0_data[214]
    DIRECTION INPUT ;
    USE SIGNAL ;
    SHAPE ABUTMENT ;
    PORT
      LAYER M4 ;
      RECT 0.000 35.904 0.024 35.928 ;
    END
  END W0_data[214]
  PIN W0_data[215]
    DIRECTION INPUT ;
    USE SIGNAL ;
    SHAPE ABUTMENT ;
    PORT
      LAYER M4 ;
      RECT 0.000 35.952 0.024 35.976 ;
    END
  END W0_data[215]
  PIN W0_data[216]
    DIRECTION INPUT ;
    USE SIGNAL ;
    SHAPE ABUTMENT ;
    PORT
      LAYER M4 ;
      RECT 0.000 36.000 0.024 36.024 ;
    END
  END W0_data[216]
  PIN W0_data[217]
    DIRECTION INPUT ;
    USE SIGNAL ;
    SHAPE ABUTMENT ;
    PORT
      LAYER M4 ;
      RECT 0.000 36.048 0.024 36.072 ;
    END
  END W0_data[217]
  PIN W0_data[218]
    DIRECTION INPUT ;
    USE SIGNAL ;
    SHAPE ABUTMENT ;
    PORT
      LAYER M4 ;
      RECT 0.000 36.096 0.024 36.120 ;
    END
  END W0_data[218]
  PIN W0_data[219]
    DIRECTION INPUT ;
    USE SIGNAL ;
    SHAPE ABUTMENT ;
    PORT
      LAYER M4 ;
      RECT 0.000 36.144 0.024 36.168 ;
    END
  END W0_data[219]
  PIN W0_data[220]
    DIRECTION INPUT ;
    USE SIGNAL ;
    SHAPE ABUTMENT ;
    PORT
      LAYER M4 ;
      RECT 0.000 36.192 0.024 36.216 ;
    END
  END W0_data[220]
  PIN W0_data[221]
    DIRECTION INPUT ;
    USE SIGNAL ;
    SHAPE ABUTMENT ;
    PORT
      LAYER M4 ;
      RECT 0.000 36.240 0.024 36.264 ;
    END
  END W0_data[221]
  PIN W0_data[222]
    DIRECTION INPUT ;
    USE SIGNAL ;
    SHAPE ABUTMENT ;
    PORT
      LAYER M4 ;
      RECT 0.000 36.288 0.024 36.312 ;
    END
  END W0_data[222]
  PIN W0_data[223]
    DIRECTION INPUT ;
    USE SIGNAL ;
    SHAPE ABUTMENT ;
    PORT
      LAYER M4 ;
      RECT 0.000 36.336 0.024 36.360 ;
    END
  END W0_data[223]
  PIN W0_data[224]
    DIRECTION INPUT ;
    USE SIGNAL ;
    SHAPE ABUTMENT ;
    PORT
      LAYER M4 ;
      RECT 0.000 36.384 0.024 36.408 ;
    END
  END W0_data[224]
  PIN W0_data[225]
    DIRECTION INPUT ;
    USE SIGNAL ;
    SHAPE ABUTMENT ;
    PORT
      LAYER M4 ;
      RECT 0.000 36.432 0.024 36.456 ;
    END
  END W0_data[225]
  PIN W0_data[226]
    DIRECTION INPUT ;
    USE SIGNAL ;
    SHAPE ABUTMENT ;
    PORT
      LAYER M4 ;
      RECT 0.000 36.480 0.024 36.504 ;
    END
  END W0_data[226]
  PIN W0_data[227]
    DIRECTION INPUT ;
    USE SIGNAL ;
    SHAPE ABUTMENT ;
    PORT
      LAYER M4 ;
      RECT 0.000 36.528 0.024 36.552 ;
    END
  END W0_data[227]
  PIN W0_data[228]
    DIRECTION INPUT ;
    USE SIGNAL ;
    SHAPE ABUTMENT ;
    PORT
      LAYER M4 ;
      RECT 0.000 36.576 0.024 36.600 ;
    END
  END W0_data[228]
  PIN W0_data[229]
    DIRECTION INPUT ;
    USE SIGNAL ;
    SHAPE ABUTMENT ;
    PORT
      LAYER M4 ;
      RECT 0.000 36.624 0.024 36.648 ;
    END
  END W0_data[229]
  PIN W0_data[230]
    DIRECTION INPUT ;
    USE SIGNAL ;
    SHAPE ABUTMENT ;
    PORT
      LAYER M4 ;
      RECT 0.000 36.672 0.024 36.696 ;
    END
  END W0_data[230]
  PIN W0_data[231]
    DIRECTION INPUT ;
    USE SIGNAL ;
    SHAPE ABUTMENT ;
    PORT
      LAYER M4 ;
      RECT 0.000 36.720 0.024 36.744 ;
    END
  END W0_data[231]
  PIN W0_data[232]
    DIRECTION INPUT ;
    USE SIGNAL ;
    SHAPE ABUTMENT ;
    PORT
      LAYER M4 ;
      RECT 0.000 36.768 0.024 36.792 ;
    END
  END W0_data[232]
  PIN W0_data[233]
    DIRECTION INPUT ;
    USE SIGNAL ;
    SHAPE ABUTMENT ;
    PORT
      LAYER M4 ;
      RECT 0.000 36.816 0.024 36.840 ;
    END
  END W0_data[233]
  PIN W0_data[234]
    DIRECTION INPUT ;
    USE SIGNAL ;
    SHAPE ABUTMENT ;
    PORT
      LAYER M4 ;
      RECT 0.000 36.864 0.024 36.888 ;
    END
  END W0_data[234]
  PIN W0_data[235]
    DIRECTION INPUT ;
    USE SIGNAL ;
    SHAPE ABUTMENT ;
    PORT
      LAYER M4 ;
      RECT 0.000 36.912 0.024 36.936 ;
    END
  END W0_data[235]
  PIN W0_data[236]
    DIRECTION INPUT ;
    USE SIGNAL ;
    SHAPE ABUTMENT ;
    PORT
      LAYER M4 ;
      RECT 0.000 36.960 0.024 36.984 ;
    END
  END W0_data[236]
  PIN W0_data[237]
    DIRECTION INPUT ;
    USE SIGNAL ;
    SHAPE ABUTMENT ;
    PORT
      LAYER M4 ;
      RECT 0.000 37.008 0.024 37.032 ;
    END
  END W0_data[237]
  PIN W0_data[238]
    DIRECTION INPUT ;
    USE SIGNAL ;
    SHAPE ABUTMENT ;
    PORT
      LAYER M4 ;
      RECT 0.000 37.056 0.024 37.080 ;
    END
  END W0_data[238]
  PIN W0_data[239]
    DIRECTION INPUT ;
    USE SIGNAL ;
    SHAPE ABUTMENT ;
    PORT
      LAYER M4 ;
      RECT 0.000 37.104 0.024 37.128 ;
    END
  END W0_data[239]
  PIN W0_data[240]
    DIRECTION INPUT ;
    USE SIGNAL ;
    SHAPE ABUTMENT ;
    PORT
      LAYER M4 ;
      RECT 0.000 37.152 0.024 37.176 ;
    END
  END W0_data[240]
  PIN W0_data[241]
    DIRECTION INPUT ;
    USE SIGNAL ;
    SHAPE ABUTMENT ;
    PORT
      LAYER M4 ;
      RECT 0.000 37.200 0.024 37.224 ;
    END
  END W0_data[241]
  PIN W0_data[242]
    DIRECTION INPUT ;
    USE SIGNAL ;
    SHAPE ABUTMENT ;
    PORT
      LAYER M4 ;
      RECT 0.000 37.248 0.024 37.272 ;
    END
  END W0_data[242]
  PIN W0_data[243]
    DIRECTION INPUT ;
    USE SIGNAL ;
    SHAPE ABUTMENT ;
    PORT
      LAYER M4 ;
      RECT 0.000 37.296 0.024 37.320 ;
    END
  END W0_data[243]
  PIN W0_data[244]
    DIRECTION INPUT ;
    USE SIGNAL ;
    SHAPE ABUTMENT ;
    PORT
      LAYER M4 ;
      RECT 0.000 37.344 0.024 37.368 ;
    END
  END W0_data[244]
  PIN W0_data[245]
    DIRECTION INPUT ;
    USE SIGNAL ;
    SHAPE ABUTMENT ;
    PORT
      LAYER M4 ;
      RECT 0.000 37.392 0.024 37.416 ;
    END
  END W0_data[245]
  PIN W0_data[246]
    DIRECTION INPUT ;
    USE SIGNAL ;
    SHAPE ABUTMENT ;
    PORT
      LAYER M4 ;
      RECT 0.000 37.440 0.024 37.464 ;
    END
  END W0_data[246]
  PIN W0_data[247]
    DIRECTION INPUT ;
    USE SIGNAL ;
    SHAPE ABUTMENT ;
    PORT
      LAYER M4 ;
      RECT 0.000 37.488 0.024 37.512 ;
    END
  END W0_data[247]
  PIN W0_data[248]
    DIRECTION INPUT ;
    USE SIGNAL ;
    SHAPE ABUTMENT ;
    PORT
      LAYER M4 ;
      RECT 0.000 37.536 0.024 37.560 ;
    END
  END W0_data[248]
  PIN W0_data[249]
    DIRECTION INPUT ;
    USE SIGNAL ;
    SHAPE ABUTMENT ;
    PORT
      LAYER M4 ;
      RECT 0.000 37.584 0.024 37.608 ;
    END
  END W0_data[249]
  PIN W0_data[250]
    DIRECTION INPUT ;
    USE SIGNAL ;
    SHAPE ABUTMENT ;
    PORT
      LAYER M4 ;
      RECT 0.000 37.632 0.024 37.656 ;
    END
  END W0_data[250]
  PIN W0_data[251]
    DIRECTION INPUT ;
    USE SIGNAL ;
    SHAPE ABUTMENT ;
    PORT
      LAYER M4 ;
      RECT 0.000 37.680 0.024 37.704 ;
    END
  END W0_data[251]
  PIN W0_data[252]
    DIRECTION INPUT ;
    USE SIGNAL ;
    SHAPE ABUTMENT ;
    PORT
      LAYER M4 ;
      RECT 0.000 37.728 0.024 37.752 ;
    END
  END W0_data[252]
  PIN W0_data[253]
    DIRECTION INPUT ;
    USE SIGNAL ;
    SHAPE ABUTMENT ;
    PORT
      LAYER M4 ;
      RECT 0.000 37.776 0.024 37.800 ;
    END
  END W0_data[253]
  PIN W0_data[254]
    DIRECTION INPUT ;
    USE SIGNAL ;
    SHAPE ABUTMENT ;
    PORT
      LAYER M4 ;
      RECT 0.000 37.824 0.024 37.848 ;
    END
  END W0_data[254]
  PIN W0_data[255]
    DIRECTION INPUT ;
    USE SIGNAL ;
    SHAPE ABUTMENT ;
    PORT
      LAYER M4 ;
      RECT 0.000 37.872 0.024 37.896 ;
    END
  END W0_data[255]
  PIN W0_data[256]
    DIRECTION INPUT ;
    USE SIGNAL ;
    SHAPE ABUTMENT ;
    PORT
      LAYER M4 ;
      RECT 0.000 37.920 0.024 37.944 ;
    END
  END W0_data[256]
  PIN W0_data[257]
    DIRECTION INPUT ;
    USE SIGNAL ;
    SHAPE ABUTMENT ;
    PORT
      LAYER M4 ;
      RECT 0.000 37.968 0.024 37.992 ;
    END
  END W0_data[257]
  PIN W0_data[258]
    DIRECTION INPUT ;
    USE SIGNAL ;
    SHAPE ABUTMENT ;
    PORT
      LAYER M4 ;
      RECT 0.000 38.016 0.024 38.040 ;
    END
  END W0_data[258]
  PIN W0_data[259]
    DIRECTION INPUT ;
    USE SIGNAL ;
    SHAPE ABUTMENT ;
    PORT
      LAYER M4 ;
      RECT 0.000 38.064 0.024 38.088 ;
    END
  END W0_data[259]
  PIN W0_data[260]
    DIRECTION INPUT ;
    USE SIGNAL ;
    SHAPE ABUTMENT ;
    PORT
      LAYER M4 ;
      RECT 0.000 38.112 0.024 38.136 ;
    END
  END W0_data[260]
  PIN W0_data[261]
    DIRECTION INPUT ;
    USE SIGNAL ;
    SHAPE ABUTMENT ;
    PORT
      LAYER M4 ;
      RECT 0.000 38.160 0.024 38.184 ;
    END
  END W0_data[261]
  PIN W0_data[262]
    DIRECTION INPUT ;
    USE SIGNAL ;
    SHAPE ABUTMENT ;
    PORT
      LAYER M4 ;
      RECT 0.000 38.208 0.024 38.232 ;
    END
  END W0_data[262]
  PIN W0_data[263]
    DIRECTION INPUT ;
    USE SIGNAL ;
    SHAPE ABUTMENT ;
    PORT
      LAYER M4 ;
      RECT 0.000 38.256 0.024 38.280 ;
    END
  END W0_data[263]
  PIN W0_data[264]
    DIRECTION INPUT ;
    USE SIGNAL ;
    SHAPE ABUTMENT ;
    PORT
      LAYER M4 ;
      RECT 0.000 38.304 0.024 38.328 ;
    END
  END W0_data[264]
  PIN W0_data[265]
    DIRECTION INPUT ;
    USE SIGNAL ;
    SHAPE ABUTMENT ;
    PORT
      LAYER M4 ;
      RECT 0.000 38.352 0.024 38.376 ;
    END
  END W0_data[265]
  PIN W0_data[266]
    DIRECTION INPUT ;
    USE SIGNAL ;
    SHAPE ABUTMENT ;
    PORT
      LAYER M4 ;
      RECT 0.000 38.400 0.024 38.424 ;
    END
  END W0_data[266]
  PIN W0_data[267]
    DIRECTION INPUT ;
    USE SIGNAL ;
    SHAPE ABUTMENT ;
    PORT
      LAYER M4 ;
      RECT 0.000 38.448 0.024 38.472 ;
    END
  END W0_data[267]
  PIN W0_data[268]
    DIRECTION INPUT ;
    USE SIGNAL ;
    SHAPE ABUTMENT ;
    PORT
      LAYER M4 ;
      RECT 0.000 38.496 0.024 38.520 ;
    END
  END W0_data[268]
  PIN W0_data[269]
    DIRECTION INPUT ;
    USE SIGNAL ;
    SHAPE ABUTMENT ;
    PORT
      LAYER M4 ;
      RECT 0.000 38.544 0.024 38.568 ;
    END
  END W0_data[269]
  PIN W0_data[270]
    DIRECTION INPUT ;
    USE SIGNAL ;
    SHAPE ABUTMENT ;
    PORT
      LAYER M4 ;
      RECT 0.000 38.592 0.024 38.616 ;
    END
  END W0_data[270]
  PIN W0_data[271]
    DIRECTION INPUT ;
    USE SIGNAL ;
    SHAPE ABUTMENT ;
    PORT
      LAYER M4 ;
      RECT 0.000 38.640 0.024 38.664 ;
    END
  END W0_data[271]
  PIN W0_data[272]
    DIRECTION INPUT ;
    USE SIGNAL ;
    SHAPE ABUTMENT ;
    PORT
      LAYER M4 ;
      RECT 0.000 38.688 0.024 38.712 ;
    END
  END W0_data[272]
  PIN W0_data[273]
    DIRECTION INPUT ;
    USE SIGNAL ;
    SHAPE ABUTMENT ;
    PORT
      LAYER M4 ;
      RECT 0.000 38.736 0.024 38.760 ;
    END
  END W0_data[273]
  PIN W0_data[274]
    DIRECTION INPUT ;
    USE SIGNAL ;
    SHAPE ABUTMENT ;
    PORT
      LAYER M4 ;
      RECT 0.000 38.784 0.024 38.808 ;
    END
  END W0_data[274]
  PIN W0_data[275]
    DIRECTION INPUT ;
    USE SIGNAL ;
    SHAPE ABUTMENT ;
    PORT
      LAYER M4 ;
      RECT 0.000 38.832 0.024 38.856 ;
    END
  END W0_data[275]
  PIN W0_data[276]
    DIRECTION INPUT ;
    USE SIGNAL ;
    SHAPE ABUTMENT ;
    PORT
      LAYER M4 ;
      RECT 0.000 38.880 0.024 38.904 ;
    END
  END W0_data[276]
  PIN W0_data[277]
    DIRECTION INPUT ;
    USE SIGNAL ;
    SHAPE ABUTMENT ;
    PORT
      LAYER M4 ;
      RECT 0.000 38.928 0.024 38.952 ;
    END
  END W0_data[277]
  PIN W0_data[278]
    DIRECTION INPUT ;
    USE SIGNAL ;
    SHAPE ABUTMENT ;
    PORT
      LAYER M4 ;
      RECT 0.000 38.976 0.024 39.000 ;
    END
  END W0_data[278]
  PIN W0_data[279]
    DIRECTION INPUT ;
    USE SIGNAL ;
    SHAPE ABUTMENT ;
    PORT
      LAYER M4 ;
      RECT 0.000 39.024 0.024 39.048 ;
    END
  END W0_data[279]
  PIN W0_data[280]
    DIRECTION INPUT ;
    USE SIGNAL ;
    SHAPE ABUTMENT ;
    PORT
      LAYER M4 ;
      RECT 0.000 39.072 0.024 39.096 ;
    END
  END W0_data[280]
  PIN W0_data[281]
    DIRECTION INPUT ;
    USE SIGNAL ;
    SHAPE ABUTMENT ;
    PORT
      LAYER M4 ;
      RECT 0.000 39.120 0.024 39.144 ;
    END
  END W0_data[281]
  PIN W0_data[282]
    DIRECTION INPUT ;
    USE SIGNAL ;
    SHAPE ABUTMENT ;
    PORT
      LAYER M4 ;
      RECT 0.000 39.168 0.024 39.192 ;
    END
  END W0_data[282]
  PIN W0_data[283]
    DIRECTION INPUT ;
    USE SIGNAL ;
    SHAPE ABUTMENT ;
    PORT
      LAYER M4 ;
      RECT 0.000 39.216 0.024 39.240 ;
    END
  END W0_data[283]
  PIN W0_data[284]
    DIRECTION INPUT ;
    USE SIGNAL ;
    SHAPE ABUTMENT ;
    PORT
      LAYER M4 ;
      RECT 0.000 39.264 0.024 39.288 ;
    END
  END W0_data[284]
  PIN W0_data[285]
    DIRECTION INPUT ;
    USE SIGNAL ;
    SHAPE ABUTMENT ;
    PORT
      LAYER M4 ;
      RECT 0.000 39.312 0.024 39.336 ;
    END
  END W0_data[285]
  PIN W0_data[286]
    DIRECTION INPUT ;
    USE SIGNAL ;
    SHAPE ABUTMENT ;
    PORT
      LAYER M4 ;
      RECT 0.000 39.360 0.024 39.384 ;
    END
  END W0_data[286]
  PIN W0_data[287]
    DIRECTION INPUT ;
    USE SIGNAL ;
    SHAPE ABUTMENT ;
    PORT
      LAYER M4 ;
      RECT 0.000 39.408 0.024 39.432 ;
    END
  END W0_data[287]
  PIN W0_data[288]
    DIRECTION INPUT ;
    USE SIGNAL ;
    SHAPE ABUTMENT ;
    PORT
      LAYER M4 ;
      RECT 0.000 39.456 0.024 39.480 ;
    END
  END W0_data[288]
  PIN W0_data[289]
    DIRECTION INPUT ;
    USE SIGNAL ;
    SHAPE ABUTMENT ;
    PORT
      LAYER M4 ;
      RECT 0.000 39.504 0.024 39.528 ;
    END
  END W0_data[289]
  PIN W0_data[290]
    DIRECTION INPUT ;
    USE SIGNAL ;
    SHAPE ABUTMENT ;
    PORT
      LAYER M4 ;
      RECT 0.000 39.552 0.024 39.576 ;
    END
  END W0_data[290]
  PIN W0_data[291]
    DIRECTION INPUT ;
    USE SIGNAL ;
    SHAPE ABUTMENT ;
    PORT
      LAYER M4 ;
      RECT 0.000 39.600 0.024 39.624 ;
    END
  END W0_data[291]
  PIN W0_data[292]
    DIRECTION INPUT ;
    USE SIGNAL ;
    SHAPE ABUTMENT ;
    PORT
      LAYER M4 ;
      RECT 0.000 39.648 0.024 39.672 ;
    END
  END W0_data[292]
  PIN W0_data[293]
    DIRECTION INPUT ;
    USE SIGNAL ;
    SHAPE ABUTMENT ;
    PORT
      LAYER M4 ;
      RECT 0.000 39.696 0.024 39.720 ;
    END
  END W0_data[293]
  PIN W0_data[294]
    DIRECTION INPUT ;
    USE SIGNAL ;
    SHAPE ABUTMENT ;
    PORT
      LAYER M4 ;
      RECT 0.000 39.744 0.024 39.768 ;
    END
  END W0_data[294]
  PIN W0_data[295]
    DIRECTION INPUT ;
    USE SIGNAL ;
    SHAPE ABUTMENT ;
    PORT
      LAYER M4 ;
      RECT 0.000 39.792 0.024 39.816 ;
    END
  END W0_data[295]
  PIN W0_data[296]
    DIRECTION INPUT ;
    USE SIGNAL ;
    SHAPE ABUTMENT ;
    PORT
      LAYER M4 ;
      RECT 0.000 39.840 0.024 39.864 ;
    END
  END W0_data[296]
  PIN W0_data[297]
    DIRECTION INPUT ;
    USE SIGNAL ;
    SHAPE ABUTMENT ;
    PORT
      LAYER M4 ;
      RECT 0.000 39.888 0.024 39.912 ;
    END
  END W0_data[297]
  PIN W0_data[298]
    DIRECTION INPUT ;
    USE SIGNAL ;
    SHAPE ABUTMENT ;
    PORT
      LAYER M4 ;
      RECT 0.000 39.936 0.024 39.960 ;
    END
  END W0_data[298]
  PIN W0_data[299]
    DIRECTION INPUT ;
    USE SIGNAL ;
    SHAPE ABUTMENT ;
    PORT
      LAYER M4 ;
      RECT 0.000 39.984 0.024 40.008 ;
    END
  END W0_data[299]
  PIN W0_data[300]
    DIRECTION INPUT ;
    USE SIGNAL ;
    SHAPE ABUTMENT ;
    PORT
      LAYER M4 ;
      RECT 0.000 40.032 0.024 40.056 ;
    END
  END W0_data[300]
  PIN W0_data[301]
    DIRECTION INPUT ;
    USE SIGNAL ;
    SHAPE ABUTMENT ;
    PORT
      LAYER M4 ;
      RECT 0.000 40.080 0.024 40.104 ;
    END
  END W0_data[301]
  PIN W0_data[302]
    DIRECTION INPUT ;
    USE SIGNAL ;
    SHAPE ABUTMENT ;
    PORT
      LAYER M4 ;
      RECT 0.000 40.128 0.024 40.152 ;
    END
  END W0_data[302]
  PIN W0_data[303]
    DIRECTION INPUT ;
    USE SIGNAL ;
    SHAPE ABUTMENT ;
    PORT
      LAYER M4 ;
      RECT 0.000 40.176 0.024 40.200 ;
    END
  END W0_data[303]
  PIN W0_data[304]
    DIRECTION INPUT ;
    USE SIGNAL ;
    SHAPE ABUTMENT ;
    PORT
      LAYER M4 ;
      RECT 0.000 40.224 0.024 40.248 ;
    END
  END W0_data[304]
  PIN W0_data[305]
    DIRECTION INPUT ;
    USE SIGNAL ;
    SHAPE ABUTMENT ;
    PORT
      LAYER M4 ;
      RECT 0.000 40.272 0.024 40.296 ;
    END
  END W0_data[305]
  PIN W0_data[306]
    DIRECTION INPUT ;
    USE SIGNAL ;
    SHAPE ABUTMENT ;
    PORT
      LAYER M4 ;
      RECT 0.000 40.320 0.024 40.344 ;
    END
  END W0_data[306]
  PIN W0_data[307]
    DIRECTION INPUT ;
    USE SIGNAL ;
    SHAPE ABUTMENT ;
    PORT
      LAYER M4 ;
      RECT 0.000 40.368 0.024 40.392 ;
    END
  END W0_data[307]
  PIN W0_data[308]
    DIRECTION INPUT ;
    USE SIGNAL ;
    SHAPE ABUTMENT ;
    PORT
      LAYER M4 ;
      RECT 0.000 40.416 0.024 40.440 ;
    END
  END W0_data[308]
  PIN W0_data[309]
    DIRECTION INPUT ;
    USE SIGNAL ;
    SHAPE ABUTMENT ;
    PORT
      LAYER M4 ;
      RECT 0.000 40.464 0.024 40.488 ;
    END
  END W0_data[309]
  PIN W0_data[310]
    DIRECTION INPUT ;
    USE SIGNAL ;
    SHAPE ABUTMENT ;
    PORT
      LAYER M4 ;
      RECT 0.000 40.512 0.024 40.536 ;
    END
  END W0_data[310]
  PIN W0_data[311]
    DIRECTION INPUT ;
    USE SIGNAL ;
    SHAPE ABUTMENT ;
    PORT
      LAYER M4 ;
      RECT 0.000 40.560 0.024 40.584 ;
    END
  END W0_data[311]
  PIN W0_data[312]
    DIRECTION INPUT ;
    USE SIGNAL ;
    SHAPE ABUTMENT ;
    PORT
      LAYER M4 ;
      RECT 0.000 40.608 0.024 40.632 ;
    END
  END W0_data[312]
  PIN W0_data[313]
    DIRECTION INPUT ;
    USE SIGNAL ;
    SHAPE ABUTMENT ;
    PORT
      LAYER M4 ;
      RECT 0.000 40.656 0.024 40.680 ;
    END
  END W0_data[313]
  PIN W0_data[314]
    DIRECTION INPUT ;
    USE SIGNAL ;
    SHAPE ABUTMENT ;
    PORT
      LAYER M4 ;
      RECT 0.000 40.704 0.024 40.728 ;
    END
  END W0_data[314]
  PIN W0_data[315]
    DIRECTION INPUT ;
    USE SIGNAL ;
    SHAPE ABUTMENT ;
    PORT
      LAYER M4 ;
      RECT 0.000 40.752 0.024 40.776 ;
    END
  END W0_data[315]
  PIN W0_data[316]
    DIRECTION INPUT ;
    USE SIGNAL ;
    SHAPE ABUTMENT ;
    PORT
      LAYER M4 ;
      RECT 0.000 40.800 0.024 40.824 ;
    END
  END W0_data[316]
  PIN W0_data[317]
    DIRECTION INPUT ;
    USE SIGNAL ;
    SHAPE ABUTMENT ;
    PORT
      LAYER M4 ;
      RECT 0.000 40.848 0.024 40.872 ;
    END
  END W0_data[317]
  PIN W0_data[318]
    DIRECTION INPUT ;
    USE SIGNAL ;
    SHAPE ABUTMENT ;
    PORT
      LAYER M4 ;
      RECT 0.000 40.896 0.024 40.920 ;
    END
  END W0_data[318]
  PIN W0_data[319]
    DIRECTION INPUT ;
    USE SIGNAL ;
    SHAPE ABUTMENT ;
    PORT
      LAYER M4 ;
      RECT 0.000 40.944 0.024 40.968 ;
    END
  END W0_data[319]
  PIN W0_data[320]
    DIRECTION INPUT ;
    USE SIGNAL ;
    SHAPE ABUTMENT ;
    PORT
      LAYER M4 ;
      RECT 0.000 40.992 0.024 41.016 ;
    END
  END W0_data[320]
  PIN W0_data[321]
    DIRECTION INPUT ;
    USE SIGNAL ;
    SHAPE ABUTMENT ;
    PORT
      LAYER M4 ;
      RECT 0.000 41.040 0.024 41.064 ;
    END
  END W0_data[321]
  PIN W0_data[322]
    DIRECTION INPUT ;
    USE SIGNAL ;
    SHAPE ABUTMENT ;
    PORT
      LAYER M4 ;
      RECT 0.000 41.088 0.024 41.112 ;
    END
  END W0_data[322]
  PIN W0_data[323]
    DIRECTION INPUT ;
    USE SIGNAL ;
    SHAPE ABUTMENT ;
    PORT
      LAYER M4 ;
      RECT 0.000 41.136 0.024 41.160 ;
    END
  END W0_data[323]
  PIN W0_data[324]
    DIRECTION INPUT ;
    USE SIGNAL ;
    SHAPE ABUTMENT ;
    PORT
      LAYER M4 ;
      RECT 0.000 41.184 0.024 41.208 ;
    END
  END W0_data[324]
  PIN W0_data[325]
    DIRECTION INPUT ;
    USE SIGNAL ;
    SHAPE ABUTMENT ;
    PORT
      LAYER M4 ;
      RECT 0.000 41.232 0.024 41.256 ;
    END
  END W0_data[325]
  PIN W0_data[326]
    DIRECTION INPUT ;
    USE SIGNAL ;
    SHAPE ABUTMENT ;
    PORT
      LAYER M4 ;
      RECT 0.000 41.280 0.024 41.304 ;
    END
  END W0_data[326]
  PIN W0_data[327]
    DIRECTION INPUT ;
    USE SIGNAL ;
    SHAPE ABUTMENT ;
    PORT
      LAYER M4 ;
      RECT 0.000 41.328 0.024 41.352 ;
    END
  END W0_data[327]
  PIN W0_data[328]
    DIRECTION INPUT ;
    USE SIGNAL ;
    SHAPE ABUTMENT ;
    PORT
      LAYER M4 ;
      RECT 0.000 41.376 0.024 41.400 ;
    END
  END W0_data[328]
  PIN W0_data[329]
    DIRECTION INPUT ;
    USE SIGNAL ;
    SHAPE ABUTMENT ;
    PORT
      LAYER M4 ;
      RECT 0.000 41.424 0.024 41.448 ;
    END
  END W0_data[329]
  PIN W0_data[330]
    DIRECTION INPUT ;
    USE SIGNAL ;
    SHAPE ABUTMENT ;
    PORT
      LAYER M4 ;
      RECT 0.000 41.472 0.024 41.496 ;
    END
  END W0_data[330]
  PIN W0_data[331]
    DIRECTION INPUT ;
    USE SIGNAL ;
    SHAPE ABUTMENT ;
    PORT
      LAYER M4 ;
      RECT 0.000 41.520 0.024 41.544 ;
    END
  END W0_data[331]
  PIN W0_data[332]
    DIRECTION INPUT ;
    USE SIGNAL ;
    SHAPE ABUTMENT ;
    PORT
      LAYER M4 ;
      RECT 0.000 41.568 0.024 41.592 ;
    END
  END W0_data[332]
  PIN W0_data[333]
    DIRECTION INPUT ;
    USE SIGNAL ;
    SHAPE ABUTMENT ;
    PORT
      LAYER M4 ;
      RECT 0.000 41.616 0.024 41.640 ;
    END
  END W0_data[333]
  PIN W0_data[334]
    DIRECTION INPUT ;
    USE SIGNAL ;
    SHAPE ABUTMENT ;
    PORT
      LAYER M4 ;
      RECT 0.000 41.664 0.024 41.688 ;
    END
  END W0_data[334]
  PIN W0_data[335]
    DIRECTION INPUT ;
    USE SIGNAL ;
    SHAPE ABUTMENT ;
    PORT
      LAYER M4 ;
      RECT 0.000 41.712 0.024 41.736 ;
    END
  END W0_data[335]
  PIN W0_data[336]
    DIRECTION INPUT ;
    USE SIGNAL ;
    SHAPE ABUTMENT ;
    PORT
      LAYER M4 ;
      RECT 0.000 41.760 0.024 41.784 ;
    END
  END W0_data[336]
  PIN W0_data[337]
    DIRECTION INPUT ;
    USE SIGNAL ;
    SHAPE ABUTMENT ;
    PORT
      LAYER M4 ;
      RECT 0.000 41.808 0.024 41.832 ;
    END
  END W0_data[337]
  PIN W0_data[338]
    DIRECTION INPUT ;
    USE SIGNAL ;
    SHAPE ABUTMENT ;
    PORT
      LAYER M4 ;
      RECT 0.000 41.856 0.024 41.880 ;
    END
  END W0_data[338]
  PIN W0_data[339]
    DIRECTION INPUT ;
    USE SIGNAL ;
    SHAPE ABUTMENT ;
    PORT
      LAYER M4 ;
      RECT 0.000 41.904 0.024 41.928 ;
    END
  END W0_data[339]
  PIN W0_data[340]
    DIRECTION INPUT ;
    USE SIGNAL ;
    SHAPE ABUTMENT ;
    PORT
      LAYER M4 ;
      RECT 0.000 41.952 0.024 41.976 ;
    END
  END W0_data[340]
  PIN W0_data[341]
    DIRECTION INPUT ;
    USE SIGNAL ;
    SHAPE ABUTMENT ;
    PORT
      LAYER M4 ;
      RECT 0.000 42.000 0.024 42.024 ;
    END
  END W0_data[341]
  PIN W0_data[342]
    DIRECTION INPUT ;
    USE SIGNAL ;
    SHAPE ABUTMENT ;
    PORT
      LAYER M4 ;
      RECT 0.000 42.048 0.024 42.072 ;
    END
  END W0_data[342]
  PIN W0_data[343]
    DIRECTION INPUT ;
    USE SIGNAL ;
    SHAPE ABUTMENT ;
    PORT
      LAYER M4 ;
      RECT 0.000 42.096 0.024 42.120 ;
    END
  END W0_data[343]
  PIN W0_data[344]
    DIRECTION INPUT ;
    USE SIGNAL ;
    SHAPE ABUTMENT ;
    PORT
      LAYER M4 ;
      RECT 0.000 42.144 0.024 42.168 ;
    END
  END W0_data[344]
  PIN W0_data[345]
    DIRECTION INPUT ;
    USE SIGNAL ;
    SHAPE ABUTMENT ;
    PORT
      LAYER M4 ;
      RECT 0.000 42.192 0.024 42.216 ;
    END
  END W0_data[345]
  PIN W0_data[346]
    DIRECTION INPUT ;
    USE SIGNAL ;
    SHAPE ABUTMENT ;
    PORT
      LAYER M4 ;
      RECT 0.000 42.240 0.024 42.264 ;
    END
  END W0_data[346]
  PIN W0_data[347]
    DIRECTION INPUT ;
    USE SIGNAL ;
    SHAPE ABUTMENT ;
    PORT
      LAYER M4 ;
      RECT 0.000 42.288 0.024 42.312 ;
    END
  END W0_data[347]
  PIN W0_data[348]
    DIRECTION INPUT ;
    USE SIGNAL ;
    SHAPE ABUTMENT ;
    PORT
      LAYER M4 ;
      RECT 0.000 42.336 0.024 42.360 ;
    END
  END W0_data[348]
  PIN W0_data[349]
    DIRECTION INPUT ;
    USE SIGNAL ;
    SHAPE ABUTMENT ;
    PORT
      LAYER M4 ;
      RECT 0.000 42.384 0.024 42.408 ;
    END
  END W0_data[349]
  PIN W0_data[350]
    DIRECTION INPUT ;
    USE SIGNAL ;
    SHAPE ABUTMENT ;
    PORT
      LAYER M4 ;
      RECT 0.000 42.432 0.024 42.456 ;
    END
  END W0_data[350]
  PIN W0_data[351]
    DIRECTION INPUT ;
    USE SIGNAL ;
    SHAPE ABUTMENT ;
    PORT
      LAYER M4 ;
      RECT 0.000 42.480 0.024 42.504 ;
    END
  END W0_data[351]
  PIN W0_data[352]
    DIRECTION INPUT ;
    USE SIGNAL ;
    SHAPE ABUTMENT ;
    PORT
      LAYER M4 ;
      RECT 0.000 42.528 0.024 42.552 ;
    END
  END W0_data[352]
  PIN W0_data[353]
    DIRECTION INPUT ;
    USE SIGNAL ;
    SHAPE ABUTMENT ;
    PORT
      LAYER M4 ;
      RECT 0.000 42.576 0.024 42.600 ;
    END
  END W0_data[353]
  PIN W0_data[354]
    DIRECTION INPUT ;
    USE SIGNAL ;
    SHAPE ABUTMENT ;
    PORT
      LAYER M4 ;
      RECT 0.000 42.624 0.024 42.648 ;
    END
  END W0_data[354]
  PIN W0_data[355]
    DIRECTION INPUT ;
    USE SIGNAL ;
    SHAPE ABUTMENT ;
    PORT
      LAYER M4 ;
      RECT 0.000 42.672 0.024 42.696 ;
    END
  END W0_data[355]
  PIN W0_data[356]
    DIRECTION INPUT ;
    USE SIGNAL ;
    SHAPE ABUTMENT ;
    PORT
      LAYER M4 ;
      RECT 0.000 42.720 0.024 42.744 ;
    END
  END W0_data[356]
  PIN W0_data[357]
    DIRECTION INPUT ;
    USE SIGNAL ;
    SHAPE ABUTMENT ;
    PORT
      LAYER M4 ;
      RECT 0.000 42.768 0.024 42.792 ;
    END
  END W0_data[357]
  PIN W0_data[358]
    DIRECTION INPUT ;
    USE SIGNAL ;
    SHAPE ABUTMENT ;
    PORT
      LAYER M4 ;
      RECT 0.000 42.816 0.024 42.840 ;
    END
  END W0_data[358]
  PIN W0_data[359]
    DIRECTION INPUT ;
    USE SIGNAL ;
    SHAPE ABUTMENT ;
    PORT
      LAYER M4 ;
      RECT 0.000 42.864 0.024 42.888 ;
    END
  END W0_data[359]
  PIN W0_data[360]
    DIRECTION INPUT ;
    USE SIGNAL ;
    SHAPE ABUTMENT ;
    PORT
      LAYER M4 ;
      RECT 0.000 42.912 0.024 42.936 ;
    END
  END W0_data[360]
  PIN W0_data[361]
    DIRECTION INPUT ;
    USE SIGNAL ;
    SHAPE ABUTMENT ;
    PORT
      LAYER M4 ;
      RECT 0.000 42.960 0.024 42.984 ;
    END
  END W0_data[361]
  PIN W0_data[362]
    DIRECTION INPUT ;
    USE SIGNAL ;
    SHAPE ABUTMENT ;
    PORT
      LAYER M4 ;
      RECT 0.000 43.008 0.024 43.032 ;
    END
  END W0_data[362]
  PIN W0_data[363]
    DIRECTION INPUT ;
    USE SIGNAL ;
    SHAPE ABUTMENT ;
    PORT
      LAYER M4 ;
      RECT 0.000 43.056 0.024 43.080 ;
    END
  END W0_data[363]
  PIN W0_data[364]
    DIRECTION INPUT ;
    USE SIGNAL ;
    SHAPE ABUTMENT ;
    PORT
      LAYER M4 ;
      RECT 0.000 43.104 0.024 43.128 ;
    END
  END W0_data[364]
  PIN W0_data[365]
    DIRECTION INPUT ;
    USE SIGNAL ;
    SHAPE ABUTMENT ;
    PORT
      LAYER M4 ;
      RECT 0.000 43.152 0.024 43.176 ;
    END
  END W0_data[365]
  PIN W0_data[366]
    DIRECTION INPUT ;
    USE SIGNAL ;
    SHAPE ABUTMENT ;
    PORT
      LAYER M4 ;
      RECT 0.000 43.200 0.024 43.224 ;
    END
  END W0_data[366]
  PIN W0_data[367]
    DIRECTION INPUT ;
    USE SIGNAL ;
    SHAPE ABUTMENT ;
    PORT
      LAYER M4 ;
      RECT 0.000 43.248 0.024 43.272 ;
    END
  END W0_data[367]
  PIN W0_data[368]
    DIRECTION INPUT ;
    USE SIGNAL ;
    SHAPE ABUTMENT ;
    PORT
      LAYER M4 ;
      RECT 0.000 43.296 0.024 43.320 ;
    END
  END W0_data[368]
  PIN W0_data[369]
    DIRECTION INPUT ;
    USE SIGNAL ;
    SHAPE ABUTMENT ;
    PORT
      LAYER M4 ;
      RECT 0.000 43.344 0.024 43.368 ;
    END
  END W0_data[369]
  PIN W0_data[370]
    DIRECTION INPUT ;
    USE SIGNAL ;
    SHAPE ABUTMENT ;
    PORT
      LAYER M4 ;
      RECT 0.000 43.392 0.024 43.416 ;
    END
  END W0_data[370]
  PIN W0_data[371]
    DIRECTION INPUT ;
    USE SIGNAL ;
    SHAPE ABUTMENT ;
    PORT
      LAYER M4 ;
      RECT 0.000 43.440 0.024 43.464 ;
    END
  END W0_data[371]
  PIN W0_data[372]
    DIRECTION INPUT ;
    USE SIGNAL ;
    SHAPE ABUTMENT ;
    PORT
      LAYER M4 ;
      RECT 0.000 43.488 0.024 43.512 ;
    END
  END W0_data[372]
  PIN W0_data[373]
    DIRECTION INPUT ;
    USE SIGNAL ;
    SHAPE ABUTMENT ;
    PORT
      LAYER M4 ;
      RECT 0.000 43.536 0.024 43.560 ;
    END
  END W0_data[373]
  PIN W0_data[374]
    DIRECTION INPUT ;
    USE SIGNAL ;
    SHAPE ABUTMENT ;
    PORT
      LAYER M4 ;
      RECT 0.000 43.584 0.024 43.608 ;
    END
  END W0_data[374]
  PIN W0_data[375]
    DIRECTION INPUT ;
    USE SIGNAL ;
    SHAPE ABUTMENT ;
    PORT
      LAYER M4 ;
      RECT 0.000 43.632 0.024 43.656 ;
    END
  END W0_data[375]
  PIN W0_data[376]
    DIRECTION INPUT ;
    USE SIGNAL ;
    SHAPE ABUTMENT ;
    PORT
      LAYER M4 ;
      RECT 0.000 43.680 0.024 43.704 ;
    END
  END W0_data[376]
  PIN W0_data[377]
    DIRECTION INPUT ;
    USE SIGNAL ;
    SHAPE ABUTMENT ;
    PORT
      LAYER M4 ;
      RECT 0.000 43.728 0.024 43.752 ;
    END
  END W0_data[377]
  PIN W0_data[378]
    DIRECTION INPUT ;
    USE SIGNAL ;
    SHAPE ABUTMENT ;
    PORT
      LAYER M4 ;
      RECT 0.000 43.776 0.024 43.800 ;
    END
  END W0_data[378]
  PIN W0_data[379]
    DIRECTION INPUT ;
    USE SIGNAL ;
    SHAPE ABUTMENT ;
    PORT
      LAYER M4 ;
      RECT 0.000 43.824 0.024 43.848 ;
    END
  END W0_data[379]
  PIN W0_data[380]
    DIRECTION INPUT ;
    USE SIGNAL ;
    SHAPE ABUTMENT ;
    PORT
      LAYER M4 ;
      RECT 0.000 43.872 0.024 43.896 ;
    END
  END W0_data[380]
  PIN W0_data[381]
    DIRECTION INPUT ;
    USE SIGNAL ;
    SHAPE ABUTMENT ;
    PORT
      LAYER M4 ;
      RECT 0.000 43.920 0.024 43.944 ;
    END
  END W0_data[381]
  PIN W0_data[382]
    DIRECTION INPUT ;
    USE SIGNAL ;
    SHAPE ABUTMENT ;
    PORT
      LAYER M4 ;
      RECT 0.000 43.968 0.024 43.992 ;
    END
  END W0_data[382]
  PIN W0_data[383]
    DIRECTION INPUT ;
    USE SIGNAL ;
    SHAPE ABUTMENT ;
    PORT
      LAYER M4 ;
      RECT 0.000 44.016 0.024 44.040 ;
    END
  END W0_data[383]
  PIN W0_data[384]
    DIRECTION INPUT ;
    USE SIGNAL ;
    SHAPE ABUTMENT ;
    PORT
      LAYER M4 ;
      RECT 0.000 44.064 0.024 44.088 ;
    END
  END W0_data[384]
  PIN W0_data[385]
    DIRECTION INPUT ;
    USE SIGNAL ;
    SHAPE ABUTMENT ;
    PORT
      LAYER M4 ;
      RECT 0.000 44.112 0.024 44.136 ;
    END
  END W0_data[385]
  PIN W0_data[386]
    DIRECTION INPUT ;
    USE SIGNAL ;
    SHAPE ABUTMENT ;
    PORT
      LAYER M4 ;
      RECT 0.000 44.160 0.024 44.184 ;
    END
  END W0_data[386]
  PIN W0_data[387]
    DIRECTION INPUT ;
    USE SIGNAL ;
    SHAPE ABUTMENT ;
    PORT
      LAYER M4 ;
      RECT 0.000 44.208 0.024 44.232 ;
    END
  END W0_data[387]
  PIN W0_data[388]
    DIRECTION INPUT ;
    USE SIGNAL ;
    SHAPE ABUTMENT ;
    PORT
      LAYER M4 ;
      RECT 0.000 44.256 0.024 44.280 ;
    END
  END W0_data[388]
  PIN W0_data[389]
    DIRECTION INPUT ;
    USE SIGNAL ;
    SHAPE ABUTMENT ;
    PORT
      LAYER M4 ;
      RECT 0.000 44.304 0.024 44.328 ;
    END
  END W0_data[389]
  PIN W0_data[390]
    DIRECTION INPUT ;
    USE SIGNAL ;
    SHAPE ABUTMENT ;
    PORT
      LAYER M4 ;
      RECT 0.000 44.352 0.024 44.376 ;
    END
  END W0_data[390]
  PIN W0_data[391]
    DIRECTION INPUT ;
    USE SIGNAL ;
    SHAPE ABUTMENT ;
    PORT
      LAYER M4 ;
      RECT 0.000 44.400 0.024 44.424 ;
    END
  END W0_data[391]
  PIN W0_data[392]
    DIRECTION INPUT ;
    USE SIGNAL ;
    SHAPE ABUTMENT ;
    PORT
      LAYER M4 ;
      RECT 0.000 44.448 0.024 44.472 ;
    END
  END W0_data[392]
  PIN W0_data[393]
    DIRECTION INPUT ;
    USE SIGNAL ;
    SHAPE ABUTMENT ;
    PORT
      LAYER M4 ;
      RECT 0.000 44.496 0.024 44.520 ;
    END
  END W0_data[393]
  PIN W0_data[394]
    DIRECTION INPUT ;
    USE SIGNAL ;
    SHAPE ABUTMENT ;
    PORT
      LAYER M4 ;
      RECT 0.000 44.544 0.024 44.568 ;
    END
  END W0_data[394]
  PIN W0_data[395]
    DIRECTION INPUT ;
    USE SIGNAL ;
    SHAPE ABUTMENT ;
    PORT
      LAYER M4 ;
      RECT 0.000 44.592 0.024 44.616 ;
    END
  END W0_data[395]
  PIN W0_data[396]
    DIRECTION INPUT ;
    USE SIGNAL ;
    SHAPE ABUTMENT ;
    PORT
      LAYER M4 ;
      RECT 0.000 44.640 0.024 44.664 ;
    END
  END W0_data[396]
  PIN W0_data[397]
    DIRECTION INPUT ;
    USE SIGNAL ;
    SHAPE ABUTMENT ;
    PORT
      LAYER M4 ;
      RECT 0.000 44.688 0.024 44.712 ;
    END
  END W0_data[397]
  PIN W0_data[398]
    DIRECTION INPUT ;
    USE SIGNAL ;
    SHAPE ABUTMENT ;
    PORT
      LAYER M4 ;
      RECT 0.000 44.736 0.024 44.760 ;
    END
  END W0_data[398]
  PIN W0_data[399]
    DIRECTION INPUT ;
    USE SIGNAL ;
    SHAPE ABUTMENT ;
    PORT
      LAYER M4 ;
      RECT 0.000 44.784 0.024 44.808 ;
    END
  END W0_data[399]
  PIN W0_data[400]
    DIRECTION INPUT ;
    USE SIGNAL ;
    SHAPE ABUTMENT ;
    PORT
      LAYER M4 ;
      RECT 0.000 44.832 0.024 44.856 ;
    END
  END W0_data[400]
  PIN W0_data[401]
    DIRECTION INPUT ;
    USE SIGNAL ;
    SHAPE ABUTMENT ;
    PORT
      LAYER M4 ;
      RECT 0.000 44.880 0.024 44.904 ;
    END
  END W0_data[401]
  PIN W0_data[402]
    DIRECTION INPUT ;
    USE SIGNAL ;
    SHAPE ABUTMENT ;
    PORT
      LAYER M4 ;
      RECT 0.000 44.928 0.024 44.952 ;
    END
  END W0_data[402]
  PIN W0_data[403]
    DIRECTION INPUT ;
    USE SIGNAL ;
    SHAPE ABUTMENT ;
    PORT
      LAYER M4 ;
      RECT 0.000 44.976 0.024 45.000 ;
    END
  END W0_data[403]
  PIN W0_data[404]
    DIRECTION INPUT ;
    USE SIGNAL ;
    SHAPE ABUTMENT ;
    PORT
      LAYER M4 ;
      RECT 0.000 45.024 0.024 45.048 ;
    END
  END W0_data[404]
  PIN W0_data[405]
    DIRECTION INPUT ;
    USE SIGNAL ;
    SHAPE ABUTMENT ;
    PORT
      LAYER M4 ;
      RECT 0.000 45.072 0.024 45.096 ;
    END
  END W0_data[405]
  PIN W0_data[406]
    DIRECTION INPUT ;
    USE SIGNAL ;
    SHAPE ABUTMENT ;
    PORT
      LAYER M4 ;
      RECT 0.000 45.120 0.024 45.144 ;
    END
  END W0_data[406]
  PIN W0_data[407]
    DIRECTION INPUT ;
    USE SIGNAL ;
    SHAPE ABUTMENT ;
    PORT
      LAYER M4 ;
      RECT 0.000 45.168 0.024 45.192 ;
    END
  END W0_data[407]
  PIN W0_data[408]
    DIRECTION INPUT ;
    USE SIGNAL ;
    SHAPE ABUTMENT ;
    PORT
      LAYER M4 ;
      RECT 0.000 45.216 0.024 45.240 ;
    END
  END W0_data[408]
  PIN W0_data[409]
    DIRECTION INPUT ;
    USE SIGNAL ;
    SHAPE ABUTMENT ;
    PORT
      LAYER M4 ;
      RECT 0.000 45.264 0.024 45.288 ;
    END
  END W0_data[409]
  PIN W0_data[410]
    DIRECTION INPUT ;
    USE SIGNAL ;
    SHAPE ABUTMENT ;
    PORT
      LAYER M4 ;
      RECT 0.000 45.312 0.024 45.336 ;
    END
  END W0_data[410]
  PIN W0_data[411]
    DIRECTION INPUT ;
    USE SIGNAL ;
    SHAPE ABUTMENT ;
    PORT
      LAYER M4 ;
      RECT 0.000 45.360 0.024 45.384 ;
    END
  END W0_data[411]
  PIN W0_data[412]
    DIRECTION INPUT ;
    USE SIGNAL ;
    SHAPE ABUTMENT ;
    PORT
      LAYER M4 ;
      RECT 0.000 45.408 0.024 45.432 ;
    END
  END W0_data[412]
  PIN W0_data[413]
    DIRECTION INPUT ;
    USE SIGNAL ;
    SHAPE ABUTMENT ;
    PORT
      LAYER M4 ;
      RECT 0.000 45.456 0.024 45.480 ;
    END
  END W0_data[413]
  PIN W0_data[414]
    DIRECTION INPUT ;
    USE SIGNAL ;
    SHAPE ABUTMENT ;
    PORT
      LAYER M4 ;
      RECT 0.000 45.504 0.024 45.528 ;
    END
  END W0_data[414]
  PIN W0_data[415]
    DIRECTION INPUT ;
    USE SIGNAL ;
    SHAPE ABUTMENT ;
    PORT
      LAYER M4 ;
      RECT 0.000 45.552 0.024 45.576 ;
    END
  END W0_data[415]
  PIN W0_data[416]
    DIRECTION INPUT ;
    USE SIGNAL ;
    SHAPE ABUTMENT ;
    PORT
      LAYER M4 ;
      RECT 0.000 45.600 0.024 45.624 ;
    END
  END W0_data[416]
  PIN W0_data[417]
    DIRECTION INPUT ;
    USE SIGNAL ;
    SHAPE ABUTMENT ;
    PORT
      LAYER M4 ;
      RECT 0.000 45.648 0.024 45.672 ;
    END
  END W0_data[417]
  PIN W0_data[418]
    DIRECTION INPUT ;
    USE SIGNAL ;
    SHAPE ABUTMENT ;
    PORT
      LAYER M4 ;
      RECT 0.000 45.696 0.024 45.720 ;
    END
  END W0_data[418]
  PIN W0_data[419]
    DIRECTION INPUT ;
    USE SIGNAL ;
    SHAPE ABUTMENT ;
    PORT
      LAYER M4 ;
      RECT 0.000 45.744 0.024 45.768 ;
    END
  END W0_data[419]
  PIN W0_data[420]
    DIRECTION INPUT ;
    USE SIGNAL ;
    SHAPE ABUTMENT ;
    PORT
      LAYER M4 ;
      RECT 0.000 45.792 0.024 45.816 ;
    END
  END W0_data[420]
  PIN W0_data[421]
    DIRECTION INPUT ;
    USE SIGNAL ;
    SHAPE ABUTMENT ;
    PORT
      LAYER M4 ;
      RECT 0.000 45.840 0.024 45.864 ;
    END
  END W0_data[421]
  PIN W0_data[422]
    DIRECTION INPUT ;
    USE SIGNAL ;
    SHAPE ABUTMENT ;
    PORT
      LAYER M4 ;
      RECT 0.000 45.888 0.024 45.912 ;
    END
  END W0_data[422]
  PIN W0_data[423]
    DIRECTION INPUT ;
    USE SIGNAL ;
    SHAPE ABUTMENT ;
    PORT
      LAYER M4 ;
      RECT 0.000 45.936 0.024 45.960 ;
    END
  END W0_data[423]
  PIN W0_data[424]
    DIRECTION INPUT ;
    USE SIGNAL ;
    SHAPE ABUTMENT ;
    PORT
      LAYER M4 ;
      RECT 0.000 45.984 0.024 46.008 ;
    END
  END W0_data[424]
  PIN W0_data[425]
    DIRECTION INPUT ;
    USE SIGNAL ;
    SHAPE ABUTMENT ;
    PORT
      LAYER M4 ;
      RECT 0.000 46.032 0.024 46.056 ;
    END
  END W0_data[425]
  PIN W0_data[426]
    DIRECTION INPUT ;
    USE SIGNAL ;
    SHAPE ABUTMENT ;
    PORT
      LAYER M4 ;
      RECT 0.000 46.080 0.024 46.104 ;
    END
  END W0_data[426]
  PIN W0_data[427]
    DIRECTION INPUT ;
    USE SIGNAL ;
    SHAPE ABUTMENT ;
    PORT
      LAYER M4 ;
      RECT 0.000 46.128 0.024 46.152 ;
    END
  END W0_data[427]
  PIN W0_data[428]
    DIRECTION INPUT ;
    USE SIGNAL ;
    SHAPE ABUTMENT ;
    PORT
      LAYER M4 ;
      RECT 0.000 46.176 0.024 46.200 ;
    END
  END W0_data[428]
  PIN W0_data[429]
    DIRECTION INPUT ;
    USE SIGNAL ;
    SHAPE ABUTMENT ;
    PORT
      LAYER M4 ;
      RECT 0.000 46.224 0.024 46.248 ;
    END
  END W0_data[429]
  PIN W0_data[430]
    DIRECTION INPUT ;
    USE SIGNAL ;
    SHAPE ABUTMENT ;
    PORT
      LAYER M4 ;
      RECT 0.000 46.272 0.024 46.296 ;
    END
  END W0_data[430]
  PIN W0_data[431]
    DIRECTION INPUT ;
    USE SIGNAL ;
    SHAPE ABUTMENT ;
    PORT
      LAYER M4 ;
      RECT 0.000 46.320 0.024 46.344 ;
    END
  END W0_data[431]
  PIN W0_data[432]
    DIRECTION INPUT ;
    USE SIGNAL ;
    SHAPE ABUTMENT ;
    PORT
      LAYER M4 ;
      RECT 0.000 46.368 0.024 46.392 ;
    END
  END W0_data[432]
  PIN W0_data[433]
    DIRECTION INPUT ;
    USE SIGNAL ;
    SHAPE ABUTMENT ;
    PORT
      LAYER M4 ;
      RECT 0.000 46.416 0.024 46.440 ;
    END
  END W0_data[433]
  PIN W0_data[434]
    DIRECTION INPUT ;
    USE SIGNAL ;
    SHAPE ABUTMENT ;
    PORT
      LAYER M4 ;
      RECT 0.000 46.464 0.024 46.488 ;
    END
  END W0_data[434]
  PIN W0_data[435]
    DIRECTION INPUT ;
    USE SIGNAL ;
    SHAPE ABUTMENT ;
    PORT
      LAYER M4 ;
      RECT 0.000 46.512 0.024 46.536 ;
    END
  END W0_data[435]
  PIN W0_data[436]
    DIRECTION INPUT ;
    USE SIGNAL ;
    SHAPE ABUTMENT ;
    PORT
      LAYER M4 ;
      RECT 0.000 46.560 0.024 46.584 ;
    END
  END W0_data[436]
  PIN W0_data[437]
    DIRECTION INPUT ;
    USE SIGNAL ;
    SHAPE ABUTMENT ;
    PORT
      LAYER M4 ;
      RECT 0.000 46.608 0.024 46.632 ;
    END
  END W0_data[437]
  PIN W0_data[438]
    DIRECTION INPUT ;
    USE SIGNAL ;
    SHAPE ABUTMENT ;
    PORT
      LAYER M4 ;
      RECT 0.000 46.656 0.024 46.680 ;
    END
  END W0_data[438]
  PIN W0_data[439]
    DIRECTION INPUT ;
    USE SIGNAL ;
    SHAPE ABUTMENT ;
    PORT
      LAYER M4 ;
      RECT 0.000 46.704 0.024 46.728 ;
    END
  END W0_data[439]
  PIN W0_data[440]
    DIRECTION INPUT ;
    USE SIGNAL ;
    SHAPE ABUTMENT ;
    PORT
      LAYER M4 ;
      RECT 0.000 46.752 0.024 46.776 ;
    END
  END W0_data[440]
  PIN W0_data[441]
    DIRECTION INPUT ;
    USE SIGNAL ;
    SHAPE ABUTMENT ;
    PORT
      LAYER M4 ;
      RECT 0.000 46.800 0.024 46.824 ;
    END
  END W0_data[441]
  PIN W0_data[442]
    DIRECTION INPUT ;
    USE SIGNAL ;
    SHAPE ABUTMENT ;
    PORT
      LAYER M4 ;
      RECT 0.000 46.848 0.024 46.872 ;
    END
  END W0_data[442]
  PIN W0_data[443]
    DIRECTION INPUT ;
    USE SIGNAL ;
    SHAPE ABUTMENT ;
    PORT
      LAYER M4 ;
      RECT 0.000 46.896 0.024 46.920 ;
    END
  END W0_data[443]
  PIN W0_data[444]
    DIRECTION INPUT ;
    USE SIGNAL ;
    SHAPE ABUTMENT ;
    PORT
      LAYER M4 ;
      RECT 0.000 46.944 0.024 46.968 ;
    END
  END W0_data[444]
  PIN W0_data[445]
    DIRECTION INPUT ;
    USE SIGNAL ;
    SHAPE ABUTMENT ;
    PORT
      LAYER M4 ;
      RECT 0.000 46.992 0.024 47.016 ;
    END
  END W0_data[445]
  PIN W0_data[446]
    DIRECTION INPUT ;
    USE SIGNAL ;
    SHAPE ABUTMENT ;
    PORT
      LAYER M4 ;
      RECT 0.000 47.040 0.024 47.064 ;
    END
  END W0_data[446]
  PIN W0_data[447]
    DIRECTION INPUT ;
    USE SIGNAL ;
    SHAPE ABUTMENT ;
    PORT
      LAYER M4 ;
      RECT 0.000 47.088 0.024 47.112 ;
    END
  END W0_data[447]
  PIN W0_data[448]
    DIRECTION INPUT ;
    USE SIGNAL ;
    SHAPE ABUTMENT ;
    PORT
      LAYER M4 ;
      RECT 0.000 47.136 0.024 47.160 ;
    END
  END W0_data[448]
  PIN W0_data[449]
    DIRECTION INPUT ;
    USE SIGNAL ;
    SHAPE ABUTMENT ;
    PORT
      LAYER M4 ;
      RECT 0.000 47.184 0.024 47.208 ;
    END
  END W0_data[449]
  PIN W0_data[450]
    DIRECTION INPUT ;
    USE SIGNAL ;
    SHAPE ABUTMENT ;
    PORT
      LAYER M4 ;
      RECT 0.000 47.232 0.024 47.256 ;
    END
  END W0_data[450]
  PIN W0_data[451]
    DIRECTION INPUT ;
    USE SIGNAL ;
    SHAPE ABUTMENT ;
    PORT
      LAYER M4 ;
      RECT 0.000 47.280 0.024 47.304 ;
    END
  END W0_data[451]
  PIN W0_data[452]
    DIRECTION INPUT ;
    USE SIGNAL ;
    SHAPE ABUTMENT ;
    PORT
      LAYER M4 ;
      RECT 0.000 47.328 0.024 47.352 ;
    END
  END W0_data[452]
  PIN W0_data[453]
    DIRECTION INPUT ;
    USE SIGNAL ;
    SHAPE ABUTMENT ;
    PORT
      LAYER M4 ;
      RECT 0.000 47.376 0.024 47.400 ;
    END
  END W0_data[453]
  PIN W0_data[454]
    DIRECTION INPUT ;
    USE SIGNAL ;
    SHAPE ABUTMENT ;
    PORT
      LAYER M4 ;
      RECT 0.000 47.424 0.024 47.448 ;
    END
  END W0_data[454]
  PIN W0_data[455]
    DIRECTION INPUT ;
    USE SIGNAL ;
    SHAPE ABUTMENT ;
    PORT
      LAYER M4 ;
      RECT 0.000 47.472 0.024 47.496 ;
    END
  END W0_data[455]
  PIN W0_data[456]
    DIRECTION INPUT ;
    USE SIGNAL ;
    SHAPE ABUTMENT ;
    PORT
      LAYER M4 ;
      RECT 0.000 47.520 0.024 47.544 ;
    END
  END W0_data[456]
  PIN W0_data[457]
    DIRECTION INPUT ;
    USE SIGNAL ;
    SHAPE ABUTMENT ;
    PORT
      LAYER M4 ;
      RECT 0.000 47.568 0.024 47.592 ;
    END
  END W0_data[457]
  PIN W0_data[458]
    DIRECTION INPUT ;
    USE SIGNAL ;
    SHAPE ABUTMENT ;
    PORT
      LAYER M4 ;
      RECT 0.000 47.616 0.024 47.640 ;
    END
  END W0_data[458]
  PIN W0_data[459]
    DIRECTION INPUT ;
    USE SIGNAL ;
    SHAPE ABUTMENT ;
    PORT
      LAYER M4 ;
      RECT 0.000 47.664 0.024 47.688 ;
    END
  END W0_data[459]
  PIN W0_data[460]
    DIRECTION INPUT ;
    USE SIGNAL ;
    SHAPE ABUTMENT ;
    PORT
      LAYER M4 ;
      RECT 0.000 47.712 0.024 47.736 ;
    END
  END W0_data[460]
  PIN W0_data[461]
    DIRECTION INPUT ;
    USE SIGNAL ;
    SHAPE ABUTMENT ;
    PORT
      LAYER M4 ;
      RECT 0.000 47.760 0.024 47.784 ;
    END
  END W0_data[461]
  PIN W0_data[462]
    DIRECTION INPUT ;
    USE SIGNAL ;
    SHAPE ABUTMENT ;
    PORT
      LAYER M4 ;
      RECT 0.000 47.808 0.024 47.832 ;
    END
  END W0_data[462]
  PIN W0_data[463]
    DIRECTION INPUT ;
    USE SIGNAL ;
    SHAPE ABUTMENT ;
    PORT
      LAYER M4 ;
      RECT 0.000 47.856 0.024 47.880 ;
    END
  END W0_data[463]
  PIN W0_data[464]
    DIRECTION INPUT ;
    USE SIGNAL ;
    SHAPE ABUTMENT ;
    PORT
      LAYER M4 ;
      RECT 0.000 47.904 0.024 47.928 ;
    END
  END W0_data[464]
  PIN W0_data[465]
    DIRECTION INPUT ;
    USE SIGNAL ;
    SHAPE ABUTMENT ;
    PORT
      LAYER M4 ;
      RECT 0.000 47.952 0.024 47.976 ;
    END
  END W0_data[465]
  PIN W0_data[466]
    DIRECTION INPUT ;
    USE SIGNAL ;
    SHAPE ABUTMENT ;
    PORT
      LAYER M4 ;
      RECT 0.000 48.000 0.024 48.024 ;
    END
  END W0_data[466]
  PIN W0_data[467]
    DIRECTION INPUT ;
    USE SIGNAL ;
    SHAPE ABUTMENT ;
    PORT
      LAYER M4 ;
      RECT 0.000 48.048 0.024 48.072 ;
    END
  END W0_data[467]
  PIN W0_data[468]
    DIRECTION INPUT ;
    USE SIGNAL ;
    SHAPE ABUTMENT ;
    PORT
      LAYER M4 ;
      RECT 0.000 48.096 0.024 48.120 ;
    END
  END W0_data[468]
  PIN W0_data[469]
    DIRECTION INPUT ;
    USE SIGNAL ;
    SHAPE ABUTMENT ;
    PORT
      LAYER M4 ;
      RECT 0.000 48.144 0.024 48.168 ;
    END
  END W0_data[469]
  PIN W0_data[470]
    DIRECTION INPUT ;
    USE SIGNAL ;
    SHAPE ABUTMENT ;
    PORT
      LAYER M4 ;
      RECT 0.000 48.192 0.024 48.216 ;
    END
  END W0_data[470]
  PIN W0_data[471]
    DIRECTION INPUT ;
    USE SIGNAL ;
    SHAPE ABUTMENT ;
    PORT
      LAYER M4 ;
      RECT 0.000 48.240 0.024 48.264 ;
    END
  END W0_data[471]
  PIN W0_data[472]
    DIRECTION INPUT ;
    USE SIGNAL ;
    SHAPE ABUTMENT ;
    PORT
      LAYER M4 ;
      RECT 0.000 48.288 0.024 48.312 ;
    END
  END W0_data[472]
  PIN W0_data[473]
    DIRECTION INPUT ;
    USE SIGNAL ;
    SHAPE ABUTMENT ;
    PORT
      LAYER M4 ;
      RECT 0.000 48.336 0.024 48.360 ;
    END
  END W0_data[473]
  PIN W0_data[474]
    DIRECTION INPUT ;
    USE SIGNAL ;
    SHAPE ABUTMENT ;
    PORT
      LAYER M4 ;
      RECT 0.000 48.384 0.024 48.408 ;
    END
  END W0_data[474]
  PIN W0_data[475]
    DIRECTION INPUT ;
    USE SIGNAL ;
    SHAPE ABUTMENT ;
    PORT
      LAYER M4 ;
      RECT 0.000 48.432 0.024 48.456 ;
    END
  END W0_data[475]
  PIN W0_data[476]
    DIRECTION INPUT ;
    USE SIGNAL ;
    SHAPE ABUTMENT ;
    PORT
      LAYER M4 ;
      RECT 0.000 48.480 0.024 48.504 ;
    END
  END W0_data[476]
  PIN W0_data[477]
    DIRECTION INPUT ;
    USE SIGNAL ;
    SHAPE ABUTMENT ;
    PORT
      LAYER M4 ;
      RECT 0.000 48.528 0.024 48.552 ;
    END
  END W0_data[477]
  PIN W0_data[478]
    DIRECTION INPUT ;
    USE SIGNAL ;
    SHAPE ABUTMENT ;
    PORT
      LAYER M4 ;
      RECT 0.000 48.576 0.024 48.600 ;
    END
  END W0_data[478]
  PIN W0_data[479]
    DIRECTION INPUT ;
    USE SIGNAL ;
    SHAPE ABUTMENT ;
    PORT
      LAYER M4 ;
      RECT 0.000 48.624 0.024 48.648 ;
    END
  END W0_data[479]
  PIN W0_data[480]
    DIRECTION INPUT ;
    USE SIGNAL ;
    SHAPE ABUTMENT ;
    PORT
      LAYER M4 ;
      RECT 0.000 48.672 0.024 48.696 ;
    END
  END W0_data[480]
  PIN W0_data[481]
    DIRECTION INPUT ;
    USE SIGNAL ;
    SHAPE ABUTMENT ;
    PORT
      LAYER M4 ;
      RECT 0.000 48.720 0.024 48.744 ;
    END
  END W0_data[481]
  PIN W0_data[482]
    DIRECTION INPUT ;
    USE SIGNAL ;
    SHAPE ABUTMENT ;
    PORT
      LAYER M4 ;
      RECT 0.000 48.768 0.024 48.792 ;
    END
  END W0_data[482]
  PIN W0_data[483]
    DIRECTION INPUT ;
    USE SIGNAL ;
    SHAPE ABUTMENT ;
    PORT
      LAYER M4 ;
      RECT 0.000 48.816 0.024 48.840 ;
    END
  END W0_data[483]
  PIN W0_data[484]
    DIRECTION INPUT ;
    USE SIGNAL ;
    SHAPE ABUTMENT ;
    PORT
      LAYER M4 ;
      RECT 0.000 48.864 0.024 48.888 ;
    END
  END W0_data[484]
  PIN W0_data[485]
    DIRECTION INPUT ;
    USE SIGNAL ;
    SHAPE ABUTMENT ;
    PORT
      LAYER M4 ;
      RECT 0.000 48.912 0.024 48.936 ;
    END
  END W0_data[485]
  PIN W0_data[486]
    DIRECTION INPUT ;
    USE SIGNAL ;
    SHAPE ABUTMENT ;
    PORT
      LAYER M4 ;
      RECT 0.000 48.960 0.024 48.984 ;
    END
  END W0_data[486]
  PIN W0_data[487]
    DIRECTION INPUT ;
    USE SIGNAL ;
    SHAPE ABUTMENT ;
    PORT
      LAYER M4 ;
      RECT 0.000 49.008 0.024 49.032 ;
    END
  END W0_data[487]
  PIN W0_data[488]
    DIRECTION INPUT ;
    USE SIGNAL ;
    SHAPE ABUTMENT ;
    PORT
      LAYER M4 ;
      RECT 0.000 49.056 0.024 49.080 ;
    END
  END W0_data[488]
  PIN W0_data[489]
    DIRECTION INPUT ;
    USE SIGNAL ;
    SHAPE ABUTMENT ;
    PORT
      LAYER M4 ;
      RECT 0.000 49.104 0.024 49.128 ;
    END
  END W0_data[489]
  PIN W0_data[490]
    DIRECTION INPUT ;
    USE SIGNAL ;
    SHAPE ABUTMENT ;
    PORT
      LAYER M4 ;
      RECT 0.000 49.152 0.024 49.176 ;
    END
  END W0_data[490]
  PIN W0_data[491]
    DIRECTION INPUT ;
    USE SIGNAL ;
    SHAPE ABUTMENT ;
    PORT
      LAYER M4 ;
      RECT 0.000 49.200 0.024 49.224 ;
    END
  END W0_data[491]
  PIN W0_data[492]
    DIRECTION INPUT ;
    USE SIGNAL ;
    SHAPE ABUTMENT ;
    PORT
      LAYER M4 ;
      RECT 0.000 49.248 0.024 49.272 ;
    END
  END W0_data[492]
  PIN W0_data[493]
    DIRECTION INPUT ;
    USE SIGNAL ;
    SHAPE ABUTMENT ;
    PORT
      LAYER M4 ;
      RECT 0.000 49.296 0.024 49.320 ;
    END
  END W0_data[493]
  PIN W0_data[494]
    DIRECTION INPUT ;
    USE SIGNAL ;
    SHAPE ABUTMENT ;
    PORT
      LAYER M4 ;
      RECT 0.000 49.344 0.024 49.368 ;
    END
  END W0_data[494]
  PIN W0_data[495]
    DIRECTION INPUT ;
    USE SIGNAL ;
    SHAPE ABUTMENT ;
    PORT
      LAYER M4 ;
      RECT 0.000 49.392 0.024 49.416 ;
    END
  END W0_data[495]
  PIN W0_data[496]
    DIRECTION INPUT ;
    USE SIGNAL ;
    SHAPE ABUTMENT ;
    PORT
      LAYER M4 ;
      RECT 0.000 49.440 0.024 49.464 ;
    END
  END W0_data[496]
  PIN W0_data[497]
    DIRECTION INPUT ;
    USE SIGNAL ;
    SHAPE ABUTMENT ;
    PORT
      LAYER M4 ;
      RECT 0.000 49.488 0.024 49.512 ;
    END
  END W0_data[497]
  PIN W0_data[498]
    DIRECTION INPUT ;
    USE SIGNAL ;
    SHAPE ABUTMENT ;
    PORT
      LAYER M4 ;
      RECT 0.000 49.536 0.024 49.560 ;
    END
  END W0_data[498]
  PIN W0_data[499]
    DIRECTION INPUT ;
    USE SIGNAL ;
    SHAPE ABUTMENT ;
    PORT
      LAYER M4 ;
      RECT 0.000 49.584 0.024 49.608 ;
    END
  END W0_data[499]
  PIN W0_data[500]
    DIRECTION INPUT ;
    USE SIGNAL ;
    SHAPE ABUTMENT ;
    PORT
      LAYER M4 ;
      RECT 0.000 49.632 0.024 49.656 ;
    END
  END W0_data[500]
  PIN W0_data[501]
    DIRECTION INPUT ;
    USE SIGNAL ;
    SHAPE ABUTMENT ;
    PORT
      LAYER M4 ;
      RECT 0.000 49.680 0.024 49.704 ;
    END
  END W0_data[501]
  PIN W0_data[502]
    DIRECTION INPUT ;
    USE SIGNAL ;
    SHAPE ABUTMENT ;
    PORT
      LAYER M4 ;
      RECT 0.000 49.728 0.024 49.752 ;
    END
  END W0_data[502]
  PIN W0_data[503]
    DIRECTION INPUT ;
    USE SIGNAL ;
    SHAPE ABUTMENT ;
    PORT
      LAYER M4 ;
      RECT 0.000 49.776 0.024 49.800 ;
    END
  END W0_data[503]
  PIN W0_data[504]
    DIRECTION INPUT ;
    USE SIGNAL ;
    SHAPE ABUTMENT ;
    PORT
      LAYER M4 ;
      RECT 0.000 49.824 0.024 49.848 ;
    END
  END W0_data[504]
  PIN W0_data[505]
    DIRECTION INPUT ;
    USE SIGNAL ;
    SHAPE ABUTMENT ;
    PORT
      LAYER M4 ;
      RECT 0.000 49.872 0.024 49.896 ;
    END
  END W0_data[505]
  PIN W0_data[506]
    DIRECTION INPUT ;
    USE SIGNAL ;
    SHAPE ABUTMENT ;
    PORT
      LAYER M4 ;
      RECT 0.000 49.920 0.024 49.944 ;
    END
  END W0_data[506]
  PIN W0_data[507]
    DIRECTION INPUT ;
    USE SIGNAL ;
    SHAPE ABUTMENT ;
    PORT
      LAYER M4 ;
      RECT 0.000 49.968 0.024 49.992 ;
    END
  END W0_data[507]
  PIN W0_data[508]
    DIRECTION INPUT ;
    USE SIGNAL ;
    SHAPE ABUTMENT ;
    PORT
      LAYER M4 ;
      RECT 0.000 50.016 0.024 50.040 ;
    END
  END W0_data[508]
  PIN W0_data[509]
    DIRECTION INPUT ;
    USE SIGNAL ;
    SHAPE ABUTMENT ;
    PORT
      LAYER M4 ;
      RECT 0.000 50.064 0.024 50.088 ;
    END
  END W0_data[509]
  PIN W0_data[510]
    DIRECTION INPUT ;
    USE SIGNAL ;
    SHAPE ABUTMENT ;
    PORT
      LAYER M4 ;
      RECT 0.000 50.112 0.024 50.136 ;
    END
  END W0_data[510]
  PIN W0_data[511]
    DIRECTION INPUT ;
    USE SIGNAL ;
    SHAPE ABUTMENT ;
    PORT
      LAYER M4 ;
      RECT 0.000 50.160 0.024 50.184 ;
    END
  END W0_data[511]
  PIN W0_en
    DIRECTION INPUT ;
    USE SIGNAL ;
    SHAPE ABUTMENT ;
    PORT
      LAYER M4 ;
      RECT 0.000 50.208 0.024 50.232 ;
    END
  END W0_en
  PIN W0_mask[0]
    DIRECTION INPUT ;
    USE SIGNAL ;
    SHAPE ABUTMENT ;
    PORT
      LAYER M4 ;
      RECT 0.000 50.256 0.024 50.280 ;
    END
  END W0_mask[0]
  PIN W0_mask[1]
    DIRECTION INPUT ;
    USE SIGNAL ;
    SHAPE ABUTMENT ;
    PORT
      LAYER M4 ;
      RECT 0.000 50.304 0.024 50.328 ;
    END
  END W0_mask[1]
  PIN W0_mask[2]
    DIRECTION INPUT ;
    USE SIGNAL ;
    SHAPE ABUTMENT ;
    PORT
      LAYER M4 ;
      RECT 0.000 50.352 0.024 50.376 ;
    END
  END W0_mask[2]
  PIN W0_mask[3]
    DIRECTION INPUT ;
    USE SIGNAL ;
    SHAPE ABUTMENT ;
    PORT
      LAYER M4 ;
      RECT 0.000 50.400 0.024 50.424 ;
    END
  END W0_mask[3]
  PIN W0_mask[4]
    DIRECTION INPUT ;
    USE SIGNAL ;
    SHAPE ABUTMENT ;
    PORT
      LAYER M4 ;
      RECT 0.000 50.448 0.024 50.472 ;
    END
  END W0_mask[4]
  PIN W0_mask[5]
    DIRECTION INPUT ;
    USE SIGNAL ;
    SHAPE ABUTMENT ;
    PORT
      LAYER M4 ;
      RECT 0.000 50.496 0.024 50.520 ;
    END
  END W0_mask[5]
  PIN W0_mask[6]
    DIRECTION INPUT ;
    USE SIGNAL ;
    SHAPE ABUTMENT ;
    PORT
      LAYER M4 ;
      RECT 0.000 50.544 0.024 50.568 ;
    END
  END W0_mask[6]
  PIN W0_mask[7]
    DIRECTION INPUT ;
    USE SIGNAL ;
    SHAPE ABUTMENT ;
    PORT
      LAYER M4 ;
      RECT 0.000 50.592 0.024 50.616 ;
    END
  END W0_mask[7]
  PIN W0_mask[8]
    DIRECTION INPUT ;
    USE SIGNAL ;
    SHAPE ABUTMENT ;
    PORT
      LAYER M4 ;
      RECT 0.000 50.640 0.024 50.664 ;
    END
  END W0_mask[8]
  PIN W0_mask[9]
    DIRECTION INPUT ;
    USE SIGNAL ;
    SHAPE ABUTMENT ;
    PORT
      LAYER M4 ;
      RECT 0.000 50.688 0.024 50.712 ;
    END
  END W0_mask[9]
  PIN W0_mask[10]
    DIRECTION INPUT ;
    USE SIGNAL ;
    SHAPE ABUTMENT ;
    PORT
      LAYER M4 ;
      RECT 0.000 50.736 0.024 50.760 ;
    END
  END W0_mask[10]
  PIN W0_mask[11]
    DIRECTION INPUT ;
    USE SIGNAL ;
    SHAPE ABUTMENT ;
    PORT
      LAYER M4 ;
      RECT 0.000 50.784 0.024 50.808 ;
    END
  END W0_mask[11]
  PIN W0_mask[12]
    DIRECTION INPUT ;
    USE SIGNAL ;
    SHAPE ABUTMENT ;
    PORT
      LAYER M4 ;
      RECT 0.000 50.832 0.024 50.856 ;
    END
  END W0_mask[12]
  PIN W0_mask[13]
    DIRECTION INPUT ;
    USE SIGNAL ;
    SHAPE ABUTMENT ;
    PORT
      LAYER M4 ;
      RECT 0.000 50.880 0.024 50.904 ;
    END
  END W0_mask[13]
  PIN W0_mask[14]
    DIRECTION INPUT ;
    USE SIGNAL ;
    SHAPE ABUTMENT ;
    PORT
      LAYER M4 ;
      RECT 0.000 50.928 0.024 50.952 ;
    END
  END W0_mask[14]
  PIN W0_mask[15]
    DIRECTION INPUT ;
    USE SIGNAL ;
    SHAPE ABUTMENT ;
    PORT
      LAYER M4 ;
      RECT 0.000 50.976 0.024 51.000 ;
    END
  END W0_mask[15]
  PIN W0_mask[16]
    DIRECTION INPUT ;
    USE SIGNAL ;
    SHAPE ABUTMENT ;
    PORT
      LAYER M4 ;
      RECT 0.000 51.024 0.024 51.048 ;
    END
  END W0_mask[16]
  PIN W0_mask[17]
    DIRECTION INPUT ;
    USE SIGNAL ;
    SHAPE ABUTMENT ;
    PORT
      LAYER M4 ;
      RECT 0.000 51.072 0.024 51.096 ;
    END
  END W0_mask[17]
  PIN W0_mask[18]
    DIRECTION INPUT ;
    USE SIGNAL ;
    SHAPE ABUTMENT ;
    PORT
      LAYER M4 ;
      RECT 0.000 51.120 0.024 51.144 ;
    END
  END W0_mask[18]
  PIN W0_mask[19]
    DIRECTION INPUT ;
    USE SIGNAL ;
    SHAPE ABUTMENT ;
    PORT
      LAYER M4 ;
      RECT 0.000 51.168 0.024 51.192 ;
    END
  END W0_mask[19]
  PIN W0_mask[20]
    DIRECTION INPUT ;
    USE SIGNAL ;
    SHAPE ABUTMENT ;
    PORT
      LAYER M4 ;
      RECT 0.000 51.216 0.024 51.240 ;
    END
  END W0_mask[20]
  PIN W0_mask[21]
    DIRECTION INPUT ;
    USE SIGNAL ;
    SHAPE ABUTMENT ;
    PORT
      LAYER M4 ;
      RECT 0.000 51.264 0.024 51.288 ;
    END
  END W0_mask[21]
  PIN W0_mask[22]
    DIRECTION INPUT ;
    USE SIGNAL ;
    SHAPE ABUTMENT ;
    PORT
      LAYER M4 ;
      RECT 0.000 51.312 0.024 51.336 ;
    END
  END W0_mask[22]
  PIN W0_mask[23]
    DIRECTION INPUT ;
    USE SIGNAL ;
    SHAPE ABUTMENT ;
    PORT
      LAYER M4 ;
      RECT 0.000 51.360 0.024 51.384 ;
    END
  END W0_mask[23]
  PIN W0_mask[24]
    DIRECTION INPUT ;
    USE SIGNAL ;
    SHAPE ABUTMENT ;
    PORT
      LAYER M4 ;
      RECT 0.000 51.408 0.024 51.432 ;
    END
  END W0_mask[24]
  PIN W0_mask[25]
    DIRECTION INPUT ;
    USE SIGNAL ;
    SHAPE ABUTMENT ;
    PORT
      LAYER M4 ;
      RECT 0.000 51.456 0.024 51.480 ;
    END
  END W0_mask[25]
  PIN W0_mask[26]
    DIRECTION INPUT ;
    USE SIGNAL ;
    SHAPE ABUTMENT ;
    PORT
      LAYER M4 ;
      RECT 0.000 51.504 0.024 51.528 ;
    END
  END W0_mask[26]
  PIN W0_mask[27]
    DIRECTION INPUT ;
    USE SIGNAL ;
    SHAPE ABUTMENT ;
    PORT
      LAYER M4 ;
      RECT 0.000 51.552 0.024 51.576 ;
    END
  END W0_mask[27]
  PIN W0_mask[28]
    DIRECTION INPUT ;
    USE SIGNAL ;
    SHAPE ABUTMENT ;
    PORT
      LAYER M4 ;
      RECT 0.000 51.600 0.024 51.624 ;
    END
  END W0_mask[28]
  PIN W0_mask[29]
    DIRECTION INPUT ;
    USE SIGNAL ;
    SHAPE ABUTMENT ;
    PORT
      LAYER M4 ;
      RECT 0.000 51.648 0.024 51.672 ;
    END
  END W0_mask[29]
  PIN W0_mask[30]
    DIRECTION INPUT ;
    USE SIGNAL ;
    SHAPE ABUTMENT ;
    PORT
      LAYER M4 ;
      RECT 0.000 51.696 0.024 51.720 ;
    END
  END W0_mask[30]
  PIN W0_mask[31]
    DIRECTION INPUT ;
    USE SIGNAL ;
    SHAPE ABUTMENT ;
    PORT
      LAYER M4 ;
      RECT 0.000 51.744 0.024 51.768 ;
    END
  END W0_mask[31]
  PIN W0_mask[32]
    DIRECTION INPUT ;
    USE SIGNAL ;
    SHAPE ABUTMENT ;
    PORT
      LAYER M4 ;
      RECT 0.000 51.792 0.024 51.816 ;
    END
  END W0_mask[32]
  PIN W0_mask[33]
    DIRECTION INPUT ;
    USE SIGNAL ;
    SHAPE ABUTMENT ;
    PORT
      LAYER M4 ;
      RECT 0.000 51.840 0.024 51.864 ;
    END
  END W0_mask[33]
  PIN W0_mask[34]
    DIRECTION INPUT ;
    USE SIGNAL ;
    SHAPE ABUTMENT ;
    PORT
      LAYER M4 ;
      RECT 0.000 51.888 0.024 51.912 ;
    END
  END W0_mask[34]
  PIN W0_mask[35]
    DIRECTION INPUT ;
    USE SIGNAL ;
    SHAPE ABUTMENT ;
    PORT
      LAYER M4 ;
      RECT 0.000 51.936 0.024 51.960 ;
    END
  END W0_mask[35]
  PIN W0_mask[36]
    DIRECTION INPUT ;
    USE SIGNAL ;
    SHAPE ABUTMENT ;
    PORT
      LAYER M4 ;
      RECT 0.000 51.984 0.024 52.008 ;
    END
  END W0_mask[36]
  PIN W0_mask[37]
    DIRECTION INPUT ;
    USE SIGNAL ;
    SHAPE ABUTMENT ;
    PORT
      LAYER M4 ;
      RECT 0.000 52.032 0.024 52.056 ;
    END
  END W0_mask[37]
  PIN W0_mask[38]
    DIRECTION INPUT ;
    USE SIGNAL ;
    SHAPE ABUTMENT ;
    PORT
      LAYER M4 ;
      RECT 0.000 52.080 0.024 52.104 ;
    END
  END W0_mask[38]
  PIN W0_mask[39]
    DIRECTION INPUT ;
    USE SIGNAL ;
    SHAPE ABUTMENT ;
    PORT
      LAYER M4 ;
      RECT 0.000 52.128 0.024 52.152 ;
    END
  END W0_mask[39]
  PIN W0_mask[40]
    DIRECTION INPUT ;
    USE SIGNAL ;
    SHAPE ABUTMENT ;
    PORT
      LAYER M4 ;
      RECT 0.000 52.176 0.024 52.200 ;
    END
  END W0_mask[40]
  PIN W0_mask[41]
    DIRECTION INPUT ;
    USE SIGNAL ;
    SHAPE ABUTMENT ;
    PORT
      LAYER M4 ;
      RECT 0.000 52.224 0.024 52.248 ;
    END
  END W0_mask[41]
  PIN W0_mask[42]
    DIRECTION INPUT ;
    USE SIGNAL ;
    SHAPE ABUTMENT ;
    PORT
      LAYER M4 ;
      RECT 0.000 52.272 0.024 52.296 ;
    END
  END W0_mask[42]
  PIN W0_mask[43]
    DIRECTION INPUT ;
    USE SIGNAL ;
    SHAPE ABUTMENT ;
    PORT
      LAYER M4 ;
      RECT 0.000 52.320 0.024 52.344 ;
    END
  END W0_mask[43]
  PIN W0_mask[44]
    DIRECTION INPUT ;
    USE SIGNAL ;
    SHAPE ABUTMENT ;
    PORT
      LAYER M4 ;
      RECT 0.000 52.368 0.024 52.392 ;
    END
  END W0_mask[44]
  PIN W0_mask[45]
    DIRECTION INPUT ;
    USE SIGNAL ;
    SHAPE ABUTMENT ;
    PORT
      LAYER M4 ;
      RECT 0.000 52.416 0.024 52.440 ;
    END
  END W0_mask[45]
  PIN W0_mask[46]
    DIRECTION INPUT ;
    USE SIGNAL ;
    SHAPE ABUTMENT ;
    PORT
      LAYER M4 ;
      RECT 0.000 52.464 0.024 52.488 ;
    END
  END W0_mask[46]
  PIN W0_mask[47]
    DIRECTION INPUT ;
    USE SIGNAL ;
    SHAPE ABUTMENT ;
    PORT
      LAYER M4 ;
      RECT 0.000 52.512 0.024 52.536 ;
    END
  END W0_mask[47]
  PIN W0_mask[48]
    DIRECTION INPUT ;
    USE SIGNAL ;
    SHAPE ABUTMENT ;
    PORT
      LAYER M4 ;
      RECT 0.000 52.560 0.024 52.584 ;
    END
  END W0_mask[48]
  PIN W0_mask[49]
    DIRECTION INPUT ;
    USE SIGNAL ;
    SHAPE ABUTMENT ;
    PORT
      LAYER M4 ;
      RECT 0.000 52.608 0.024 52.632 ;
    END
  END W0_mask[49]
  PIN W0_mask[50]
    DIRECTION INPUT ;
    USE SIGNAL ;
    SHAPE ABUTMENT ;
    PORT
      LAYER M4 ;
      RECT 0.000 52.656 0.024 52.680 ;
    END
  END W0_mask[50]
  PIN W0_mask[51]
    DIRECTION INPUT ;
    USE SIGNAL ;
    SHAPE ABUTMENT ;
    PORT
      LAYER M4 ;
      RECT 0.000 52.704 0.024 52.728 ;
    END
  END W0_mask[51]
  PIN W0_mask[52]
    DIRECTION INPUT ;
    USE SIGNAL ;
    SHAPE ABUTMENT ;
    PORT
      LAYER M4 ;
      RECT 0.000 52.752 0.024 52.776 ;
    END
  END W0_mask[52]
  PIN W0_mask[53]
    DIRECTION INPUT ;
    USE SIGNAL ;
    SHAPE ABUTMENT ;
    PORT
      LAYER M4 ;
      RECT 0.000 52.800 0.024 52.824 ;
    END
  END W0_mask[53]
  PIN W0_mask[54]
    DIRECTION INPUT ;
    USE SIGNAL ;
    SHAPE ABUTMENT ;
    PORT
      LAYER M4 ;
      RECT 0.000 52.848 0.024 52.872 ;
    END
  END W0_mask[54]
  PIN W0_mask[55]
    DIRECTION INPUT ;
    USE SIGNAL ;
    SHAPE ABUTMENT ;
    PORT
      LAYER M4 ;
      RECT 0.000 52.896 0.024 52.920 ;
    END
  END W0_mask[55]
  PIN W0_mask[56]
    DIRECTION INPUT ;
    USE SIGNAL ;
    SHAPE ABUTMENT ;
    PORT
      LAYER M4 ;
      RECT 0.000 52.944 0.024 52.968 ;
    END
  END W0_mask[56]
  PIN W0_mask[57]
    DIRECTION INPUT ;
    USE SIGNAL ;
    SHAPE ABUTMENT ;
    PORT
      LAYER M4 ;
      RECT 0.000 52.992 0.024 53.016 ;
    END
  END W0_mask[57]
  PIN W0_mask[58]
    DIRECTION INPUT ;
    USE SIGNAL ;
    SHAPE ABUTMENT ;
    PORT
      LAYER M4 ;
      RECT 0.000 53.040 0.024 53.064 ;
    END
  END W0_mask[58]
  PIN W0_mask[59]
    DIRECTION INPUT ;
    USE SIGNAL ;
    SHAPE ABUTMENT ;
    PORT
      LAYER M4 ;
      RECT 0.000 53.088 0.024 53.112 ;
    END
  END W0_mask[59]
  PIN W0_mask[60]
    DIRECTION INPUT ;
    USE SIGNAL ;
    SHAPE ABUTMENT ;
    PORT
      LAYER M4 ;
      RECT 0.000 53.136 0.024 53.160 ;
    END
  END W0_mask[60]
  PIN W0_mask[61]
    DIRECTION INPUT ;
    USE SIGNAL ;
    SHAPE ABUTMENT ;
    PORT
      LAYER M4 ;
      RECT 0.000 53.184 0.024 53.208 ;
    END
  END W0_mask[61]
  PIN W0_mask[62]
    DIRECTION INPUT ;
    USE SIGNAL ;
    SHAPE ABUTMENT ;
    PORT
      LAYER M4 ;
      RECT 0.000 53.232 0.024 53.256 ;
    END
  END W0_mask[62]
  PIN W0_mask[63]
    DIRECTION INPUT ;
    USE SIGNAL ;
    SHAPE ABUTMENT ;
    PORT
      LAYER M4 ;
      RECT 0.000 53.280 0.024 53.304 ;
    END
  END W0_mask[63]
  PIN VSS
    DIRECTION INOUT ;
    USE GROUND ;
    PORT
      LAYER M4 ;
      RECT 0.096 0.432 66.784 0.528 ;
      RECT 0.096 1.968 66.784 2.064 ;
      RECT 0.096 3.504 66.784 3.600 ;
      RECT 0.096 5.040 66.784 5.136 ;
      RECT 0.096 6.576 66.784 6.672 ;
      RECT 0.096 8.112 66.784 8.208 ;
      RECT 0.096 9.648 66.784 9.744 ;
      RECT 0.096 11.184 66.784 11.280 ;
      RECT 0.096 12.720 66.784 12.816 ;
      RECT 0.096 14.256 66.784 14.352 ;
      RECT 0.096 15.792 66.784 15.888 ;
      RECT 0.096 17.328 66.784 17.424 ;
      RECT 0.096 18.864 66.784 18.960 ;
      RECT 0.096 20.400 66.784 20.496 ;
      RECT 0.096 21.936 66.784 22.032 ;
      RECT 0.096 23.472 66.784 23.568 ;
      RECT 0.096 25.008 66.784 25.104 ;
      RECT 0.096 26.544 66.784 26.640 ;
      RECT 0.096 28.080 66.784 28.176 ;
      RECT 0.096 29.616 66.784 29.712 ;
      RECT 0.096 31.152 66.784 31.248 ;
      RECT 0.096 32.688 66.784 32.784 ;
      RECT 0.096 34.224 66.784 34.320 ;
      RECT 0.096 35.760 66.784 35.856 ;
      RECT 0.096 37.296 66.784 37.392 ;
      RECT 0.096 38.832 66.784 38.928 ;
      RECT 0.096 40.368 66.784 40.464 ;
      RECT 0.096 41.904 66.784 42.000 ;
      RECT 0.096 43.440 66.784 43.536 ;
      RECT 0.096 44.976 66.784 45.072 ;
      RECT 0.096 46.512 66.784 46.608 ;
      RECT 0.096 48.048 66.784 48.144 ;
      RECT 0.096 49.584 66.784 49.680 ;
      RECT 0.096 51.120 66.784 51.216 ;
      RECT 0.096 52.656 66.784 52.752 ;
      RECT 0.096 54.192 66.784 54.288 ;
      RECT 0.096 55.728 66.784 55.824 ;
      RECT 0.096 57.264 66.784 57.360 ;
      RECT 0.096 58.800 66.784 58.896 ;
      RECT 0.096 60.336 66.784 60.432 ;
      RECT 0.096 61.872 66.784 61.968 ;
      RECT 0.096 63.408 66.784 63.504 ;
      RECT 0.096 64.944 66.784 65.040 ;
      RECT 0.096 66.480 66.784 66.576 ;
      RECT 0.096 68.016 66.784 68.112 ;
      RECT 0.096 69.552 66.784 69.648 ;
      RECT 0.096 71.088 66.784 71.184 ;
      RECT 0.096 72.624 66.784 72.720 ;
      RECT 0.096 74.160 66.784 74.256 ;
      RECT 0.096 75.696 66.784 75.792 ;
      RECT 0.096 77.232 66.784 77.328 ;
      RECT 0.096 78.768 66.784 78.864 ;
      RECT 0.096 80.304 66.784 80.400 ;
      RECT 0.096 81.840 66.784 81.936 ;
      RECT 0.096 83.376 66.784 83.472 ;
      RECT 0.096 84.912 66.784 85.008 ;
      RECT 0.096 86.448 66.784 86.544 ;
      RECT 0.096 87.984 66.784 88.080 ;
      RECT 0.096 89.520 66.784 89.616 ;
      RECT 0.096 91.056 66.784 91.152 ;
      RECT 0.096 92.592 66.784 92.688 ;
      RECT 0.096 94.128 66.784 94.224 ;
      RECT 0.096 95.664 66.784 95.760 ;
      RECT 0.096 97.200 66.784 97.296 ;
      RECT 0.096 98.736 66.784 98.832 ;
      RECT 0.096 100.272 66.784 100.368 ;
      RECT 0.096 101.808 66.784 101.904 ;
      RECT 0.096 103.344 66.784 103.440 ;
      RECT 0.096 104.880 66.784 104.976 ;
      RECT 0.096 106.416 66.784 106.512 ;
      RECT 0.096 107.952 66.784 108.048 ;
      RECT 0.096 109.488 66.784 109.584 ;
      RECT 0.096 111.024 66.784 111.120 ;
      RECT 0.096 112.560 66.784 112.656 ;
      RECT 0.096 114.096 66.784 114.192 ;
      RECT 0.096 115.632 66.784 115.728 ;
      RECT 0.096 117.168 66.784 117.264 ;
      RECT 0.096 118.704 66.784 118.800 ;
      RECT 0.096 120.240 66.784 120.336 ;
      RECT 0.096 121.776 66.784 121.872 ;
      RECT 0.096 123.312 66.784 123.408 ;
      RECT 0.096 124.848 66.784 124.944 ;
      RECT 0.096 126.384 66.784 126.480 ;
      RECT 0.096 127.920 66.784 128.016 ;
      RECT 0.096 129.456 66.784 129.552 ;
      RECT 0.096 130.992 66.784 131.088 ;
      RECT 0.096 132.528 66.784 132.624 ;
      RECT 0.096 134.064 66.784 134.160 ;
      RECT 0.096 135.600 66.784 135.696 ;
      RECT 0.096 137.136 66.784 137.232 ;
      RECT 0.096 138.672 66.784 138.768 ;
      RECT 0.096 140.208 66.784 140.304 ;
      RECT 0.096 141.744 66.784 141.840 ;
      RECT 0.096 143.280 66.784 143.376 ;
      RECT 0.096 144.816 66.784 144.912 ;
      RECT 0.096 146.352 66.784 146.448 ;
      RECT 0.096 147.888 66.784 147.984 ;
      RECT 0.096 149.424 66.784 149.520 ;
      RECT 0.096 150.960 66.784 151.056 ;
      RECT 0.096 152.496 66.784 152.592 ;
      RECT 0.096 154.032 66.784 154.128 ;
      RECT 0.096 155.568 66.784 155.664 ;
      RECT 0.096 157.104 66.784 157.200 ;
      RECT 0.096 158.640 66.784 158.736 ;
      RECT 0.096 160.176 66.784 160.272 ;
      RECT 0.096 161.712 66.784 161.808 ;
      RECT 0.096 163.248 66.784 163.344 ;
      RECT 0.096 164.784 66.784 164.880 ;
      RECT 0.096 166.320 66.784 166.416 ;
      RECT 0.096 167.856 66.784 167.952 ;
      RECT 0.096 169.392 66.784 169.488 ;
      RECT 0.096 170.928 66.784 171.024 ;
      RECT 0.096 172.464 66.784 172.560 ;
      RECT 0.096 174.000 66.784 174.096 ;
      RECT 0.096 175.536 66.784 175.632 ;
      RECT 0.096 177.072 66.784 177.168 ;
      RECT 0.096 178.608 66.784 178.704 ;
      RECT 0.096 180.144 66.784 180.240 ;
      RECT 0.096 181.680 66.784 181.776 ;
      RECT 0.096 183.216 66.784 183.312 ;
      RECT 0.096 184.752 66.784 184.848 ;
      RECT 0.096 186.288 66.784 186.384 ;
      RECT 0.096 187.824 66.784 187.920 ;
      RECT 0.096 189.360 66.784 189.456 ;
      RECT 0.096 190.896 66.784 190.992 ;
      RECT 0.096 192.432 66.784 192.528 ;
      RECT 0.096 193.968 66.784 194.064 ;
      RECT 0.096 195.504 66.784 195.600 ;
      RECT 0.096 197.040 66.784 197.136 ;
      RECT 0.096 198.576 66.784 198.672 ;
      RECT 0.096 200.112 66.784 200.208 ;
      RECT 0.096 201.648 66.784 201.744 ;
      RECT 0.096 203.184 66.784 203.280 ;
      RECT 0.096 204.720 66.784 204.816 ;
      RECT 0.096 206.256 66.784 206.352 ;
      RECT 0.096 207.792 66.784 207.888 ;
      RECT 0.096 209.328 66.784 209.424 ;
      RECT 0.096 210.864 66.784 210.960 ;
      RECT 0.096 212.400 66.784 212.496 ;
      RECT 0.096 213.936 66.784 214.032 ;
      RECT 0.096 215.472 66.784 215.568 ;
      RECT 0.096 217.008 66.784 217.104 ;
      RECT 0.096 218.544 66.784 218.640 ;
      RECT 0.096 220.080 66.784 220.176 ;
      RECT 0.096 221.616 66.784 221.712 ;
      RECT 0.096 223.152 66.784 223.248 ;
    END
  END VSS
  PIN VDD
    DIRECTION INOUT ;
    USE POWER ;
    PORT
      LAYER M4 ;
      RECT 0.096 0.816 66.784 0.912 ;
      RECT 0.096 2.352 66.784 2.448 ;
      RECT 0.096 3.888 66.784 3.984 ;
      RECT 0.096 5.424 66.784 5.520 ;
      RECT 0.096 6.960 66.784 7.056 ;
      RECT 0.096 8.496 66.784 8.592 ;
      RECT 0.096 10.032 66.784 10.128 ;
      RECT 0.096 11.568 66.784 11.664 ;
      RECT 0.096 13.104 66.784 13.200 ;
      RECT 0.096 14.640 66.784 14.736 ;
      RECT 0.096 16.176 66.784 16.272 ;
      RECT 0.096 17.712 66.784 17.808 ;
      RECT 0.096 19.248 66.784 19.344 ;
      RECT 0.096 20.784 66.784 20.880 ;
      RECT 0.096 22.320 66.784 22.416 ;
      RECT 0.096 23.856 66.784 23.952 ;
      RECT 0.096 25.392 66.784 25.488 ;
      RECT 0.096 26.928 66.784 27.024 ;
      RECT 0.096 28.464 66.784 28.560 ;
      RECT 0.096 30.000 66.784 30.096 ;
      RECT 0.096 31.536 66.784 31.632 ;
      RECT 0.096 33.072 66.784 33.168 ;
      RECT 0.096 34.608 66.784 34.704 ;
      RECT 0.096 36.144 66.784 36.240 ;
      RECT 0.096 37.680 66.784 37.776 ;
      RECT 0.096 39.216 66.784 39.312 ;
      RECT 0.096 40.752 66.784 40.848 ;
      RECT 0.096 42.288 66.784 42.384 ;
      RECT 0.096 43.824 66.784 43.920 ;
      RECT 0.096 45.360 66.784 45.456 ;
      RECT 0.096 46.896 66.784 46.992 ;
      RECT 0.096 48.432 66.784 48.528 ;
      RECT 0.096 49.968 66.784 50.064 ;
      RECT 0.096 51.504 66.784 51.600 ;
      RECT 0.096 53.040 66.784 53.136 ;
      RECT 0.096 54.576 66.784 54.672 ;
      RECT 0.096 56.112 66.784 56.208 ;
      RECT 0.096 57.648 66.784 57.744 ;
      RECT 0.096 59.184 66.784 59.280 ;
      RECT 0.096 60.720 66.784 60.816 ;
      RECT 0.096 62.256 66.784 62.352 ;
      RECT 0.096 63.792 66.784 63.888 ;
      RECT 0.096 65.328 66.784 65.424 ;
      RECT 0.096 66.864 66.784 66.960 ;
      RECT 0.096 68.400 66.784 68.496 ;
      RECT 0.096 69.936 66.784 70.032 ;
      RECT 0.096 71.472 66.784 71.568 ;
      RECT 0.096 73.008 66.784 73.104 ;
      RECT 0.096 74.544 66.784 74.640 ;
      RECT 0.096 76.080 66.784 76.176 ;
      RECT 0.096 77.616 66.784 77.712 ;
      RECT 0.096 79.152 66.784 79.248 ;
      RECT 0.096 80.688 66.784 80.784 ;
      RECT 0.096 82.224 66.784 82.320 ;
      RECT 0.096 83.760 66.784 83.856 ;
      RECT 0.096 85.296 66.784 85.392 ;
      RECT 0.096 86.832 66.784 86.928 ;
      RECT 0.096 88.368 66.784 88.464 ;
      RECT 0.096 89.904 66.784 90.000 ;
      RECT 0.096 91.440 66.784 91.536 ;
      RECT 0.096 92.976 66.784 93.072 ;
      RECT 0.096 94.512 66.784 94.608 ;
      RECT 0.096 96.048 66.784 96.144 ;
      RECT 0.096 97.584 66.784 97.680 ;
      RECT 0.096 99.120 66.784 99.216 ;
      RECT 0.096 100.656 66.784 100.752 ;
      RECT 0.096 102.192 66.784 102.288 ;
      RECT 0.096 103.728 66.784 103.824 ;
      RECT 0.096 105.264 66.784 105.360 ;
      RECT 0.096 106.800 66.784 106.896 ;
      RECT 0.096 108.336 66.784 108.432 ;
      RECT 0.096 109.872 66.784 109.968 ;
      RECT 0.096 111.408 66.784 111.504 ;
      RECT 0.096 112.944 66.784 113.040 ;
      RECT 0.096 114.480 66.784 114.576 ;
      RECT 0.096 116.016 66.784 116.112 ;
      RECT 0.096 117.552 66.784 117.648 ;
      RECT 0.096 119.088 66.784 119.184 ;
      RECT 0.096 120.624 66.784 120.720 ;
      RECT 0.096 122.160 66.784 122.256 ;
      RECT 0.096 123.696 66.784 123.792 ;
      RECT 0.096 125.232 66.784 125.328 ;
      RECT 0.096 126.768 66.784 126.864 ;
      RECT 0.096 128.304 66.784 128.400 ;
      RECT 0.096 129.840 66.784 129.936 ;
      RECT 0.096 131.376 66.784 131.472 ;
      RECT 0.096 132.912 66.784 133.008 ;
      RECT 0.096 134.448 66.784 134.544 ;
      RECT 0.096 135.984 66.784 136.080 ;
      RECT 0.096 137.520 66.784 137.616 ;
      RECT 0.096 139.056 66.784 139.152 ;
      RECT 0.096 140.592 66.784 140.688 ;
      RECT 0.096 142.128 66.784 142.224 ;
      RECT 0.096 143.664 66.784 143.760 ;
      RECT 0.096 145.200 66.784 145.296 ;
      RECT 0.096 146.736 66.784 146.832 ;
      RECT 0.096 148.272 66.784 148.368 ;
      RECT 0.096 149.808 66.784 149.904 ;
      RECT 0.096 151.344 66.784 151.440 ;
      RECT 0.096 152.880 66.784 152.976 ;
      RECT 0.096 154.416 66.784 154.512 ;
      RECT 0.096 155.952 66.784 156.048 ;
      RECT 0.096 157.488 66.784 157.584 ;
      RECT 0.096 159.024 66.784 159.120 ;
      RECT 0.096 160.560 66.784 160.656 ;
      RECT 0.096 162.096 66.784 162.192 ;
      RECT 0.096 163.632 66.784 163.728 ;
      RECT 0.096 165.168 66.784 165.264 ;
      RECT 0.096 166.704 66.784 166.800 ;
      RECT 0.096 168.240 66.784 168.336 ;
      RECT 0.096 169.776 66.784 169.872 ;
      RECT 0.096 171.312 66.784 171.408 ;
      RECT 0.096 172.848 66.784 172.944 ;
      RECT 0.096 174.384 66.784 174.480 ;
      RECT 0.096 175.920 66.784 176.016 ;
      RECT 0.096 177.456 66.784 177.552 ;
      RECT 0.096 178.992 66.784 179.088 ;
      RECT 0.096 180.528 66.784 180.624 ;
      RECT 0.096 182.064 66.784 182.160 ;
      RECT 0.096 183.600 66.784 183.696 ;
      RECT 0.096 185.136 66.784 185.232 ;
      RECT 0.096 186.672 66.784 186.768 ;
      RECT 0.096 188.208 66.784 188.304 ;
      RECT 0.096 189.744 66.784 189.840 ;
      RECT 0.096 191.280 66.784 191.376 ;
      RECT 0.096 192.816 66.784 192.912 ;
      RECT 0.096 194.352 66.784 194.448 ;
      RECT 0.096 195.888 66.784 195.984 ;
      RECT 0.096 197.424 66.784 197.520 ;
      RECT 0.096 198.960 66.784 199.056 ;
      RECT 0.096 200.496 66.784 200.592 ;
      RECT 0.096 202.032 66.784 202.128 ;
      RECT 0.096 203.568 66.784 203.664 ;
      RECT 0.096 205.104 66.784 205.200 ;
      RECT 0.096 206.640 66.784 206.736 ;
      RECT 0.096 208.176 66.784 208.272 ;
      RECT 0.096 209.712 66.784 209.808 ;
      RECT 0.096 211.248 66.784 211.344 ;
      RECT 0.096 212.784 66.784 212.880 ;
      RECT 0.096 214.320 66.784 214.416 ;
      RECT 0.096 215.856 66.784 215.952 ;
      RECT 0.096 217.392 66.784 217.488 ;
      RECT 0.096 218.928 66.784 219.024 ;
      RECT 0.096 220.464 66.784 220.560 ;
      RECT 0.096 222.000 66.784 222.096 ;
      RECT 0.096 223.536 66.784 223.632 ;
    END
  END VDD
  OBS
    LAYER M1 ; RECT 0 0 66.880 224.000 ;
    LAYER M2 ; RECT 0 0 66.880 224.000 ;
    LAYER M3 ; RECT 0 0 66.880 224.000 ;
  END
END mem_0_ext_bottom

END LIBRARY
